VERSION 5.8 ;
BUSBITCHARS "[]" ;
DIVIDERCHAR "/" ;
UNITS
    DATABASE MICRONS 1000 ;
END UNITS

VIA stack_unit_16_8_via1_2_1000_440_1_2_410_410
  VIARULE via1Array ;
  CUTSIZE 0.19 0.19 ;
  LAYERS Metal1 Via1 Metal2 ;
  CUTSPACING 0.22 0.22 ;
  ENCLOSURE 0.05 0.125 0.005 0.05 ;
  ROWCOL 1 2 ;
END stack_unit_16_8_via1_2_1000_440_1_2_410_410

VIA stack_unit_16_8_via2_3_1000_440_1_2_410_410
  VIARULE via2Array ;
  CUTSIZE 0.19 0.19 ;
  LAYERS Metal2 Via2 Metal3 ;
  CUTSPACING 0.22 0.22 ;
  ENCLOSURE 0.005 0.05 0.05 0.005 ;
  ROWCOL 1 2 ;
END stack_unit_16_8_via2_3_1000_440_1_2_410_410

VIA stack_unit_16_8_via3_4_1000_440_1_2_410_410
  VIARULE via3Array ;
  CUTSIZE 0.19 0.19 ;
  LAYERS Metal3 Via3 Metal4 ;
  CUTSPACING 0.22 0.22 ;
  ENCLOSURE 0.05 0.005 0.2 0.05 ;
  ROWCOL 1 2 ;
END stack_unit_16_8_via3_4_1000_440_1_2_410_410

VIA stack_unit_16_8_via4_5_1000_2000_1_1_840_840
  VIARULE viaTop1Array ;
  CUTSIZE 0.42 0.42 ;
  LAYERS Metal4 TopVia1 TopMetal1 ;
  CUTSPACING 0.42 0.42 ;
  ENCLOSURE 0.29 0.1 0.42 0.79 ;
END stack_unit_16_8_via4_5_1000_2000_1_1_840_840

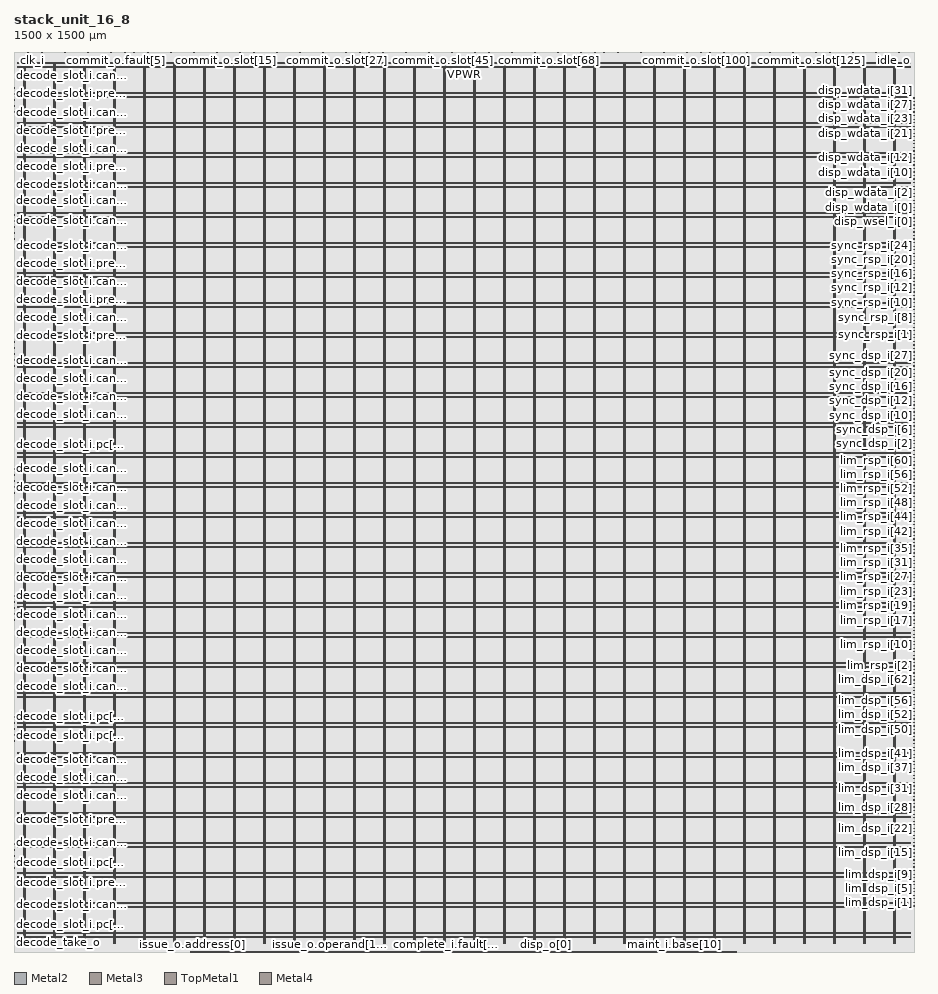
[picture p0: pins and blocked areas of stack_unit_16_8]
MACRO stack_unit_16_8
  FOREIGN stack_unit_16_8 0 0 ;
  CLASS BLOCK ;
  SIZE 1500 BY 1500 ;
  PIN clk_i
    DIRECTION INPUT ;
    USE SIGNAL ;
    PORT
      LAYER Metal2 ;
        RECT  31 1499.6 31.4 1500 ;
    END
  END clk_i
  PIN commit_o.fault[0]
    DIRECTION OUTPUT ;
    USE SIGNAL ;
    PORT
      LAYER Metal2 ;
        RECT  54.04 1499.6 54.44 1500 ;
    END
  END commit_o.fault[0]
  PIN commit_o.fault[1]
    DIRECTION OUTPUT ;
    USE SIGNAL ;
    PORT
      LAYER Metal2 ;
        RECT  77.08 1499.6 77.48 1500 ;
    END
  END commit_o.fault[1]
  PIN commit_o.fault[2]
    DIRECTION OUTPUT ;
    USE SIGNAL ;
    PORT
      LAYER Metal2 ;
        RECT  100.12 1499.6 100.52 1500 ;
    END
  END commit_o.fault[2]
  PIN commit_o.fault[3]
    DIRECTION OUTPUT ;
    USE SIGNAL ;
    PORT
      LAYER Metal2 ;
        RECT  123.16 1499.6 123.56 1500 ;
    END
  END commit_o.fault[3]
  PIN commit_o.fault[4]
    DIRECTION OUTPUT ;
    USE SIGNAL ;
    PORT
      LAYER Metal2 ;
        RECT  146.2 1499.6 146.6 1500 ;
    END
  END commit_o.fault[4]
  PIN commit_o.fault[5]
    DIRECTION OUTPUT ;
    USE SIGNAL ;
    PORT
      LAYER Metal2 ;
        RECT  169.24 1499.6 169.64 1500 ;
    END
  END commit_o.fault[5]
  PIN commit_o.fault[6]
    DIRECTION OUTPUT ;
    USE SIGNAL ;
    PORT
      LAYER Metal2 ;
        RECT  192.28 1499.6 192.68 1500 ;
    END
  END commit_o.fault[6]
  PIN commit_o.fault[7]
    DIRECTION OUTPUT ;
    USE SIGNAL ;
    PORT
      LAYER Metal2 ;
        RECT  215.32 1499.6 215.72 1500 ;
    END
  END commit_o.fault[7]
  PIN commit_o.fault[8]
    DIRECTION OUTPUT ;
    USE SIGNAL ;
    PORT
      LAYER Metal2 ;
        RECT  238.36 1499.6 238.76 1500 ;
    END
  END commit_o.fault[8]
  PIN commit_o.slot[0]
    DIRECTION OUTPUT ;
    USE SIGNAL ;
    PORT
      LAYER Metal2 ;
        RECT  61.72 1499.6 62.12 1500 ;
    END
  END commit_o.slot[0]
  PIN commit_o.slot[100]
    DIRECTION OUTPUT ;
    USE SIGNAL ;
    PORT
      LAYER Metal2 ;
        RECT  1136.92 1499.6 1137.32 1500 ;
    END
  END commit_o.slot[100]
  PIN commit_o.slot[101]
    DIRECTION OUTPUT ;
    USE SIGNAL ;
    PORT
      LAYER Metal2 ;
        RECT  1144.6 1499.6 1145 1500 ;
    END
  END commit_o.slot[101]
  PIN commit_o.slot[102]
    DIRECTION OUTPUT ;
    USE SIGNAL ;
    PORT
      LAYER Metal2 ;
        RECT  1152.28 1499.6 1152.68 1500 ;
    END
  END commit_o.slot[102]
  PIN commit_o.slot[103]
    DIRECTION OUTPUT ;
    USE SIGNAL ;
    PORT
      LAYER Metal2 ;
        RECT  1159.96 1499.6 1160.36 1500 ;
    END
  END commit_o.slot[103]
  PIN commit_o.slot[104]
    DIRECTION OUTPUT ;
    USE SIGNAL ;
    PORT
      LAYER Metal2 ;
        RECT  1167.64 1499.6 1168.04 1500 ;
    END
  END commit_o.slot[104]
  PIN commit_o.slot[105]
    DIRECTION OUTPUT ;
    USE SIGNAL ;
    PORT
      LAYER Metal2 ;
        RECT  1175.32 1499.6 1175.72 1500 ;
    END
  END commit_o.slot[105]
  PIN commit_o.slot[106]
    DIRECTION OUTPUT ;
    USE SIGNAL ;
    PORT
      LAYER Metal2 ;
        RECT  1183 1499.6 1183.4 1500 ;
    END
  END commit_o.slot[106]
  PIN commit_o.slot[107]
    DIRECTION OUTPUT ;
    USE SIGNAL ;
    PORT
      LAYER Metal2 ;
        RECT  1190.68 1499.6 1191.08 1500 ;
    END
  END commit_o.slot[107]
  PIN commit_o.slot[108]
    DIRECTION OUTPUT ;
    USE SIGNAL ;
    PORT
      LAYER Metal2 ;
        RECT  1198.36 1499.6 1198.76 1500 ;
    END
  END commit_o.slot[108]
  PIN commit_o.slot[109]
    DIRECTION OUTPUT ;
    USE SIGNAL ;
    PORT
      LAYER Metal2 ;
        RECT  1206.04 1499.6 1206.44 1500 ;
    END
  END commit_o.slot[109]
  PIN commit_o.slot[10]
    DIRECTION OUTPUT ;
    USE SIGNAL ;
    PORT
      LAYER Metal2 ;
        RECT  276.76 1499.6 277.16 1500 ;
    END
  END commit_o.slot[10]
  PIN commit_o.slot[110]
    DIRECTION OUTPUT ;
    USE SIGNAL ;
    PORT
      LAYER Metal2 ;
        RECT  1213.72 1499.6 1214.12 1500 ;
    END
  END commit_o.slot[110]
  PIN commit_o.slot[111]
    DIRECTION OUTPUT ;
    USE SIGNAL ;
    PORT
      LAYER Metal2 ;
        RECT  1221.4 1499.6 1221.8 1500 ;
    END
  END commit_o.slot[111]
  PIN commit_o.slot[112]
    DIRECTION OUTPUT ;
    USE SIGNAL ;
    PORT
      LAYER Metal2 ;
        RECT  1229.08 1499.6 1229.48 1500 ;
    END
  END commit_o.slot[112]
  PIN commit_o.slot[113]
    DIRECTION OUTPUT ;
    USE SIGNAL ;
    PORT
      LAYER Metal2 ;
        RECT  1236.76 1499.6 1237.16 1500 ;
    END
  END commit_o.slot[113]
  PIN commit_o.slot[114]
    DIRECTION OUTPUT ;
    USE SIGNAL ;
    PORT
      LAYER Metal2 ;
        RECT  1244.44 1499.6 1244.84 1500 ;
    END
  END commit_o.slot[114]
  PIN commit_o.slot[115]
    DIRECTION OUTPUT ;
    USE SIGNAL ;
    PORT
      LAYER Metal2 ;
        RECT  1252.12 1499.6 1252.52 1500 ;
    END
  END commit_o.slot[115]
  PIN commit_o.slot[116]
    DIRECTION OUTPUT ;
    USE SIGNAL ;
    PORT
      LAYER Metal2 ;
        RECT  1259.8 1499.6 1260.2 1500 ;
    END
  END commit_o.slot[116]
  PIN commit_o.slot[117]
    DIRECTION OUTPUT ;
    USE SIGNAL ;
    PORT
      LAYER Metal2 ;
        RECT  1267.48 1499.6 1267.88 1500 ;
    END
  END commit_o.slot[117]
  PIN commit_o.slot[118]
    DIRECTION OUTPUT ;
    USE SIGNAL ;
    PORT
      LAYER Metal2 ;
        RECT  1275.16 1499.6 1275.56 1500 ;
    END
  END commit_o.slot[118]
  PIN commit_o.slot[119]
    DIRECTION OUTPUT ;
    USE SIGNAL ;
    PORT
      LAYER Metal2 ;
        RECT  1282.84 1499.6 1283.24 1500 ;
    END
  END commit_o.slot[119]
  PIN commit_o.slot[11]
    DIRECTION OUTPUT ;
    USE SIGNAL ;
    PORT
      LAYER Metal2 ;
        RECT  292.12 1499.6 292.52 1500 ;
    END
  END commit_o.slot[11]
  PIN commit_o.slot[120]
    DIRECTION OUTPUT ;
    USE SIGNAL ;
    PORT
      LAYER Metal2 ;
        RECT  1290.52 1499.6 1290.92 1500 ;
    END
  END commit_o.slot[120]
  PIN commit_o.slot[121]
    DIRECTION OUTPUT ;
    USE SIGNAL ;
    PORT
      LAYER Metal2 ;
        RECT  1298.2 1499.6 1298.6 1500 ;
    END
  END commit_o.slot[121]
  PIN commit_o.slot[122]
    DIRECTION OUTPUT ;
    USE SIGNAL ;
    PORT
      LAYER Metal2 ;
        RECT  1305.88 1499.6 1306.28 1500 ;
    END
  END commit_o.slot[122]
  PIN commit_o.slot[123]
    DIRECTION OUTPUT ;
    USE SIGNAL ;
    PORT
      LAYER Metal2 ;
        RECT  1313.56 1499.6 1313.96 1500 ;
    END
  END commit_o.slot[123]
  PIN commit_o.slot[124]
    DIRECTION OUTPUT ;
    USE SIGNAL ;
    PORT
      LAYER Metal2 ;
        RECT  1321.24 1499.6 1321.64 1500 ;
    END
  END commit_o.slot[124]
  PIN commit_o.slot[125]
    DIRECTION OUTPUT ;
    USE SIGNAL ;
    PORT
      LAYER Metal2 ;
        RECT  1328.92 1499.6 1329.32 1500 ;
    END
  END commit_o.slot[125]
  PIN commit_o.slot[126]
    DIRECTION OUTPUT ;
    USE SIGNAL ;
    PORT
      LAYER Metal2 ;
        RECT  1336.6 1499.6 1337 1500 ;
    END
  END commit_o.slot[126]
  PIN commit_o.slot[127]
    DIRECTION OUTPUT ;
    USE SIGNAL ;
    PORT
      LAYER Metal2 ;
        RECT  1344.28 1499.6 1344.68 1500 ;
    END
  END commit_o.slot[127]
  PIN commit_o.slot[128]
    DIRECTION OUTPUT ;
    USE SIGNAL ;
    PORT
      LAYER Metal2 ;
        RECT  1351.96 1499.6 1352.36 1500 ;
    END
  END commit_o.slot[128]
  PIN commit_o.slot[129]
    DIRECTION OUTPUT ;
    USE SIGNAL ;
    PORT
      LAYER Metal2 ;
        RECT  1359.64 1499.6 1360.04 1500 ;
    END
  END commit_o.slot[129]
  PIN commit_o.slot[12]
    DIRECTION OUTPUT ;
    USE SIGNAL ;
    PORT
      LAYER Metal2 ;
        RECT  307.48 1499.6 307.88 1500 ;
    END
  END commit_o.slot[12]
  PIN commit_o.slot[130]
    DIRECTION OUTPUT ;
    USE SIGNAL ;
    PORT
      LAYER Metal2 ;
        RECT  1367.32 1499.6 1367.72 1500 ;
    END
  END commit_o.slot[130]
  PIN commit_o.slot[131]
    DIRECTION OUTPUT ;
    USE SIGNAL ;
    PORT
      LAYER Metal2 ;
        RECT  1375 1499.6 1375.4 1500 ;
    END
  END commit_o.slot[131]
  PIN commit_o.slot[132]
    DIRECTION OUTPUT ;
    USE SIGNAL ;
    PORT
      LAYER Metal2 ;
        RECT  1382.68 1499.6 1383.08 1500 ;
    END
  END commit_o.slot[132]
  PIN commit_o.slot[133]
    DIRECTION OUTPUT ;
    USE SIGNAL ;
    PORT
      LAYER Metal2 ;
        RECT  1390.36 1499.6 1390.76 1500 ;
    END
  END commit_o.slot[133]
  PIN commit_o.slot[134]
    DIRECTION OUTPUT ;
    USE SIGNAL ;
    PORT
      LAYER Metal2 ;
        RECT  1398.04 1499.6 1398.44 1500 ;
    END
  END commit_o.slot[134]
  PIN commit_o.slot[135]
    DIRECTION OUTPUT ;
    USE SIGNAL ;
    PORT
      LAYER Metal2 ;
        RECT  1405.72 1499.6 1406.12 1500 ;
    END
  END commit_o.slot[135]
  PIN commit_o.slot[136]
    DIRECTION OUTPUT ;
    USE SIGNAL ;
    PORT
      LAYER Metal2 ;
        RECT  1413.4 1499.6 1413.8 1500 ;
    END
  END commit_o.slot[136]
  PIN commit_o.slot[137]
    DIRECTION OUTPUT ;
    USE SIGNAL ;
    PORT
      LAYER Metal2 ;
        RECT  1421.08 1499.6 1421.48 1500 ;
    END
  END commit_o.slot[137]
  PIN commit_o.slot[138]
    DIRECTION OUTPUT ;
    USE SIGNAL ;
    PORT
      LAYER Metal2 ;
        RECT  1428.76 1499.6 1429.16 1500 ;
    END
  END commit_o.slot[138]
  PIN commit_o.slot[139]
    DIRECTION OUTPUT ;
    USE SIGNAL ;
    PORT
      LAYER Metal2 ;
        RECT  1436.44 1499.6 1436.84 1500 ;
    END
  END commit_o.slot[139]
  PIN commit_o.slot[13]
    DIRECTION OUTPUT ;
    USE SIGNAL ;
    PORT
      LAYER Metal2 ;
        RECT  322.84 1499.6 323.24 1500 ;
    END
  END commit_o.slot[13]
  PIN commit_o.slot[140]
    DIRECTION OUTPUT ;
    USE SIGNAL ;
    PORT
      LAYER Metal2 ;
        RECT  1444.12 1499.6 1444.52 1500 ;
    END
  END commit_o.slot[140]
  PIN commit_o.slot[141]
    DIRECTION OUTPUT ;
    USE SIGNAL ;
    PORT
      LAYER Metal2 ;
        RECT  1451.8 1499.6 1452.2 1500 ;
    END
  END commit_o.slot[141]
  PIN commit_o.slot[142]
    DIRECTION OUTPUT ;
    USE SIGNAL ;
    PORT
      LAYER Metal2 ;
        RECT  1459.48 1499.6 1459.88 1500 ;
    END
  END commit_o.slot[142]
  PIN commit_o.slot[14]
    DIRECTION OUTPUT ;
    USE SIGNAL ;
    PORT
      LAYER Metal2 ;
        RECT  338.2 1499.6 338.6 1500 ;
    END
  END commit_o.slot[14]
  PIN commit_o.slot[15]
    DIRECTION OUTPUT ;
    USE SIGNAL ;
    PORT
      LAYER Metal2 ;
        RECT  353.56 1499.6 353.96 1500 ;
    END
  END commit_o.slot[15]
  PIN commit_o.slot[16]
    DIRECTION OUTPUT ;
    USE SIGNAL ;
    PORT
      LAYER Metal2 ;
        RECT  368.92 1499.6 369.32 1500 ;
    END
  END commit_o.slot[16]
  PIN commit_o.slot[17]
    DIRECTION OUTPUT ;
    USE SIGNAL ;
    PORT
      LAYER Metal2 ;
        RECT  384.28 1499.6 384.68 1500 ;
    END
  END commit_o.slot[17]
  PIN commit_o.slot[18]
    DIRECTION OUTPUT ;
    USE SIGNAL ;
    PORT
      LAYER Metal2 ;
        RECT  399.64 1499.6 400.04 1500 ;
    END
  END commit_o.slot[18]
  PIN commit_o.slot[19]
    DIRECTION OUTPUT ;
    USE SIGNAL ;
    PORT
      LAYER Metal2 ;
        RECT  415 1499.6 415.4 1500 ;
    END
  END commit_o.slot[19]
  PIN commit_o.slot[1]
    DIRECTION OUTPUT ;
    USE SIGNAL ;
    PORT
      LAYER Metal2 ;
        RECT  84.76 1499.6 85.16 1500 ;
    END
  END commit_o.slot[1]
  PIN commit_o.slot[20]
    DIRECTION OUTPUT ;
    USE SIGNAL ;
    PORT
      LAYER Metal2 ;
        RECT  430.36 1499.6 430.76 1500 ;
    END
  END commit_o.slot[20]
  PIN commit_o.slot[21]
    DIRECTION OUTPUT ;
    USE SIGNAL ;
    PORT
      LAYER Metal2 ;
        RECT  445.72 1499.6 446.12 1500 ;
    END
  END commit_o.slot[21]
  PIN commit_o.slot[22]
    DIRECTION OUTPUT ;
    USE SIGNAL ;
    PORT
      LAYER Metal2 ;
        RECT  461.08 1499.6 461.48 1500 ;
    END
  END commit_o.slot[22]
  PIN commit_o.slot[23]
    DIRECTION OUTPUT ;
    USE SIGNAL ;
    PORT
      LAYER Metal2 ;
        RECT  476.44 1499.6 476.84 1500 ;
    END
  END commit_o.slot[23]
  PIN commit_o.slot[24]
    DIRECTION OUTPUT ;
    USE SIGNAL ;
    PORT
      LAYER Metal2 ;
        RECT  491.8 1499.6 492.2 1500 ;
    END
  END commit_o.slot[24]
  PIN commit_o.slot[25]
    DIRECTION OUTPUT ;
    USE SIGNAL ;
    PORT
      LAYER Metal2 ;
        RECT  507.16 1499.6 507.56 1500 ;
    END
  END commit_o.slot[25]
  PIN commit_o.slot[26]
    DIRECTION OUTPUT ;
    USE SIGNAL ;
    PORT
      LAYER Metal2 ;
        RECT  522.52 1499.6 522.92 1500 ;
    END
  END commit_o.slot[26]
  PIN commit_o.slot[27]
    DIRECTION OUTPUT ;
    USE SIGNAL ;
    PORT
      LAYER Metal2 ;
        RECT  537.88 1499.6 538.28 1500 ;
    END
  END commit_o.slot[27]
  PIN commit_o.slot[28]
    DIRECTION OUTPUT ;
    USE SIGNAL ;
    PORT
      LAYER Metal2 ;
        RECT  553.24 1499.6 553.64 1500 ;
    END
  END commit_o.slot[28]
  PIN commit_o.slot[29]
    DIRECTION OUTPUT ;
    USE SIGNAL ;
    PORT
      LAYER Metal2 ;
        RECT  568.6 1499.6 569 1500 ;
    END
  END commit_o.slot[29]
  PIN commit_o.slot[2]
    DIRECTION OUTPUT ;
    USE SIGNAL ;
    PORT
      LAYER Metal2 ;
        RECT  107.8 1499.6 108.2 1500 ;
    END
  END commit_o.slot[2]
  PIN commit_o.slot[30]
    DIRECTION OUTPUT ;
    USE SIGNAL ;
    PORT
      LAYER Metal2 ;
        RECT  583.96 1499.6 584.36 1500 ;
    END
  END commit_o.slot[30]
  PIN commit_o.slot[31]
    DIRECTION OUTPUT ;
    USE SIGNAL ;
    PORT
      LAYER Metal2 ;
        RECT  599.32 1499.6 599.72 1500 ;
    END
  END commit_o.slot[31]
  PIN commit_o.slot[32]
    DIRECTION OUTPUT ;
    USE SIGNAL ;
    PORT
      LAYER Metal2 ;
        RECT  614.68 1499.6 615.08 1500 ;
    END
  END commit_o.slot[32]
  PIN commit_o.slot[33]
    DIRECTION OUTPUT ;
    USE SIGNAL ;
    PORT
      LAYER Metal2 ;
        RECT  622.36 1499.6 622.76 1500 ;
    END
  END commit_o.slot[33]
  PIN commit_o.slot[34]
    DIRECTION OUTPUT ;
    USE SIGNAL ;
    PORT
      LAYER Metal2 ;
        RECT  630.04 1499.6 630.44 1500 ;
    END
  END commit_o.slot[34]
  PIN commit_o.slot[35]
    DIRECTION OUTPUT ;
    USE SIGNAL ;
    PORT
      LAYER Metal2 ;
        RECT  637.72 1499.6 638.12 1500 ;
    END
  END commit_o.slot[35]
  PIN commit_o.slot[36]
    DIRECTION OUTPUT ;
    USE SIGNAL ;
    PORT
      LAYER Metal2 ;
        RECT  645.4 1499.6 645.8 1500 ;
    END
  END commit_o.slot[36]
  PIN commit_o.slot[37]
    DIRECTION OUTPUT ;
    USE SIGNAL ;
    PORT
      LAYER Metal2 ;
        RECT  653.08 1499.6 653.48 1500 ;
    END
  END commit_o.slot[37]
  PIN commit_o.slot[38]
    DIRECTION OUTPUT ;
    USE SIGNAL ;
    PORT
      LAYER Metal2 ;
        RECT  660.76 1499.6 661.16 1500 ;
    END
  END commit_o.slot[38]
  PIN commit_o.slot[39]
    DIRECTION OUTPUT ;
    USE SIGNAL ;
    PORT
      LAYER Metal2 ;
        RECT  668.44 1499.6 668.84 1500 ;
    END
  END commit_o.slot[39]
  PIN commit_o.slot[3]
    DIRECTION OUTPUT ;
    USE SIGNAL ;
    PORT
      LAYER Metal2 ;
        RECT  130.84 1499.6 131.24 1500 ;
    END
  END commit_o.slot[3]
  PIN commit_o.slot[40]
    DIRECTION OUTPUT ;
    USE SIGNAL ;
    PORT
      LAYER Metal2 ;
        RECT  676.12 1499.6 676.52 1500 ;
    END
  END commit_o.slot[40]
  PIN commit_o.slot[41]
    DIRECTION OUTPUT ;
    USE SIGNAL ;
    PORT
      LAYER Metal2 ;
        RECT  683.8 1499.6 684.2 1500 ;
    END
  END commit_o.slot[41]
  PIN commit_o.slot[42]
    DIRECTION OUTPUT ;
    USE SIGNAL ;
    PORT
      LAYER Metal2 ;
        RECT  691.48 1499.6 691.88 1500 ;
    END
  END commit_o.slot[42]
  PIN commit_o.slot[43]
    DIRECTION OUTPUT ;
    USE SIGNAL ;
    PORT
      LAYER Metal2 ;
        RECT  699.16 1499.6 699.56 1500 ;
    END
  END commit_o.slot[43]
  PIN commit_o.slot[44]
    DIRECTION OUTPUT ;
    USE SIGNAL ;
    PORT
      LAYER Metal2 ;
        RECT  706.84 1499.6 707.24 1500 ;
    END
  END commit_o.slot[44]
  PIN commit_o.slot[45]
    DIRECTION OUTPUT ;
    USE SIGNAL ;
    PORT
      LAYER Metal2 ;
        RECT  714.52 1499.6 714.92 1500 ;
    END
  END commit_o.slot[45]
  PIN commit_o.slot[46]
    DIRECTION OUTPUT ;
    USE SIGNAL ;
    PORT
      LAYER Metal2 ;
        RECT  722.2 1499.6 722.6 1500 ;
    END
  END commit_o.slot[46]
  PIN commit_o.slot[47]
    DIRECTION OUTPUT ;
    USE SIGNAL ;
    PORT
      LAYER Metal2 ;
        RECT  729.88 1499.6 730.28 1500 ;
    END
  END commit_o.slot[47]
  PIN commit_o.slot[48]
    DIRECTION OUTPUT ;
    USE SIGNAL ;
    PORT
      LAYER Metal2 ;
        RECT  737.56 1499.6 737.96 1500 ;
    END
  END commit_o.slot[48]
  PIN commit_o.slot[49]
    DIRECTION OUTPUT ;
    USE SIGNAL ;
    PORT
      LAYER Metal2 ;
        RECT  745.24 1499.6 745.64 1500 ;
    END
  END commit_o.slot[49]
  PIN commit_o.slot[4]
    DIRECTION OUTPUT ;
    USE SIGNAL ;
    PORT
      LAYER Metal2 ;
        RECT  153.88 1499.6 154.28 1500 ;
    END
  END commit_o.slot[4]
  PIN commit_o.slot[50]
    DIRECTION OUTPUT ;
    USE SIGNAL ;
    PORT
      LAYER Metal2 ;
        RECT  752.92 1499.6 753.32 1500 ;
    END
  END commit_o.slot[50]
  PIN commit_o.slot[51]
    DIRECTION OUTPUT ;
    USE SIGNAL ;
    PORT
      LAYER Metal2 ;
        RECT  760.6 1499.6 761 1500 ;
    END
  END commit_o.slot[51]
  PIN commit_o.slot[52]
    DIRECTION OUTPUT ;
    USE SIGNAL ;
    PORT
      LAYER Metal2 ;
        RECT  768.28 1499.6 768.68 1500 ;
    END
  END commit_o.slot[52]
  PIN commit_o.slot[53]
    DIRECTION OUTPUT ;
    USE SIGNAL ;
    PORT
      LAYER Metal2 ;
        RECT  775.96 1499.6 776.36 1500 ;
    END
  END commit_o.slot[53]
  PIN commit_o.slot[54]
    DIRECTION OUTPUT ;
    USE SIGNAL ;
    PORT
      LAYER Metal2 ;
        RECT  783.64 1499.6 784.04 1500 ;
    END
  END commit_o.slot[54]
  PIN commit_o.slot[55]
    DIRECTION OUTPUT ;
    USE SIGNAL ;
    PORT
      LAYER Metal2 ;
        RECT  791.32 1499.6 791.72 1500 ;
    END
  END commit_o.slot[55]
  PIN commit_o.slot[56]
    DIRECTION OUTPUT ;
    USE SIGNAL ;
    PORT
      LAYER Metal2 ;
        RECT  799 1499.6 799.4 1500 ;
    END
  END commit_o.slot[56]
  PIN commit_o.slot[57]
    DIRECTION OUTPUT ;
    USE SIGNAL ;
    PORT
      LAYER Metal2 ;
        RECT  806.68 1499.6 807.08 1500 ;
    END
  END commit_o.slot[57]
  PIN commit_o.slot[58]
    DIRECTION OUTPUT ;
    USE SIGNAL ;
    PORT
      LAYER Metal2 ;
        RECT  814.36 1499.6 814.76 1500 ;
    END
  END commit_o.slot[58]
  PIN commit_o.slot[59]
    DIRECTION OUTPUT ;
    USE SIGNAL ;
    PORT
      LAYER Metal2 ;
        RECT  822.04 1499.6 822.44 1500 ;
    END
  END commit_o.slot[59]
  PIN commit_o.slot[5]
    DIRECTION OUTPUT ;
    USE SIGNAL ;
    PORT
      LAYER Metal2 ;
        RECT  176.92 1499.6 177.32 1500 ;
    END
  END commit_o.slot[5]
  PIN commit_o.slot[60]
    DIRECTION OUTPUT ;
    USE SIGNAL ;
    PORT
      LAYER Metal2 ;
        RECT  829.72 1499.6 830.12 1500 ;
    END
  END commit_o.slot[60]
  PIN commit_o.slot[61]
    DIRECTION OUTPUT ;
    USE SIGNAL ;
    PORT
      LAYER Metal2 ;
        RECT  837.4 1499.6 837.8 1500 ;
    END
  END commit_o.slot[61]
  PIN commit_o.slot[62]
    DIRECTION OUTPUT ;
    USE SIGNAL ;
    PORT
      LAYER Metal2 ;
        RECT  845.08 1499.6 845.48 1500 ;
    END
  END commit_o.slot[62]
  PIN commit_o.slot[63]
    DIRECTION OUTPUT ;
    USE SIGNAL ;
    PORT
      LAYER Metal2 ;
        RECT  852.76 1499.6 853.16 1500 ;
    END
  END commit_o.slot[63]
  PIN commit_o.slot[64]
    DIRECTION OUTPUT ;
    USE SIGNAL ;
    PORT
      LAYER Metal2 ;
        RECT  860.44 1499.6 860.84 1500 ;
    END
  END commit_o.slot[64]
  PIN commit_o.slot[65]
    DIRECTION OUTPUT ;
    USE SIGNAL ;
    PORT
      LAYER Metal2 ;
        RECT  868.12 1499.6 868.52 1500 ;
    END
  END commit_o.slot[65]
  PIN commit_o.slot[66]
    DIRECTION OUTPUT ;
    USE SIGNAL ;
    PORT
      LAYER Metal2 ;
        RECT  875.8 1499.6 876.2 1500 ;
    END
  END commit_o.slot[66]
  PIN commit_o.slot[67]
    DIRECTION OUTPUT ;
    USE SIGNAL ;
    PORT
      LAYER Metal2 ;
        RECT  883.48 1499.6 883.88 1500 ;
    END
  END commit_o.slot[67]
  PIN commit_o.slot[68]
    DIRECTION OUTPUT ;
    USE SIGNAL ;
    PORT
      LAYER Metal2 ;
        RECT  891.16 1499.6 891.56 1500 ;
    END
  END commit_o.slot[68]
  PIN commit_o.slot[69]
    DIRECTION OUTPUT ;
    USE SIGNAL ;
    PORT
      LAYER Metal2 ;
        RECT  898.84 1499.6 899.24 1500 ;
    END
  END commit_o.slot[69]
  PIN commit_o.slot[6]
    DIRECTION OUTPUT ;
    USE SIGNAL ;
    PORT
      LAYER Metal2 ;
        RECT  199.96 1499.6 200.36 1500 ;
    END
  END commit_o.slot[6]
  PIN commit_o.slot[70]
    DIRECTION OUTPUT ;
    USE SIGNAL ;
    PORT
      LAYER Metal2 ;
        RECT  906.52 1499.6 906.92 1500 ;
    END
  END commit_o.slot[70]
  PIN commit_o.slot[71]
    DIRECTION OUTPUT ;
    USE SIGNAL ;
    PORT
      LAYER Metal2 ;
        RECT  914.2 1499.6 914.6 1500 ;
    END
  END commit_o.slot[71]
  PIN commit_o.slot[72]
    DIRECTION OUTPUT ;
    USE SIGNAL ;
    PORT
      LAYER Metal2 ;
        RECT  921.88 1499.6 922.28 1500 ;
    END
  END commit_o.slot[72]
  PIN commit_o.slot[73]
    DIRECTION OUTPUT ;
    USE SIGNAL ;
    PORT
      LAYER Metal2 ;
        RECT  929.56 1499.6 929.96 1500 ;
    END
  END commit_o.slot[73]
  PIN commit_o.slot[74]
    DIRECTION OUTPUT ;
    USE SIGNAL ;
    PORT
      LAYER Metal2 ;
        RECT  937.24 1499.6 937.64 1500 ;
    END
  END commit_o.slot[74]
  PIN commit_o.slot[75]
    DIRECTION OUTPUT ;
    USE SIGNAL ;
    PORT
      LAYER Metal2 ;
        RECT  944.92 1499.6 945.32 1500 ;
    END
  END commit_o.slot[75]
  PIN commit_o.slot[76]
    DIRECTION OUTPUT ;
    USE SIGNAL ;
    PORT
      LAYER Metal2 ;
        RECT  952.6 1499.6 953 1500 ;
    END
  END commit_o.slot[76]
  PIN commit_o.slot[77]
    DIRECTION OUTPUT ;
    USE SIGNAL ;
    PORT
      LAYER Metal2 ;
        RECT  960.28 1499.6 960.68 1500 ;
    END
  END commit_o.slot[77]
  PIN commit_o.slot[78]
    DIRECTION OUTPUT ;
    USE SIGNAL ;
    PORT
      LAYER Metal2 ;
        RECT  967.96 1499.6 968.36 1500 ;
    END
  END commit_o.slot[78]
  PIN commit_o.slot[79]
    DIRECTION OUTPUT ;
    USE SIGNAL ;
    PORT
      LAYER Metal2 ;
        RECT  975.64 1499.6 976.04 1500 ;
    END
  END commit_o.slot[79]
  PIN commit_o.slot[7]
    DIRECTION OUTPUT ;
    USE SIGNAL ;
    PORT
      LAYER Metal2 ;
        RECT  223 1499.6 223.4 1500 ;
    END
  END commit_o.slot[7]
  PIN commit_o.slot[80]
    DIRECTION OUTPUT ;
    USE SIGNAL ;
    PORT
      LAYER Metal2 ;
        RECT  983.32 1499.6 983.72 1500 ;
    END
  END commit_o.slot[80]
  PIN commit_o.slot[81]
    DIRECTION OUTPUT ;
    USE SIGNAL ;
    PORT
      LAYER Metal2 ;
        RECT  991 1499.6 991.4 1500 ;
    END
  END commit_o.slot[81]
  PIN commit_o.slot[82]
    DIRECTION OUTPUT ;
    USE SIGNAL ;
    PORT
      LAYER Metal2 ;
        RECT  998.68 1499.6 999.08 1500 ;
    END
  END commit_o.slot[82]
  PIN commit_o.slot[83]
    DIRECTION OUTPUT ;
    USE SIGNAL ;
    PORT
      LAYER Metal2 ;
        RECT  1006.36 1499.6 1006.76 1500 ;
    END
  END commit_o.slot[83]
  PIN commit_o.slot[84]
    DIRECTION OUTPUT ;
    USE SIGNAL ;
    PORT
      LAYER Metal2 ;
        RECT  1014.04 1499.6 1014.44 1500 ;
    END
  END commit_o.slot[84]
  PIN commit_o.slot[85]
    DIRECTION OUTPUT ;
    USE SIGNAL ;
    PORT
      LAYER Metal2 ;
        RECT  1021.72 1499.6 1022.12 1500 ;
    END
  END commit_o.slot[85]
  PIN commit_o.slot[86]
    DIRECTION OUTPUT ;
    USE SIGNAL ;
    PORT
      LAYER Metal2 ;
        RECT  1029.4 1499.6 1029.8 1500 ;
    END
  END commit_o.slot[86]
  PIN commit_o.slot[87]
    DIRECTION OUTPUT ;
    USE SIGNAL ;
    PORT
      LAYER Metal2 ;
        RECT  1037.08 1499.6 1037.48 1500 ;
    END
  END commit_o.slot[87]
  PIN commit_o.slot[88]
    DIRECTION OUTPUT ;
    USE SIGNAL ;
    PORT
      LAYER Metal2 ;
        RECT  1044.76 1499.6 1045.16 1500 ;
    END
  END commit_o.slot[88]
  PIN commit_o.slot[89]
    DIRECTION OUTPUT ;
    USE SIGNAL ;
    PORT
      LAYER Metal2 ;
        RECT  1052.44 1499.6 1052.84 1500 ;
    END
  END commit_o.slot[89]
  PIN commit_o.slot[8]
    DIRECTION OUTPUT ;
    USE SIGNAL ;
    PORT
      LAYER Metal2 ;
        RECT  246.04 1499.6 246.44 1500 ;
    END
  END commit_o.slot[8]
  PIN commit_o.slot[90]
    DIRECTION OUTPUT ;
    USE SIGNAL ;
    PORT
      LAYER Metal2 ;
        RECT  1060.12 1499.6 1060.52 1500 ;
    END
  END commit_o.slot[90]
  PIN commit_o.slot[91]
    DIRECTION OUTPUT ;
    USE SIGNAL ;
    PORT
      LAYER Metal2 ;
        RECT  1067.8 1499.6 1068.2 1500 ;
    END
  END commit_o.slot[91]
  PIN commit_o.slot[92]
    DIRECTION OUTPUT ;
    USE SIGNAL ;
    PORT
      LAYER Metal2 ;
        RECT  1075.48 1499.6 1075.88 1500 ;
    END
  END commit_o.slot[92]
  PIN commit_o.slot[93]
    DIRECTION OUTPUT ;
    USE SIGNAL ;
    PORT
      LAYER Metal2 ;
        RECT  1083.16 1499.6 1083.56 1500 ;
    END
  END commit_o.slot[93]
  PIN commit_o.slot[94]
    DIRECTION OUTPUT ;
    USE SIGNAL ;
    PORT
      LAYER Metal2 ;
        RECT  1090.84 1499.6 1091.24 1500 ;
    END
  END commit_o.slot[94]
  PIN commit_o.slot[95]
    DIRECTION OUTPUT ;
    USE SIGNAL ;
    PORT
      LAYER Metal2 ;
        RECT  1098.52 1499.6 1098.92 1500 ;
    END
  END commit_o.slot[95]
  PIN commit_o.slot[96]
    DIRECTION OUTPUT ;
    USE SIGNAL ;
    PORT
      LAYER Metal2 ;
        RECT  1106.2 1499.6 1106.6 1500 ;
    END
  END commit_o.slot[96]
  PIN commit_o.slot[97]
    DIRECTION OUTPUT ;
    USE SIGNAL ;
    PORT
      LAYER Metal2 ;
        RECT  1113.88 1499.6 1114.28 1500 ;
    END
  END commit_o.slot[97]
  PIN commit_o.slot[98]
    DIRECTION OUTPUT ;
    USE SIGNAL ;
    PORT
      LAYER Metal2 ;
        RECT  1121.56 1499.6 1121.96 1500 ;
    END
  END commit_o.slot[98]
  PIN commit_o.slot[99]
    DIRECTION OUTPUT ;
    USE SIGNAL ;
    PORT
      LAYER Metal2 ;
        RECT  1129.24 1499.6 1129.64 1500 ;
    END
  END commit_o.slot[99]
  PIN commit_o.slot[9]
    DIRECTION OUTPUT ;
    USE SIGNAL ;
    PORT
      LAYER Metal2 ;
        RECT  261.4 1499.6 261.8 1500 ;
    END
  END commit_o.slot[9]
  PIN commit_o.taken
    DIRECTION OUTPUT ;
    USE SIGNAL ;
    PORT
      LAYER Metal2 ;
        RECT  38.68 1499.6 39.08 1500 ;
    END
  END commit_o.taken
  PIN commit_o.target[0]
    DIRECTION OUTPUT ;
    USE SIGNAL ;
    PORT
      LAYER Metal2 ;
        RECT  69.4 1499.6 69.8 1500 ;
    END
  END commit_o.target[0]
  PIN commit_o.target[10]
    DIRECTION OUTPUT ;
    USE SIGNAL ;
    PORT
      LAYER Metal2 ;
        RECT  284.44 1499.6 284.84 1500 ;
    END
  END commit_o.target[10]
  PIN commit_o.target[11]
    DIRECTION OUTPUT ;
    USE SIGNAL ;
    PORT
      LAYER Metal2 ;
        RECT  299.8 1499.6 300.2 1500 ;
    END
  END commit_o.target[11]
  PIN commit_o.target[12]
    DIRECTION OUTPUT ;
    USE SIGNAL ;
    PORT
      LAYER Metal2 ;
        RECT  315.16 1499.6 315.56 1500 ;
    END
  END commit_o.target[12]
  PIN commit_o.target[13]
    DIRECTION OUTPUT ;
    USE SIGNAL ;
    PORT
      LAYER Metal2 ;
        RECT  330.52 1499.6 330.92 1500 ;
    END
  END commit_o.target[13]
  PIN commit_o.target[14]
    DIRECTION OUTPUT ;
    USE SIGNAL ;
    PORT
      LAYER Metal2 ;
        RECT  345.88 1499.6 346.28 1500 ;
    END
  END commit_o.target[14]
  PIN commit_o.target[15]
    DIRECTION OUTPUT ;
    USE SIGNAL ;
    PORT
      LAYER Metal2 ;
        RECT  361.24 1499.6 361.64 1500 ;
    END
  END commit_o.target[15]
  PIN commit_o.target[16]
    DIRECTION OUTPUT ;
    USE SIGNAL ;
    PORT
      LAYER Metal2 ;
        RECT  376.6 1499.6 377 1500 ;
    END
  END commit_o.target[16]
  PIN commit_o.target[17]
    DIRECTION OUTPUT ;
    USE SIGNAL ;
    PORT
      LAYER Metal2 ;
        RECT  391.96 1499.6 392.36 1500 ;
    END
  END commit_o.target[17]
  PIN commit_o.target[18]
    DIRECTION OUTPUT ;
    USE SIGNAL ;
    PORT
      LAYER Metal2 ;
        RECT  407.32 1499.6 407.72 1500 ;
    END
  END commit_o.target[18]
  PIN commit_o.target[19]
    DIRECTION OUTPUT ;
    USE SIGNAL ;
    PORT
      LAYER Metal2 ;
        RECT  422.68 1499.6 423.08 1500 ;
    END
  END commit_o.target[19]
  PIN commit_o.target[1]
    DIRECTION OUTPUT ;
    USE SIGNAL ;
    PORT
      LAYER Metal2 ;
        RECT  92.44 1499.6 92.84 1500 ;
    END
  END commit_o.target[1]
  PIN commit_o.target[20]
    DIRECTION OUTPUT ;
    USE SIGNAL ;
    PORT
      LAYER Metal2 ;
        RECT  438.04 1499.6 438.44 1500 ;
    END
  END commit_o.target[20]
  PIN commit_o.target[21]
    DIRECTION OUTPUT ;
    USE SIGNAL ;
    PORT
      LAYER Metal2 ;
        RECT  453.4 1499.6 453.8 1500 ;
    END
  END commit_o.target[21]
  PIN commit_o.target[22]
    DIRECTION OUTPUT ;
    USE SIGNAL ;
    PORT
      LAYER Metal2 ;
        RECT  468.76 1499.6 469.16 1500 ;
    END
  END commit_o.target[22]
  PIN commit_o.target[23]
    DIRECTION OUTPUT ;
    USE SIGNAL ;
    PORT
      LAYER Metal2 ;
        RECT  484.12 1499.6 484.52 1500 ;
    END
  END commit_o.target[23]
  PIN commit_o.target[24]
    DIRECTION OUTPUT ;
    USE SIGNAL ;
    PORT
      LAYER Metal2 ;
        RECT  499.48 1499.6 499.88 1500 ;
    END
  END commit_o.target[24]
  PIN commit_o.target[25]
    DIRECTION OUTPUT ;
    USE SIGNAL ;
    PORT
      LAYER Metal2 ;
        RECT  514.84 1499.6 515.24 1500 ;
    END
  END commit_o.target[25]
  PIN commit_o.target[26]
    DIRECTION OUTPUT ;
    USE SIGNAL ;
    PORT
      LAYER Metal2 ;
        RECT  530.2 1499.6 530.6 1500 ;
    END
  END commit_o.target[26]
  PIN commit_o.target[27]
    DIRECTION OUTPUT ;
    USE SIGNAL ;
    PORT
      LAYER Metal2 ;
        RECT  545.56 1499.6 545.96 1500 ;
    END
  END commit_o.target[27]
  PIN commit_o.target[28]
    DIRECTION OUTPUT ;
    USE SIGNAL ;
    PORT
      LAYER Metal2 ;
        RECT  560.92 1499.6 561.32 1500 ;
    END
  END commit_o.target[28]
  PIN commit_o.target[29]
    DIRECTION OUTPUT ;
    USE SIGNAL ;
    PORT
      LAYER Metal2 ;
        RECT  576.28 1499.6 576.68 1500 ;
    END
  END commit_o.target[29]
  PIN commit_o.target[2]
    DIRECTION OUTPUT ;
    USE SIGNAL ;
    PORT
      LAYER Metal2 ;
        RECT  115.48 1499.6 115.88 1500 ;
    END
  END commit_o.target[2]
  PIN commit_o.target[30]
    DIRECTION OUTPUT ;
    USE SIGNAL ;
    PORT
      LAYER Metal2 ;
        RECT  591.64 1499.6 592.04 1500 ;
    END
  END commit_o.target[30]
  PIN commit_o.target[31]
    DIRECTION OUTPUT ;
    USE SIGNAL ;
    PORT
      LAYER Metal2 ;
        RECT  607 1499.6 607.4 1500 ;
    END
  END commit_o.target[31]
  PIN commit_o.target[3]
    DIRECTION OUTPUT ;
    USE SIGNAL ;
    PORT
      LAYER Metal2 ;
        RECT  138.52 1499.6 138.92 1500 ;
    END
  END commit_o.target[3]
  PIN commit_o.target[4]
    DIRECTION OUTPUT ;
    USE SIGNAL ;
    PORT
      LAYER Metal2 ;
        RECT  161.56 1499.6 161.96 1500 ;
    END
  END commit_o.target[4]
  PIN commit_o.target[5]
    DIRECTION OUTPUT ;
    USE SIGNAL ;
    PORT
      LAYER Metal2 ;
        RECT  184.6 1499.6 185 1500 ;
    END
  END commit_o.target[5]
  PIN commit_o.target[6]
    DIRECTION OUTPUT ;
    USE SIGNAL ;
    PORT
      LAYER Metal2 ;
        RECT  207.64 1499.6 208.04 1500 ;
    END
  END commit_o.target[6]
  PIN commit_o.target[7]
    DIRECTION OUTPUT ;
    USE SIGNAL ;
    PORT
      LAYER Metal2 ;
        RECT  230.68 1499.6 231.08 1500 ;
    END
  END commit_o.target[7]
  PIN commit_o.target[8]
    DIRECTION OUTPUT ;
    USE SIGNAL ;
    PORT
      LAYER Metal2 ;
        RECT  253.72 1499.6 254.12 1500 ;
    END
  END commit_o.target[8]
  PIN commit_o.target[9]
    DIRECTION OUTPUT ;
    USE SIGNAL ;
    PORT
      LAYER Metal2 ;
        RECT  269.08 1499.6 269.48 1500 ;
    END
  END commit_o.target[9]
  PIN commit_o.valid
    DIRECTION OUTPUT ;
    USE SIGNAL ;
    PORT
      LAYER Metal2 ;
        RECT  46.36 1499.6 46.76 1500 ;
    END
  END commit_o.valid
  PIN complete_i.fault[0]
    DIRECTION INPUT ;
    USE SIGNAL ;
    PORT
      LAYER Metal2 ;
        RECT  720.28 0 720.68 0.4 ;
    END
  END complete_i.fault[0]
  PIN complete_i.fault[1]
    DIRECTION INPUT ;
    USE SIGNAL ;
    PORT
      LAYER Metal2 ;
        RECT  723.16 0 723.56 0.4 ;
    END
  END complete_i.fault[1]
  PIN complete_i.fault[2]
    DIRECTION INPUT ;
    USE SIGNAL ;
    PORT
      LAYER Metal2 ;
        RECT  726.04 0 726.44 0.4 ;
    END
  END complete_i.fault[2]
  PIN complete_i.fault[3]
    DIRECTION INPUT ;
    USE SIGNAL ;
    PORT
      LAYER Metal2 ;
        RECT  728.92 0 729.32 0.4 ;
    END
  END complete_i.fault[3]
  PIN complete_i.fault[4]
    DIRECTION INPUT ;
    USE SIGNAL ;
    PORT
      LAYER Metal2 ;
        RECT  731.8 0 732.2 0.4 ;
    END
  END complete_i.fault[4]
  PIN complete_i.fault[5]
    DIRECTION INPUT ;
    USE SIGNAL ;
    PORT
      LAYER Metal2 ;
        RECT  734.68 0 735.08 0.4 ;
    END
  END complete_i.fault[5]
  PIN complete_i.fault[6]
    DIRECTION INPUT ;
    USE SIGNAL ;
    PORT
      LAYER Metal2 ;
        RECT  737.56 0 737.96 0.4 ;
    END
  END complete_i.fault[6]
  PIN complete_i.fault[7]
    DIRECTION INPUT ;
    USE SIGNAL ;
    PORT
      LAYER Metal2 ;
        RECT  740.44 0 740.84 0.4 ;
    END
  END complete_i.fault[7]
  PIN complete_i.fault[8]
    DIRECTION INPUT ;
    USE SIGNAL ;
    PORT
      LAYER Metal2 ;
        RECT  743.32 0 743.72 0.4 ;
    END
  END complete_i.fault[8]
  PIN complete_i.result[0]
    DIRECTION INPUT ;
    USE SIGNAL ;
    PORT
      LAYER Metal2 ;
        RECT  721.24 0 721.64 0.4 ;
    END
  END complete_i.result[0]
  PIN complete_i.result[10]
    DIRECTION INPUT ;
    USE SIGNAL ;
    PORT
      LAYER Metal2 ;
        RECT  748.12 0 748.52 0.4 ;
    END
  END complete_i.result[10]
  PIN complete_i.result[11]
    DIRECTION INPUT ;
    USE SIGNAL ;
    PORT
      LAYER Metal2 ;
        RECT  750.04 0 750.44 0.4 ;
    END
  END complete_i.result[11]
  PIN complete_i.result[12]
    DIRECTION INPUT ;
    USE SIGNAL ;
    PORT
      LAYER Metal2 ;
        RECT  751.96 0 752.36 0.4 ;
    END
  END complete_i.result[12]
  PIN complete_i.result[13]
    DIRECTION INPUT ;
    USE SIGNAL ;
    PORT
      LAYER Metal2 ;
        RECT  753.88 0 754.28 0.4 ;
    END
  END complete_i.result[13]
  PIN complete_i.result[14]
    DIRECTION INPUT ;
    USE SIGNAL ;
    PORT
      LAYER Metal2 ;
        RECT  755.8 0 756.2 0.4 ;
    END
  END complete_i.result[14]
  PIN complete_i.result[15]
    DIRECTION INPUT ;
    USE SIGNAL ;
    PORT
      LAYER Metal2 ;
        RECT  757.72 0 758.12 0.4 ;
    END
  END complete_i.result[15]
  PIN complete_i.result[16]
    DIRECTION INPUT ;
    USE SIGNAL ;
    PORT
      LAYER Metal2 ;
        RECT  759.64 0 760.04 0.4 ;
    END
  END complete_i.result[16]
  PIN complete_i.result[17]
    DIRECTION INPUT ;
    USE SIGNAL ;
    PORT
      LAYER Metal2 ;
        RECT  761.56 0 761.96 0.4 ;
    END
  END complete_i.result[17]
  PIN complete_i.result[18]
    DIRECTION INPUT ;
    USE SIGNAL ;
    PORT
      LAYER Metal2 ;
        RECT  763.48 0 763.88 0.4 ;
    END
  END complete_i.result[18]
  PIN complete_i.result[19]
    DIRECTION INPUT ;
    USE SIGNAL ;
    PORT
      LAYER Metal2 ;
        RECT  765.4 0 765.8 0.4 ;
    END
  END complete_i.result[19]
  PIN complete_i.result[1]
    DIRECTION INPUT ;
    USE SIGNAL ;
    PORT
      LAYER Metal2 ;
        RECT  724.12 0 724.52 0.4 ;
    END
  END complete_i.result[1]
  PIN complete_i.result[20]
    DIRECTION INPUT ;
    USE SIGNAL ;
    PORT
      LAYER Metal2 ;
        RECT  767.32 0 767.72 0.4 ;
    END
  END complete_i.result[20]
  PIN complete_i.result[21]
    DIRECTION INPUT ;
    USE SIGNAL ;
    PORT
      LAYER Metal2 ;
        RECT  769.24 0 769.64 0.4 ;
    END
  END complete_i.result[21]
  PIN complete_i.result[22]
    DIRECTION INPUT ;
    USE SIGNAL ;
    PORT
      LAYER Metal2 ;
        RECT  771.16 0 771.56 0.4 ;
    END
  END complete_i.result[22]
  PIN complete_i.result[23]
    DIRECTION INPUT ;
    USE SIGNAL ;
    PORT
      LAYER Metal2 ;
        RECT  773.08 0 773.48 0.4 ;
    END
  END complete_i.result[23]
  PIN complete_i.result[24]
    DIRECTION INPUT ;
    USE SIGNAL ;
    PORT
      LAYER Metal2 ;
        RECT  775 0 775.4 0.4 ;
    END
  END complete_i.result[24]
  PIN complete_i.result[25]
    DIRECTION INPUT ;
    USE SIGNAL ;
    PORT
      LAYER Metal2 ;
        RECT  776.92 0 777.32 0.4 ;
    END
  END complete_i.result[25]
  PIN complete_i.result[26]
    DIRECTION INPUT ;
    USE SIGNAL ;
    PORT
      LAYER Metal2 ;
        RECT  778.84 0 779.24 0.4 ;
    END
  END complete_i.result[26]
  PIN complete_i.result[27]
    DIRECTION INPUT ;
    USE SIGNAL ;
    PORT
      LAYER Metal2 ;
        RECT  780.76 0 781.16 0.4 ;
    END
  END complete_i.result[27]
  PIN complete_i.result[28]
    DIRECTION INPUT ;
    USE SIGNAL ;
    PORT
      LAYER Metal2 ;
        RECT  782.68 0 783.08 0.4 ;
    END
  END complete_i.result[28]
  PIN complete_i.result[29]
    DIRECTION INPUT ;
    USE SIGNAL ;
    PORT
      LAYER Metal2 ;
        RECT  784.6 0 785 0.4 ;
    END
  END complete_i.result[29]
  PIN complete_i.result[2]
    DIRECTION INPUT ;
    USE SIGNAL ;
    PORT
      LAYER Metal2 ;
        RECT  727 0 727.4 0.4 ;
    END
  END complete_i.result[2]
  PIN complete_i.result[30]
    DIRECTION INPUT ;
    USE SIGNAL ;
    PORT
      LAYER Metal2 ;
        RECT  786.52 0 786.92 0.4 ;
    END
  END complete_i.result[30]
  PIN complete_i.result[31]
    DIRECTION INPUT ;
    USE SIGNAL ;
    PORT
      LAYER Metal2 ;
        RECT  788.44 0 788.84 0.4 ;
    END
  END complete_i.result[31]
  PIN complete_i.result[32]
    DIRECTION INPUT ;
    USE SIGNAL ;
    PORT
      LAYER Metal2 ;
        RECT  790.36 0 790.76 0.4 ;
    END
  END complete_i.result[32]
  PIN complete_i.result[33]
    DIRECTION INPUT ;
    USE SIGNAL ;
    PORT
      LAYER Metal2 ;
        RECT  791.32 0 791.72 0.4 ;
    END
  END complete_i.result[33]
  PIN complete_i.result[34]
    DIRECTION INPUT ;
    USE SIGNAL ;
    PORT
      LAYER Metal2 ;
        RECT  792.28 0 792.68 0.4 ;
    END
  END complete_i.result[34]
  PIN complete_i.result[35]
    DIRECTION INPUT ;
    USE SIGNAL ;
    PORT
      LAYER Metal2 ;
        RECT  793.24 0 793.64 0.4 ;
    END
  END complete_i.result[35]
  PIN complete_i.result[36]
    DIRECTION INPUT ;
    USE SIGNAL ;
    PORT
      LAYER Metal2 ;
        RECT  794.2 0 794.6 0.4 ;
    END
  END complete_i.result[36]
  PIN complete_i.result[37]
    DIRECTION INPUT ;
    USE SIGNAL ;
    PORT
      LAYER Metal2 ;
        RECT  795.16 0 795.56 0.4 ;
    END
  END complete_i.result[37]
  PIN complete_i.result[38]
    DIRECTION INPUT ;
    USE SIGNAL ;
    PORT
      LAYER Metal2 ;
        RECT  796.12 0 796.52 0.4 ;
    END
  END complete_i.result[38]
  PIN complete_i.result[39]
    DIRECTION INPUT ;
    USE SIGNAL ;
    PORT
      LAYER Metal2 ;
        RECT  797.08 0 797.48 0.4 ;
    END
  END complete_i.result[39]
  PIN complete_i.result[3]
    DIRECTION INPUT ;
    USE SIGNAL ;
    PORT
      LAYER Metal2 ;
        RECT  729.88 0 730.28 0.4 ;
    END
  END complete_i.result[3]
  PIN complete_i.result[40]
    DIRECTION INPUT ;
    USE SIGNAL ;
    PORT
      LAYER Metal2 ;
        RECT  798.04 0 798.44 0.4 ;
    END
  END complete_i.result[40]
  PIN complete_i.result[41]
    DIRECTION INPUT ;
    USE SIGNAL ;
    PORT
      LAYER Metal2 ;
        RECT  799 0 799.4 0.4 ;
    END
  END complete_i.result[41]
  PIN complete_i.result[42]
    DIRECTION INPUT ;
    USE SIGNAL ;
    PORT
      LAYER Metal2 ;
        RECT  799.96 0 800.36 0.4 ;
    END
  END complete_i.result[42]
  PIN complete_i.result[43]
    DIRECTION INPUT ;
    USE SIGNAL ;
    PORT
      LAYER Metal2 ;
        RECT  800.92 0 801.32 0.4 ;
    END
  END complete_i.result[43]
  PIN complete_i.result[44]
    DIRECTION INPUT ;
    USE SIGNAL ;
    PORT
      LAYER Metal2 ;
        RECT  801.88 0 802.28 0.4 ;
    END
  END complete_i.result[44]
  PIN complete_i.result[45]
    DIRECTION INPUT ;
    USE SIGNAL ;
    PORT
      LAYER Metal2 ;
        RECT  802.84 0 803.24 0.4 ;
    END
  END complete_i.result[45]
  PIN complete_i.result[46]
    DIRECTION INPUT ;
    USE SIGNAL ;
    PORT
      LAYER Metal2 ;
        RECT  803.8 0 804.2 0.4 ;
    END
  END complete_i.result[46]
  PIN complete_i.result[47]
    DIRECTION INPUT ;
    USE SIGNAL ;
    PORT
      LAYER Metal2 ;
        RECT  804.76 0 805.16 0.4 ;
    END
  END complete_i.result[47]
  PIN complete_i.result[48]
    DIRECTION INPUT ;
    USE SIGNAL ;
    PORT
      LAYER Metal2 ;
        RECT  805.72 0 806.12 0.4 ;
    END
  END complete_i.result[48]
  PIN complete_i.result[49]
    DIRECTION INPUT ;
    USE SIGNAL ;
    PORT
      LAYER Metal2 ;
        RECT  806.68 0 807.08 0.4 ;
    END
  END complete_i.result[49]
  PIN complete_i.result[4]
    DIRECTION INPUT ;
    USE SIGNAL ;
    PORT
      LAYER Metal2 ;
        RECT  732.76 0 733.16 0.4 ;
    END
  END complete_i.result[4]
  PIN complete_i.result[50]
    DIRECTION INPUT ;
    USE SIGNAL ;
    PORT
      LAYER Metal2 ;
        RECT  807.64 0 808.04 0.4 ;
    END
  END complete_i.result[50]
  PIN complete_i.result[51]
    DIRECTION INPUT ;
    USE SIGNAL ;
    PORT
      LAYER Metal2 ;
        RECT  808.6 0 809 0.4 ;
    END
  END complete_i.result[51]
  PIN complete_i.result[52]
    DIRECTION INPUT ;
    USE SIGNAL ;
    PORT
      LAYER Metal2 ;
        RECT  809.56 0 809.96 0.4 ;
    END
  END complete_i.result[52]
  PIN complete_i.result[53]
    DIRECTION INPUT ;
    USE SIGNAL ;
    PORT
      LAYER Metal2 ;
        RECT  810.52 0 810.92 0.4 ;
    END
  END complete_i.result[53]
  PIN complete_i.result[54]
    DIRECTION INPUT ;
    USE SIGNAL ;
    PORT
      LAYER Metal2 ;
        RECT  811.48 0 811.88 0.4 ;
    END
  END complete_i.result[54]
  PIN complete_i.result[55]
    DIRECTION INPUT ;
    USE SIGNAL ;
    PORT
      LAYER Metal2 ;
        RECT  812.44 0 812.84 0.4 ;
    END
  END complete_i.result[55]
  PIN complete_i.result[56]
    DIRECTION INPUT ;
    USE SIGNAL ;
    PORT
      LAYER Metal2 ;
        RECT  813.4 0 813.8 0.4 ;
    END
  END complete_i.result[56]
  PIN complete_i.result[57]
    DIRECTION INPUT ;
    USE SIGNAL ;
    PORT
      LAYER Metal2 ;
        RECT  814.36 0 814.76 0.4 ;
    END
  END complete_i.result[57]
  PIN complete_i.result[58]
    DIRECTION INPUT ;
    USE SIGNAL ;
    PORT
      LAYER Metal2 ;
        RECT  815.32 0 815.72 0.4 ;
    END
  END complete_i.result[58]
  PIN complete_i.result[59]
    DIRECTION INPUT ;
    USE SIGNAL ;
    PORT
      LAYER Metal2 ;
        RECT  816.28 0 816.68 0.4 ;
    END
  END complete_i.result[59]
  PIN complete_i.result[5]
    DIRECTION INPUT ;
    USE SIGNAL ;
    PORT
      LAYER Metal2 ;
        RECT  735.64 0 736.04 0.4 ;
    END
  END complete_i.result[5]
  PIN complete_i.result[60]
    DIRECTION INPUT ;
    USE SIGNAL ;
    PORT
      LAYER Metal2 ;
        RECT  817.24 0 817.64 0.4 ;
    END
  END complete_i.result[60]
  PIN complete_i.result[61]
    DIRECTION INPUT ;
    USE SIGNAL ;
    PORT
      LAYER Metal2 ;
        RECT  818.2 0 818.6 0.4 ;
    END
  END complete_i.result[61]
  PIN complete_i.result[62]
    DIRECTION INPUT ;
    USE SIGNAL ;
    PORT
      LAYER Metal2 ;
        RECT  819.16 0 819.56 0.4 ;
    END
  END complete_i.result[62]
  PIN complete_i.result[63]
    DIRECTION INPUT ;
    USE SIGNAL ;
    PORT
      LAYER Metal2 ;
        RECT  820.12 0 820.52 0.4 ;
    END
  END complete_i.result[63]
  PIN complete_i.result[6]
    DIRECTION INPUT ;
    USE SIGNAL ;
    PORT
      LAYER Metal2 ;
        RECT  738.52 0 738.92 0.4 ;
    END
  END complete_i.result[6]
  PIN complete_i.result[7]
    DIRECTION INPUT ;
    USE SIGNAL ;
    PORT
      LAYER Metal2 ;
        RECT  741.4 0 741.8 0.4 ;
    END
  END complete_i.result[7]
  PIN complete_i.result[8]
    DIRECTION INPUT ;
    USE SIGNAL ;
    PORT
      LAYER Metal2 ;
        RECT  744.28 0 744.68 0.4 ;
    END
  END complete_i.result[8]
  PIN complete_i.result[9]
    DIRECTION INPUT ;
    USE SIGNAL ;
    PORT
      LAYER Metal2 ;
        RECT  746.2 0 746.6 0.4 ;
    END
  END complete_i.result[9]
  PIN complete_i.result_valid
    DIRECTION INPUT ;
    USE SIGNAL ;
    PORT
      LAYER Metal2 ;
        RECT  717.4 0 717.8 0.4 ;
    END
  END complete_i.result_valid
  PIN complete_i.taken
    DIRECTION INPUT ;
    USE SIGNAL ;
    PORT
      LAYER Metal2 ;
        RECT  718.36 0 718.76 0.4 ;
    END
  END complete_i.taken
  PIN complete_i.target[0]
    DIRECTION INPUT ;
    USE SIGNAL ;
    PORT
      LAYER Metal2 ;
        RECT  722.2 0 722.6 0.4 ;
    END
  END complete_i.target[0]
  PIN complete_i.target[10]
    DIRECTION INPUT ;
    USE SIGNAL ;
    PORT
      LAYER Metal2 ;
        RECT  749.08 0 749.48 0.4 ;
    END
  END complete_i.target[10]
  PIN complete_i.target[11]
    DIRECTION INPUT ;
    USE SIGNAL ;
    PORT
      LAYER Metal2 ;
        RECT  751 0 751.4 0.4 ;
    END
  END complete_i.target[11]
  PIN complete_i.target[12]
    DIRECTION INPUT ;
    USE SIGNAL ;
    PORT
      LAYER Metal2 ;
        RECT  752.92 0 753.32 0.4 ;
    END
  END complete_i.target[12]
  PIN complete_i.target[13]
    DIRECTION INPUT ;
    USE SIGNAL ;
    PORT
      LAYER Metal2 ;
        RECT  754.84 0 755.24 0.4 ;
    END
  END complete_i.target[13]
  PIN complete_i.target[14]
    DIRECTION INPUT ;
    USE SIGNAL ;
    PORT
      LAYER Metal2 ;
        RECT  756.76 0 757.16 0.4 ;
    END
  END complete_i.target[14]
  PIN complete_i.target[15]
    DIRECTION INPUT ;
    USE SIGNAL ;
    PORT
      LAYER Metal2 ;
        RECT  758.68 0 759.08 0.4 ;
    END
  END complete_i.target[15]
  PIN complete_i.target[16]
    DIRECTION INPUT ;
    USE SIGNAL ;
    PORT
      LAYER Metal2 ;
        RECT  760.6 0 761 0.4 ;
    END
  END complete_i.target[16]
  PIN complete_i.target[17]
    DIRECTION INPUT ;
    USE SIGNAL ;
    PORT
      LAYER Metal2 ;
        RECT  762.52 0 762.92 0.4 ;
    END
  END complete_i.target[17]
  PIN complete_i.target[18]
    DIRECTION INPUT ;
    USE SIGNAL ;
    PORT
      LAYER Metal2 ;
        RECT  764.44 0 764.84 0.4 ;
    END
  END complete_i.target[18]
  PIN complete_i.target[19]
    DIRECTION INPUT ;
    USE SIGNAL ;
    PORT
      LAYER Metal2 ;
        RECT  766.36 0 766.76 0.4 ;
    END
  END complete_i.target[19]
  PIN complete_i.target[1]
    DIRECTION INPUT ;
    USE SIGNAL ;
    PORT
      LAYER Metal2 ;
        RECT  725.08 0 725.48 0.4 ;
    END
  END complete_i.target[1]
  PIN complete_i.target[20]
    DIRECTION INPUT ;
    USE SIGNAL ;
    PORT
      LAYER Metal2 ;
        RECT  768.28 0 768.68 0.4 ;
    END
  END complete_i.target[20]
  PIN complete_i.target[21]
    DIRECTION INPUT ;
    USE SIGNAL ;
    PORT
      LAYER Metal2 ;
        RECT  770.2 0 770.6 0.4 ;
    END
  END complete_i.target[21]
  PIN complete_i.target[22]
    DIRECTION INPUT ;
    USE SIGNAL ;
    PORT
      LAYER Metal2 ;
        RECT  772.12 0 772.52 0.4 ;
    END
  END complete_i.target[22]
  PIN complete_i.target[23]
    DIRECTION INPUT ;
    USE SIGNAL ;
    PORT
      LAYER Metal2 ;
        RECT  774.04 0 774.44 0.4 ;
    END
  END complete_i.target[23]
  PIN complete_i.target[24]
    DIRECTION INPUT ;
    USE SIGNAL ;
    PORT
      LAYER Metal2 ;
        RECT  775.96 0 776.36 0.4 ;
    END
  END complete_i.target[24]
  PIN complete_i.target[25]
    DIRECTION INPUT ;
    USE SIGNAL ;
    PORT
      LAYER Metal2 ;
        RECT  777.88 0 778.28 0.4 ;
    END
  END complete_i.target[25]
  PIN complete_i.target[26]
    DIRECTION INPUT ;
    USE SIGNAL ;
    PORT
      LAYER Metal2 ;
        RECT  779.8 0 780.2 0.4 ;
    END
  END complete_i.target[26]
  PIN complete_i.target[27]
    DIRECTION INPUT ;
    USE SIGNAL ;
    PORT
      LAYER Metal2 ;
        RECT  781.72 0 782.12 0.4 ;
    END
  END complete_i.target[27]
  PIN complete_i.target[28]
    DIRECTION INPUT ;
    USE SIGNAL ;
    PORT
      LAYER Metal2 ;
        RECT  783.64 0 784.04 0.4 ;
    END
  END complete_i.target[28]
  PIN complete_i.target[29]
    DIRECTION INPUT ;
    USE SIGNAL ;
    PORT
      LAYER Metal2 ;
        RECT  785.56 0 785.96 0.4 ;
    END
  END complete_i.target[29]
  PIN complete_i.target[2]
    DIRECTION INPUT ;
    USE SIGNAL ;
    PORT
      LAYER Metal2 ;
        RECT  727.96 0 728.36 0.4 ;
    END
  END complete_i.target[2]
  PIN complete_i.target[30]
    DIRECTION INPUT ;
    USE SIGNAL ;
    PORT
      LAYER Metal2 ;
        RECT  787.48 0 787.88 0.4 ;
    END
  END complete_i.target[30]
  PIN complete_i.target[31]
    DIRECTION INPUT ;
    USE SIGNAL ;
    PORT
      LAYER Metal2 ;
        RECT  789.4 0 789.8 0.4 ;
    END
  END complete_i.target[31]
  PIN complete_i.target[3]
    DIRECTION INPUT ;
    USE SIGNAL ;
    PORT
      LAYER Metal2 ;
        RECT  730.84 0 731.24 0.4 ;
    END
  END complete_i.target[3]
  PIN complete_i.target[4]
    DIRECTION INPUT ;
    USE SIGNAL ;
    PORT
      LAYER Metal2 ;
        RECT  733.72 0 734.12 0.4 ;
    END
  END complete_i.target[4]
  PIN complete_i.target[5]
    DIRECTION INPUT ;
    USE SIGNAL ;
    PORT
      LAYER Metal2 ;
        RECT  736.6 0 737 0.4 ;
    END
  END complete_i.target[5]
  PIN complete_i.target[6]
    DIRECTION INPUT ;
    USE SIGNAL ;
    PORT
      LAYER Metal2 ;
        RECT  739.48 0 739.88 0.4 ;
    END
  END complete_i.target[6]
  PIN complete_i.target[7]
    DIRECTION INPUT ;
    USE SIGNAL ;
    PORT
      LAYER Metal2 ;
        RECT  742.36 0 742.76 0.4 ;
    END
  END complete_i.target[7]
  PIN complete_i.target[8]
    DIRECTION INPUT ;
    USE SIGNAL ;
    PORT
      LAYER Metal2 ;
        RECT  745.24 0 745.64 0.4 ;
    END
  END complete_i.target[8]
  PIN complete_i.target[9]
    DIRECTION INPUT ;
    USE SIGNAL ;
    PORT
      LAYER Metal2 ;
        RECT  747.16 0 747.56 0.4 ;
    END
  END complete_i.target[9]
  PIN complete_i.valid
    DIRECTION INPUT ;
    USE SIGNAL ;
    PORT
      LAYER Metal2 ;
        RECT  719.32 0 719.72 0.4 ;
    END
  END complete_i.valid
  PIN decode_slot_i.canon[0]
    DIRECTION INPUT ;
    USE SIGNAL ;
    PORT
      LAYER Metal3 ;
        RECT  0 48.94 0.4 49.34 ;
    END
  END decode_slot_i.canon[0]
  PIN decode_slot_i.canon[10]
    DIRECTION INPUT ;
    USE SIGNAL ;
    PORT
      LAYER Metal3 ;
        RECT  0 351.34 0.4 351.74 ;
    END
  END decode_slot_i.canon[10]
  PIN decode_slot_i.canon[11]
    DIRECTION INPUT ;
    USE SIGNAL ;
    PORT
      LAYER Metal3 ;
        RECT  0 381.58 0.4 381.98 ;
    END
  END decode_slot_i.canon[11]
  PIN decode_slot_i.canon[12]
    DIRECTION INPUT ;
    USE SIGNAL ;
    PORT
      LAYER Metal3 ;
        RECT  0 411.82 0.4 412.22 ;
    END
  END decode_slot_i.canon[12]
  PIN decode_slot_i.canon[13]
    DIRECTION INPUT ;
    USE SIGNAL ;
    PORT
      LAYER Metal3 ;
        RECT  0 442.06 0.4 442.46 ;
    END
  END decode_slot_i.canon[13]
  PIN decode_slot_i.canon[14]
    DIRECTION INPUT ;
    USE SIGNAL ;
    PORT
      LAYER Metal3 ;
        RECT  0 472.3 0.4 472.7 ;
    END
  END decode_slot_i.canon[14]
  PIN decode_slot_i.canon[15]
    DIRECTION INPUT ;
    USE SIGNAL ;
    PORT
      LAYER Metal3 ;
        RECT  0 502.54 0.4 502.94 ;
    END
  END decode_slot_i.canon[15]
  PIN decode_slot_i.canon[16]
    DIRECTION INPUT ;
    USE SIGNAL ;
    PORT
      LAYER Metal3 ;
        RECT  0 532.78 0.4 533.18 ;
    END
  END decode_slot_i.canon[16]
  PIN decode_slot_i.canon[17]
    DIRECTION INPUT ;
    USE SIGNAL ;
    PORT
      LAYER Metal3 ;
        RECT  0 563.02 0.4 563.42 ;
    END
  END decode_slot_i.canon[17]
  PIN decode_slot_i.canon[18]
    DIRECTION INPUT ;
    USE SIGNAL ;
    PORT
      LAYER Metal3 ;
        RECT  0 593.26 0.4 593.66 ;
    END
  END decode_slot_i.canon[18]
  PIN decode_slot_i.canon[19]
    DIRECTION INPUT ;
    USE SIGNAL ;
    PORT
      LAYER Metal3 ;
        RECT  0 623.5 0.4 623.9 ;
    END
  END decode_slot_i.canon[19]
  PIN decode_slot_i.canon[1]
    DIRECTION INPUT ;
    USE SIGNAL ;
    PORT
      LAYER Metal3 ;
        RECT  0 79.18 0.4 79.58 ;
    END
  END decode_slot_i.canon[1]
  PIN decode_slot_i.canon[20]
    DIRECTION INPUT ;
    USE SIGNAL ;
    PORT
      LAYER Metal3 ;
        RECT  0 653.74 0.4 654.14 ;
    END
  END decode_slot_i.canon[20]
  PIN decode_slot_i.canon[21]
    DIRECTION INPUT ;
    USE SIGNAL ;
    PORT
      LAYER Metal3 ;
        RECT  0 683.98 0.4 684.38 ;
    END
  END decode_slot_i.canon[21]
  PIN decode_slot_i.canon[22]
    DIRECTION INPUT ;
    USE SIGNAL ;
    PORT
      LAYER Metal3 ;
        RECT  0 714.22 0.4 714.62 ;
    END
  END decode_slot_i.canon[22]
  PIN decode_slot_i.canon[23]
    DIRECTION INPUT ;
    USE SIGNAL ;
    PORT
      LAYER Metal3 ;
        RECT  0 744.46 0.4 744.86 ;
    END
  END decode_slot_i.canon[23]
  PIN decode_slot_i.canon[24]
    DIRECTION INPUT ;
    USE SIGNAL ;
    PORT
      LAYER Metal3 ;
        RECT  0 774.7 0.4 775.1 ;
    END
  END decode_slot_i.canon[24]
  PIN decode_slot_i.canon[25]
    DIRECTION INPUT ;
    USE SIGNAL ;
    PORT
      LAYER Metal3 ;
        RECT  0 804.94 0.4 805.34 ;
    END
  END decode_slot_i.canon[25]
  PIN decode_slot_i.canon[26]
    DIRECTION INPUT ;
    USE SIGNAL ;
    PORT
      LAYER Metal3 ;
        RECT  0 835.18 0.4 835.58 ;
    END
  END decode_slot_i.canon[26]
  PIN decode_slot_i.canon[27]
    DIRECTION INPUT ;
    USE SIGNAL ;
    PORT
      LAYER Metal3 ;
        RECT  0 865.42 0.4 865.82 ;
    END
  END decode_slot_i.canon[27]
  PIN decode_slot_i.canon[28]
    DIRECTION INPUT ;
    USE SIGNAL ;
    PORT
      LAYER Metal3 ;
        RECT  0 895.66 0.4 896.06 ;
    END
  END decode_slot_i.canon[28]
  PIN decode_slot_i.canon[29]
    DIRECTION INPUT ;
    USE SIGNAL ;
    PORT
      LAYER Metal3 ;
        RECT  0 925.9 0.4 926.3 ;
    END
  END decode_slot_i.canon[29]
  PIN decode_slot_i.canon[2]
    DIRECTION INPUT ;
    USE SIGNAL ;
    PORT
      LAYER Metal3 ;
        RECT  0 109.42 0.4 109.82 ;
    END
  END decode_slot_i.canon[2]
  PIN decode_slot_i.canon[30]
    DIRECTION INPUT ;
    USE SIGNAL ;
    PORT
      LAYER Metal3 ;
        RECT  0 956.14 0.4 956.54 ;
    END
  END decode_slot_i.canon[30]
  PIN decode_slot_i.canon[31]
    DIRECTION INPUT ;
    USE SIGNAL ;
    PORT
      LAYER Metal3 ;
        RECT  0 986.38 0.4 986.78 ;
    END
  END decode_slot_i.canon[31]
  PIN decode_slot_i.canon[32]
    DIRECTION INPUT ;
    USE SIGNAL ;
    PORT
      LAYER Metal3 ;
        RECT  0 1016.62 0.4 1017.02 ;
    END
  END decode_slot_i.canon[32]
  PIN decode_slot_i.canon[33]
    DIRECTION INPUT ;
    USE SIGNAL ;
    PORT
      LAYER Metal3 ;
        RECT  0 1036.78 0.4 1037.18 ;
    END
  END decode_slot_i.canon[33]
  PIN decode_slot_i.canon[34]
    DIRECTION INPUT ;
    USE SIGNAL ;
    PORT
      LAYER Metal3 ;
        RECT  0 1056.94 0.4 1057.34 ;
    END
  END decode_slot_i.canon[34]
  PIN decode_slot_i.canon[35]
    DIRECTION INPUT ;
    USE SIGNAL ;
    PORT
      LAYER Metal3 ;
        RECT  0 1077.1 0.4 1077.5 ;
    END
  END decode_slot_i.canon[35]
  PIN decode_slot_i.canon[36]
    DIRECTION INPUT ;
    USE SIGNAL ;
    PORT
      LAYER Metal3 ;
        RECT  0 1097.26 0.4 1097.66 ;
    END
  END decode_slot_i.canon[36]
  PIN decode_slot_i.canon[37]
    DIRECTION INPUT ;
    USE SIGNAL ;
    PORT
      LAYER Metal3 ;
        RECT  0 1117.42 0.4 1117.82 ;
    END
  END decode_slot_i.canon[37]
  PIN decode_slot_i.canon[38]
    DIRECTION INPUT ;
    USE SIGNAL ;
    PORT
      LAYER Metal3 ;
        RECT  0 1137.58 0.4 1137.98 ;
    END
  END decode_slot_i.canon[38]
  PIN decode_slot_i.canon[39]
    DIRECTION INPUT ;
    USE SIGNAL ;
    PORT
      LAYER Metal3 ;
        RECT  0 1157.74 0.4 1158.14 ;
    END
  END decode_slot_i.canon[39]
  PIN decode_slot_i.canon[3]
    DIRECTION INPUT ;
    USE SIGNAL ;
    PORT
      LAYER Metal3 ;
        RECT  0 139.66 0.4 140.06 ;
    END
  END decode_slot_i.canon[3]
  PIN decode_slot_i.canon[40]
    DIRECTION INPUT ;
    USE SIGNAL ;
    PORT
      LAYER Metal3 ;
        RECT  0 1177.9 0.4 1178.3 ;
    END
  END decode_slot_i.canon[40]
  PIN decode_slot_i.canon[41]
    DIRECTION INPUT ;
    USE SIGNAL ;
    PORT
      LAYER Metal3 ;
        RECT  0 1198.06 0.4 1198.46 ;
    END
  END decode_slot_i.canon[41]
  PIN decode_slot_i.canon[42]
    DIRECTION INPUT ;
    USE SIGNAL ;
    PORT
      LAYER Metal3 ;
        RECT  0 1218.22 0.4 1218.62 ;
    END
  END decode_slot_i.canon[42]
  PIN decode_slot_i.canon[43]
    DIRECTION INPUT ;
    USE SIGNAL ;
    PORT
      LAYER Metal3 ;
        RECT  0 1238.38 0.4 1238.78 ;
    END
  END decode_slot_i.canon[43]
  PIN decode_slot_i.canon[44]
    DIRECTION INPUT ;
    USE SIGNAL ;
    PORT
      LAYER Metal3 ;
        RECT  0 1258.54 0.4 1258.94 ;
    END
  END decode_slot_i.canon[44]
  PIN decode_slot_i.canon[45]
    DIRECTION INPUT ;
    USE SIGNAL ;
    PORT
      LAYER Metal3 ;
        RECT  0 1278.7 0.4 1279.1 ;
    END
  END decode_slot_i.canon[45]
  PIN decode_slot_i.canon[46]
    DIRECTION INPUT ;
    USE SIGNAL ;
    PORT
      LAYER Metal3 ;
        RECT  0 1298.86 0.4 1299.26 ;
    END
  END decode_slot_i.canon[46]
  PIN decode_slot_i.canon[47]
    DIRECTION INPUT ;
    USE SIGNAL ;
    PORT
      LAYER Metal3 ;
        RECT  0 1319.02 0.4 1319.42 ;
    END
  END decode_slot_i.canon[47]
  PIN decode_slot_i.canon[48]
    DIRECTION INPUT ;
    USE SIGNAL ;
    PORT
      LAYER Metal3 ;
        RECT  0 1339.18 0.4 1339.58 ;
    END
  END decode_slot_i.canon[48]
  PIN decode_slot_i.canon[49]
    DIRECTION INPUT ;
    USE SIGNAL ;
    PORT
      LAYER Metal3 ;
        RECT  0 1359.34 0.4 1359.74 ;
    END
  END decode_slot_i.canon[49]
  PIN decode_slot_i.canon[4]
    DIRECTION INPUT ;
    USE SIGNAL ;
    PORT
      LAYER Metal3 ;
        RECT  0 169.9 0.4 170.3 ;
    END
  END decode_slot_i.canon[4]
  PIN decode_slot_i.canon[50]
    DIRECTION INPUT ;
    USE SIGNAL ;
    PORT
      LAYER Metal3 ;
        RECT  0 1379.5 0.4 1379.9 ;
    END
  END decode_slot_i.canon[50]
  PIN decode_slot_i.canon[51]
    DIRECTION INPUT ;
    USE SIGNAL ;
    PORT
      LAYER Metal3 ;
        RECT  0 1399.66 0.4 1400.06 ;
    END
  END decode_slot_i.canon[51]
  PIN decode_slot_i.canon[52]
    DIRECTION INPUT ;
    USE SIGNAL ;
    PORT
      LAYER Metal3 ;
        RECT  0 1419.82 0.4 1420.22 ;
    END
  END decode_slot_i.canon[52]
  PIN decode_slot_i.canon[53]
    DIRECTION INPUT ;
    USE SIGNAL ;
    PORT
      LAYER Metal3 ;
        RECT  0 1439.98 0.4 1440.38 ;
    END
  END decode_slot_i.canon[53]
  PIN decode_slot_i.canon[54]
    DIRECTION INPUT ;
    USE SIGNAL ;
    PORT
      LAYER Metal3 ;
        RECT  0 1460.14 0.4 1460.54 ;
    END
  END decode_slot_i.canon[54]
  PIN decode_slot_i.canon[55]
    DIRECTION INPUT ;
    USE SIGNAL ;
    PORT
      LAYER Metal3 ;
        RECT  0 1470.22 0.4 1470.62 ;
    END
  END decode_slot_i.canon[55]
  PIN decode_slot_i.canon[5]
    DIRECTION INPUT ;
    USE SIGNAL ;
    PORT
      LAYER Metal3 ;
        RECT  0 200.14 0.4 200.54 ;
    END
  END decode_slot_i.canon[5]
  PIN decode_slot_i.canon[6]
    DIRECTION INPUT ;
    USE SIGNAL ;
    PORT
      LAYER Metal3 ;
        RECT  0 230.38 0.4 230.78 ;
    END
  END decode_slot_i.canon[6]
  PIN decode_slot_i.canon[7]
    DIRECTION INPUT ;
    USE SIGNAL ;
    PORT
      LAYER Metal3 ;
        RECT  0 260.62 0.4 261.02 ;
    END
  END decode_slot_i.canon[7]
  PIN decode_slot_i.canon[8]
    DIRECTION INPUT ;
    USE SIGNAL ;
    PORT
      LAYER Metal3 ;
        RECT  0 290.86 0.4 291.26 ;
    END
  END decode_slot_i.canon[8]
  PIN decode_slot_i.canon[9]
    DIRECTION INPUT ;
    USE SIGNAL ;
    PORT
      LAYER Metal3 ;
        RECT  0 321.1 0.4 321.5 ;
    END
  END decode_slot_i.canon[9]
  PIN decode_slot_i.pc[0]
    DIRECTION INPUT ;
    USE SIGNAL ;
    PORT
      LAYER Metal3 ;
        RECT  0 59.02 0.4 59.42 ;
    END
  END decode_slot_i.pc[0]
  PIN decode_slot_i.pc[10]
    DIRECTION INPUT ;
    USE SIGNAL ;
    PORT
      LAYER Metal3 ;
        RECT  0 361.42 0.4 361.82 ;
    END
  END decode_slot_i.pc[10]
  PIN decode_slot_i.pc[11]
    DIRECTION INPUT ;
    USE SIGNAL ;
    PORT
      LAYER Metal3 ;
        RECT  0 391.66 0.4 392.06 ;
    END
  END decode_slot_i.pc[11]
  PIN decode_slot_i.pc[12]
    DIRECTION INPUT ;
    USE SIGNAL ;
    PORT
      LAYER Metal3 ;
        RECT  0 421.9 0.4 422.3 ;
    END
  END decode_slot_i.pc[12]
  PIN decode_slot_i.pc[13]
    DIRECTION INPUT ;
    USE SIGNAL ;
    PORT
      LAYER Metal3 ;
        RECT  0 452.14 0.4 452.54 ;
    END
  END decode_slot_i.pc[13]
  PIN decode_slot_i.pc[14]
    DIRECTION INPUT ;
    USE SIGNAL ;
    PORT
      LAYER Metal3 ;
        RECT  0 482.38 0.4 482.78 ;
    END
  END decode_slot_i.pc[14]
  PIN decode_slot_i.pc[15]
    DIRECTION INPUT ;
    USE SIGNAL ;
    PORT
      LAYER Metal3 ;
        RECT  0 512.62 0.4 513.02 ;
    END
  END decode_slot_i.pc[15]
  PIN decode_slot_i.pc[16]
    DIRECTION INPUT ;
    USE SIGNAL ;
    PORT
      LAYER Metal3 ;
        RECT  0 542.86 0.4 543.26 ;
    END
  END decode_slot_i.pc[16]
  PIN decode_slot_i.pc[17]
    DIRECTION INPUT ;
    USE SIGNAL ;
    PORT
      LAYER Metal3 ;
        RECT  0 573.1 0.4 573.5 ;
    END
  END decode_slot_i.pc[17]
  PIN decode_slot_i.pc[18]
    DIRECTION INPUT ;
    USE SIGNAL ;
    PORT
      LAYER Metal3 ;
        RECT  0 603.34 0.4 603.74 ;
    END
  END decode_slot_i.pc[18]
  PIN decode_slot_i.pc[19]
    DIRECTION INPUT ;
    USE SIGNAL ;
    PORT
      LAYER Metal3 ;
        RECT  0 633.58 0.4 633.98 ;
    END
  END decode_slot_i.pc[19]
  PIN decode_slot_i.pc[1]
    DIRECTION INPUT ;
    USE SIGNAL ;
    PORT
      LAYER Metal3 ;
        RECT  0 89.26 0.4 89.66 ;
    END
  END decode_slot_i.pc[1]
  PIN decode_slot_i.pc[20]
    DIRECTION INPUT ;
    USE SIGNAL ;
    PORT
      LAYER Metal3 ;
        RECT  0 663.82 0.4 664.22 ;
    END
  END decode_slot_i.pc[20]
  PIN decode_slot_i.pc[21]
    DIRECTION INPUT ;
    USE SIGNAL ;
    PORT
      LAYER Metal3 ;
        RECT  0 694.06 0.4 694.46 ;
    END
  END decode_slot_i.pc[21]
  PIN decode_slot_i.pc[22]
    DIRECTION INPUT ;
    USE SIGNAL ;
    PORT
      LAYER Metal3 ;
        RECT  0 724.3 0.4 724.7 ;
    END
  END decode_slot_i.pc[22]
  PIN decode_slot_i.pc[23]
    DIRECTION INPUT ;
    USE SIGNAL ;
    PORT
      LAYER Metal3 ;
        RECT  0 754.54 0.4 754.94 ;
    END
  END decode_slot_i.pc[23]
  PIN decode_slot_i.pc[24]
    DIRECTION INPUT ;
    USE SIGNAL ;
    PORT
      LAYER Metal3 ;
        RECT  0 784.78 0.4 785.18 ;
    END
  END decode_slot_i.pc[24]
  PIN decode_slot_i.pc[25]
    DIRECTION INPUT ;
    USE SIGNAL ;
    PORT
      LAYER Metal3 ;
        RECT  0 815.02 0.4 815.42 ;
    END
  END decode_slot_i.pc[25]
  PIN decode_slot_i.pc[26]
    DIRECTION INPUT ;
    USE SIGNAL ;
    PORT
      LAYER Metal3 ;
        RECT  0 845.26 0.4 845.66 ;
    END
  END decode_slot_i.pc[26]
  PIN decode_slot_i.pc[27]
    DIRECTION INPUT ;
    USE SIGNAL ;
    PORT
      LAYER Metal3 ;
        RECT  0 875.5 0.4 875.9 ;
    END
  END decode_slot_i.pc[27]
  PIN decode_slot_i.pc[28]
    DIRECTION INPUT ;
    USE SIGNAL ;
    PORT
      LAYER Metal3 ;
        RECT  0 905.74 0.4 906.14 ;
    END
  END decode_slot_i.pc[28]
  PIN decode_slot_i.pc[29]
    DIRECTION INPUT ;
    USE SIGNAL ;
    PORT
      LAYER Metal3 ;
        RECT  0 935.98 0.4 936.38 ;
    END
  END decode_slot_i.pc[29]
  PIN decode_slot_i.pc[2]
    DIRECTION INPUT ;
    USE SIGNAL ;
    PORT
      LAYER Metal3 ;
        RECT  0 119.5 0.4 119.9 ;
    END
  END decode_slot_i.pc[2]
  PIN decode_slot_i.pc[30]
    DIRECTION INPUT ;
    USE SIGNAL ;
    PORT
      LAYER Metal3 ;
        RECT  0 966.22 0.4 966.62 ;
    END
  END decode_slot_i.pc[30]
  PIN decode_slot_i.pc[31]
    DIRECTION INPUT ;
    USE SIGNAL ;
    PORT
      LAYER Metal3 ;
        RECT  0 996.46 0.4 996.86 ;
    END
  END decode_slot_i.pc[31]
  PIN decode_slot_i.pc[3]
    DIRECTION INPUT ;
    USE SIGNAL ;
    PORT
      LAYER Metal3 ;
        RECT  0 149.74 0.4 150.14 ;
    END
  END decode_slot_i.pc[3]
  PIN decode_slot_i.pc[4]
    DIRECTION INPUT ;
    USE SIGNAL ;
    PORT
      LAYER Metal3 ;
        RECT  0 179.98 0.4 180.38 ;
    END
  END decode_slot_i.pc[4]
  PIN decode_slot_i.pc[5]
    DIRECTION INPUT ;
    USE SIGNAL ;
    PORT
      LAYER Metal3 ;
        RECT  0 210.22 0.4 210.62 ;
    END
  END decode_slot_i.pc[5]
  PIN decode_slot_i.pc[6]
    DIRECTION INPUT ;
    USE SIGNAL ;
    PORT
      LAYER Metal3 ;
        RECT  0 240.46 0.4 240.86 ;
    END
  END decode_slot_i.pc[6]
  PIN decode_slot_i.pc[7]
    DIRECTION INPUT ;
    USE SIGNAL ;
    PORT
      LAYER Metal3 ;
        RECT  0 270.7 0.4 271.1 ;
    END
  END decode_slot_i.pc[7]
  PIN decode_slot_i.pc[8]
    DIRECTION INPUT ;
    USE SIGNAL ;
    PORT
      LAYER Metal3 ;
        RECT  0 300.94 0.4 301.34 ;
    END
  END decode_slot_i.pc[8]
  PIN decode_slot_i.pc[9]
    DIRECTION INPUT ;
    USE SIGNAL ;
    PORT
      LAYER Metal3 ;
        RECT  0 331.18 0.4 331.58 ;
    END
  END decode_slot_i.pc[9]
  PIN decode_slot_i.pred[0]
    DIRECTION INPUT ;
    USE SIGNAL ;
    PORT
      LAYER Metal3 ;
        RECT  0 69.1 0.4 69.5 ;
    END
  END decode_slot_i.pred[0]
  PIN decode_slot_i.pred[10]
    DIRECTION INPUT ;
    USE SIGNAL ;
    PORT
      LAYER Metal3 ;
        RECT  0 371.5 0.4 371.9 ;
    END
  END decode_slot_i.pred[10]
  PIN decode_slot_i.pred[11]
    DIRECTION INPUT ;
    USE SIGNAL ;
    PORT
      LAYER Metal3 ;
        RECT  0 401.74 0.4 402.14 ;
    END
  END decode_slot_i.pred[11]
  PIN decode_slot_i.pred[12]
    DIRECTION INPUT ;
    USE SIGNAL ;
    PORT
      LAYER Metal3 ;
        RECT  0 431.98 0.4 432.38 ;
    END
  END decode_slot_i.pred[12]
  PIN decode_slot_i.pred[13]
    DIRECTION INPUT ;
    USE SIGNAL ;
    PORT
      LAYER Metal3 ;
        RECT  0 462.22 0.4 462.62 ;
    END
  END decode_slot_i.pred[13]
  PIN decode_slot_i.pred[14]
    DIRECTION INPUT ;
    USE SIGNAL ;
    PORT
      LAYER Metal3 ;
        RECT  0 492.46 0.4 492.86 ;
    END
  END decode_slot_i.pred[14]
  PIN decode_slot_i.pred[15]
    DIRECTION INPUT ;
    USE SIGNAL ;
    PORT
      LAYER Metal3 ;
        RECT  0 522.7 0.4 523.1 ;
    END
  END decode_slot_i.pred[15]
  PIN decode_slot_i.pred[16]
    DIRECTION INPUT ;
    USE SIGNAL ;
    PORT
      LAYER Metal3 ;
        RECT  0 552.94 0.4 553.34 ;
    END
  END decode_slot_i.pred[16]
  PIN decode_slot_i.pred[17]
    DIRECTION INPUT ;
    USE SIGNAL ;
    PORT
      LAYER Metal3 ;
        RECT  0 583.18 0.4 583.58 ;
    END
  END decode_slot_i.pred[17]
  PIN decode_slot_i.pred[18]
    DIRECTION INPUT ;
    USE SIGNAL ;
    PORT
      LAYER Metal3 ;
        RECT  0 613.42 0.4 613.82 ;
    END
  END decode_slot_i.pred[18]
  PIN decode_slot_i.pred[19]
    DIRECTION INPUT ;
    USE SIGNAL ;
    PORT
      LAYER Metal3 ;
        RECT  0 643.66 0.4 644.06 ;
    END
  END decode_slot_i.pred[19]
  PIN decode_slot_i.pred[1]
    DIRECTION INPUT ;
    USE SIGNAL ;
    PORT
      LAYER Metal3 ;
        RECT  0 99.34 0.4 99.74 ;
    END
  END decode_slot_i.pred[1]
  PIN decode_slot_i.pred[20]
    DIRECTION INPUT ;
    USE SIGNAL ;
    PORT
      LAYER Metal3 ;
        RECT  0 673.9 0.4 674.3 ;
    END
  END decode_slot_i.pred[20]
  PIN decode_slot_i.pred[21]
    DIRECTION INPUT ;
    USE SIGNAL ;
    PORT
      LAYER Metal3 ;
        RECT  0 704.14 0.4 704.54 ;
    END
  END decode_slot_i.pred[21]
  PIN decode_slot_i.pred[22]
    DIRECTION INPUT ;
    USE SIGNAL ;
    PORT
      LAYER Metal3 ;
        RECT  0 734.38 0.4 734.78 ;
    END
  END decode_slot_i.pred[22]
  PIN decode_slot_i.pred[23]
    DIRECTION INPUT ;
    USE SIGNAL ;
    PORT
      LAYER Metal3 ;
        RECT  0 764.62 0.4 765.02 ;
    END
  END decode_slot_i.pred[23]
  PIN decode_slot_i.pred[24]
    DIRECTION INPUT ;
    USE SIGNAL ;
    PORT
      LAYER Metal3 ;
        RECT  0 794.86 0.4 795.26 ;
    END
  END decode_slot_i.pred[24]
  PIN decode_slot_i.pred[25]
    DIRECTION INPUT ;
    USE SIGNAL ;
    PORT
      LAYER Metal3 ;
        RECT  0 825.1 0.4 825.5 ;
    END
  END decode_slot_i.pred[25]
  PIN decode_slot_i.pred[26]
    DIRECTION INPUT ;
    USE SIGNAL ;
    PORT
      LAYER Metal3 ;
        RECT  0 855.34 0.4 855.74 ;
    END
  END decode_slot_i.pred[26]
  PIN decode_slot_i.pred[27]
    DIRECTION INPUT ;
    USE SIGNAL ;
    PORT
      LAYER Metal3 ;
        RECT  0 885.58 0.4 885.98 ;
    END
  END decode_slot_i.pred[27]
  PIN decode_slot_i.pred[28]
    DIRECTION INPUT ;
    USE SIGNAL ;
    PORT
      LAYER Metal3 ;
        RECT  0 915.82 0.4 916.22 ;
    END
  END decode_slot_i.pred[28]
  PIN decode_slot_i.pred[29]
    DIRECTION INPUT ;
    USE SIGNAL ;
    PORT
      LAYER Metal3 ;
        RECT  0 946.06 0.4 946.46 ;
    END
  END decode_slot_i.pred[29]
  PIN decode_slot_i.pred[2]
    DIRECTION INPUT ;
    USE SIGNAL ;
    PORT
      LAYER Metal3 ;
        RECT  0 129.58 0.4 129.98 ;
    END
  END decode_slot_i.pred[2]
  PIN decode_slot_i.pred[30]
    DIRECTION INPUT ;
    USE SIGNAL ;
    PORT
      LAYER Metal3 ;
        RECT  0 976.3 0.4 976.7 ;
    END
  END decode_slot_i.pred[30]
  PIN decode_slot_i.pred[31]
    DIRECTION INPUT ;
    USE SIGNAL ;
    PORT
      LAYER Metal3 ;
        RECT  0 1006.54 0.4 1006.94 ;
    END
  END decode_slot_i.pred[31]
  PIN decode_slot_i.pred[32]
    DIRECTION INPUT ;
    USE SIGNAL ;
    PORT
      LAYER Metal3 ;
        RECT  0 1026.7 0.4 1027.1 ;
    END
  END decode_slot_i.pred[32]
  PIN decode_slot_i.pred[33]
    DIRECTION INPUT ;
    USE SIGNAL ;
    PORT
      LAYER Metal3 ;
        RECT  0 1046.86 0.4 1047.26 ;
    END
  END decode_slot_i.pred[33]
  PIN decode_slot_i.pred[34]
    DIRECTION INPUT ;
    USE SIGNAL ;
    PORT
      LAYER Metal3 ;
        RECT  0 1067.02 0.4 1067.42 ;
    END
  END decode_slot_i.pred[34]
  PIN decode_slot_i.pred[35]
    DIRECTION INPUT ;
    USE SIGNAL ;
    PORT
      LAYER Metal3 ;
        RECT  0 1087.18 0.4 1087.58 ;
    END
  END decode_slot_i.pred[35]
  PIN decode_slot_i.pred[36]
    DIRECTION INPUT ;
    USE SIGNAL ;
    PORT
      LAYER Metal3 ;
        RECT  0 1107.34 0.4 1107.74 ;
    END
  END decode_slot_i.pred[36]
  PIN decode_slot_i.pred[37]
    DIRECTION INPUT ;
    USE SIGNAL ;
    PORT
      LAYER Metal3 ;
        RECT  0 1127.5 0.4 1127.9 ;
    END
  END decode_slot_i.pred[37]
  PIN decode_slot_i.pred[38]
    DIRECTION INPUT ;
    USE SIGNAL ;
    PORT
      LAYER Metal3 ;
        RECT  0 1147.66 0.4 1148.06 ;
    END
  END decode_slot_i.pred[38]
  PIN decode_slot_i.pred[39]
    DIRECTION INPUT ;
    USE SIGNAL ;
    PORT
      LAYER Metal3 ;
        RECT  0 1167.82 0.4 1168.22 ;
    END
  END decode_slot_i.pred[39]
  PIN decode_slot_i.pred[3]
    DIRECTION INPUT ;
    USE SIGNAL ;
    PORT
      LAYER Metal3 ;
        RECT  0 159.82 0.4 160.22 ;
    END
  END decode_slot_i.pred[3]
  PIN decode_slot_i.pred[40]
    DIRECTION INPUT ;
    USE SIGNAL ;
    PORT
      LAYER Metal3 ;
        RECT  0 1187.98 0.4 1188.38 ;
    END
  END decode_slot_i.pred[40]
  PIN decode_slot_i.pred[41]
    DIRECTION INPUT ;
    USE SIGNAL ;
    PORT
      LAYER Metal3 ;
        RECT  0 1208.14 0.4 1208.54 ;
    END
  END decode_slot_i.pred[41]
  PIN decode_slot_i.pred[42]
    DIRECTION INPUT ;
    USE SIGNAL ;
    PORT
      LAYER Metal3 ;
        RECT  0 1228.3 0.4 1228.7 ;
    END
  END decode_slot_i.pred[42]
  PIN decode_slot_i.pred[43]
    DIRECTION INPUT ;
    USE SIGNAL ;
    PORT
      LAYER Metal3 ;
        RECT  0 1248.46 0.4 1248.86 ;
    END
  END decode_slot_i.pred[43]
  PIN decode_slot_i.pred[44]
    DIRECTION INPUT ;
    USE SIGNAL ;
    PORT
      LAYER Metal3 ;
        RECT  0 1268.62 0.4 1269.02 ;
    END
  END decode_slot_i.pred[44]
  PIN decode_slot_i.pred[45]
    DIRECTION INPUT ;
    USE SIGNAL ;
    PORT
      LAYER Metal3 ;
        RECT  0 1288.78 0.4 1289.18 ;
    END
  END decode_slot_i.pred[45]
  PIN decode_slot_i.pred[46]
    DIRECTION INPUT ;
    USE SIGNAL ;
    PORT
      LAYER Metal3 ;
        RECT  0 1308.94 0.4 1309.34 ;
    END
  END decode_slot_i.pred[46]
  PIN decode_slot_i.pred[47]
    DIRECTION INPUT ;
    USE SIGNAL ;
    PORT
      LAYER Metal3 ;
        RECT  0 1329.1 0.4 1329.5 ;
    END
  END decode_slot_i.pred[47]
  PIN decode_slot_i.pred[48]
    DIRECTION INPUT ;
    USE SIGNAL ;
    PORT
      LAYER Metal3 ;
        RECT  0 1349.26 0.4 1349.66 ;
    END
  END decode_slot_i.pred[48]
  PIN decode_slot_i.pred[49]
    DIRECTION INPUT ;
    USE SIGNAL ;
    PORT
      LAYER Metal3 ;
        RECT  0 1369.42 0.4 1369.82 ;
    END
  END decode_slot_i.pred[49]
  PIN decode_slot_i.pred[4]
    DIRECTION INPUT ;
    USE SIGNAL ;
    PORT
      LAYER Metal3 ;
        RECT  0 190.06 0.4 190.46 ;
    END
  END decode_slot_i.pred[4]
  PIN decode_slot_i.pred[50]
    DIRECTION INPUT ;
    USE SIGNAL ;
    PORT
      LAYER Metal3 ;
        RECT  0 1389.58 0.4 1389.98 ;
    END
  END decode_slot_i.pred[50]
  PIN decode_slot_i.pred[51]
    DIRECTION INPUT ;
    USE SIGNAL ;
    PORT
      LAYER Metal3 ;
        RECT  0 1409.74 0.4 1410.14 ;
    END
  END decode_slot_i.pred[51]
  PIN decode_slot_i.pred[52]
    DIRECTION INPUT ;
    USE SIGNAL ;
    PORT
      LAYER Metal3 ;
        RECT  0 1429.9 0.4 1430.3 ;
    END
  END decode_slot_i.pred[52]
  PIN decode_slot_i.pred[53]
    DIRECTION INPUT ;
    USE SIGNAL ;
    PORT
      LAYER Metal3 ;
        RECT  0 1450.06 0.4 1450.46 ;
    END
  END decode_slot_i.pred[53]
  PIN decode_slot_i.pred[5]
    DIRECTION INPUT ;
    USE SIGNAL ;
    PORT
      LAYER Metal3 ;
        RECT  0 220.3 0.4 220.7 ;
    END
  END decode_slot_i.pred[5]
  PIN decode_slot_i.pred[6]
    DIRECTION INPUT ;
    USE SIGNAL ;
    PORT
      LAYER Metal3 ;
        RECT  0 250.54 0.4 250.94 ;
    END
  END decode_slot_i.pred[6]
  PIN decode_slot_i.pred[7]
    DIRECTION INPUT ;
    USE SIGNAL ;
    PORT
      LAYER Metal3 ;
        RECT  0 280.78 0.4 281.18 ;
    END
  END decode_slot_i.pred[7]
  PIN decode_slot_i.pred[8]
    DIRECTION INPUT ;
    USE SIGNAL ;
    PORT
      LAYER Metal3 ;
        RECT  0 311.02 0.4 311.42 ;
    END
  END decode_slot_i.pred[8]
  PIN decode_slot_i.pred[9]
    DIRECTION INPUT ;
    USE SIGNAL ;
    PORT
      LAYER Metal3 ;
        RECT  0 341.26 0.4 341.66 ;
    END
  END decode_slot_i.pred[9]
  PIN decode_slot_i.valid
    DIRECTION INPUT ;
    USE SIGNAL ;
    PORT
      LAYER Metal3 ;
        RECT  0 38.86 0.4 39.26 ;
    END
  END decode_slot_i.valid
  PIN decode_take_o
    DIRECTION OUTPUT ;
    USE SIGNAL ;
    PORT
      LAYER Metal3 ;
        RECT  0 28.78 0.4 29.18 ;
    END
  END decode_take_o
  PIN decode_valid_i
    DIRECTION INPUT ;
    USE SIGNAL ;
    PORT
      LAYER Metal2 ;
        RECT  1474.84 1499.6 1475.24 1500 ;
    END
  END decode_valid_i
  PIN disp_o[0]
    DIRECTION OUTPUT ;
    USE SIGNAL ;
    PORT
      LAYER Metal2 ;
        RECT  886.36 0 886.76 0.4 ;
    END
  END disp_o[0]
  PIN disp_o[10]
    DIRECTION OUTPUT ;
    USE SIGNAL ;
    PORT
      LAYER Metal2 ;
        RECT  895.96 0 896.36 0.4 ;
    END
  END disp_o[10]
  PIN disp_o[11]
    DIRECTION OUTPUT ;
    USE SIGNAL ;
    PORT
      LAYER Metal2 ;
        RECT  896.92 0 897.32 0.4 ;
    END
  END disp_o[11]
  PIN disp_o[12]
    DIRECTION OUTPUT ;
    USE SIGNAL ;
    PORT
      LAYER Metal2 ;
        RECT  897.88 0 898.28 0.4 ;
    END
  END disp_o[12]
  PIN disp_o[13]
    DIRECTION OUTPUT ;
    USE SIGNAL ;
    PORT
      LAYER Metal2 ;
        RECT  898.84 0 899.24 0.4 ;
    END
  END disp_o[13]
  PIN disp_o[14]
    DIRECTION OUTPUT ;
    USE SIGNAL ;
    PORT
      LAYER Metal2 ;
        RECT  899.8 0 900.2 0.4 ;
    END
  END disp_o[14]
  PIN disp_o[15]
    DIRECTION OUTPUT ;
    USE SIGNAL ;
    PORT
      LAYER Metal2 ;
        RECT  900.76 0 901.16 0.4 ;
    END
  END disp_o[15]
  PIN disp_o[16]
    DIRECTION OUTPUT ;
    USE SIGNAL ;
    PORT
      LAYER Metal2 ;
        RECT  901.72 0 902.12 0.4 ;
    END
  END disp_o[16]
  PIN disp_o[17]
    DIRECTION OUTPUT ;
    USE SIGNAL ;
    PORT
      LAYER Metal2 ;
        RECT  902.68 0 903.08 0.4 ;
    END
  END disp_o[17]
  PIN disp_o[18]
    DIRECTION OUTPUT ;
    USE SIGNAL ;
    PORT
      LAYER Metal2 ;
        RECT  903.64 0 904.04 0.4 ;
    END
  END disp_o[18]
  PIN disp_o[19]
    DIRECTION OUTPUT ;
    USE SIGNAL ;
    PORT
      LAYER Metal2 ;
        RECT  904.6 0 905 0.4 ;
    END
  END disp_o[19]
  PIN disp_o[1]
    DIRECTION OUTPUT ;
    USE SIGNAL ;
    PORT
      LAYER Metal2 ;
        RECT  887.32 0 887.72 0.4 ;
    END
  END disp_o[1]
  PIN disp_o[20]
    DIRECTION OUTPUT ;
    USE SIGNAL ;
    PORT
      LAYER Metal2 ;
        RECT  905.56 0 905.96 0.4 ;
    END
  END disp_o[20]
  PIN disp_o[21]
    DIRECTION OUTPUT ;
    USE SIGNAL ;
    PORT
      LAYER Metal2 ;
        RECT  906.52 0 906.92 0.4 ;
    END
  END disp_o[21]
  PIN disp_o[22]
    DIRECTION OUTPUT ;
    USE SIGNAL ;
    PORT
      LAYER Metal2 ;
        RECT  907.48 0 907.88 0.4 ;
    END
  END disp_o[22]
  PIN disp_o[23]
    DIRECTION OUTPUT ;
    USE SIGNAL ;
    PORT
      LAYER Metal2 ;
        RECT  908.44 0 908.84 0.4 ;
    END
  END disp_o[23]
  PIN disp_o[24]
    DIRECTION OUTPUT ;
    USE SIGNAL ;
    PORT
      LAYER Metal2 ;
        RECT  909.4 0 909.8 0.4 ;
    END
  END disp_o[24]
  PIN disp_o[25]
    DIRECTION OUTPUT ;
    USE SIGNAL ;
    PORT
      LAYER Metal2 ;
        RECT  910.36 0 910.76 0.4 ;
    END
  END disp_o[25]
  PIN disp_o[26]
    DIRECTION OUTPUT ;
    USE SIGNAL ;
    PORT
      LAYER Metal2 ;
        RECT  911.32 0 911.72 0.4 ;
    END
  END disp_o[26]
  PIN disp_o[27]
    DIRECTION OUTPUT ;
    USE SIGNAL ;
    PORT
      LAYER Metal2 ;
        RECT  912.28 0 912.68 0.4 ;
    END
  END disp_o[27]
  PIN disp_o[28]
    DIRECTION OUTPUT ;
    USE SIGNAL ;
    PORT
      LAYER Metal2 ;
        RECT  913.24 0 913.64 0.4 ;
    END
  END disp_o[28]
  PIN disp_o[29]
    DIRECTION OUTPUT ;
    USE SIGNAL ;
    PORT
      LAYER Metal2 ;
        RECT  914.2 0 914.6 0.4 ;
    END
  END disp_o[29]
  PIN disp_o[2]
    DIRECTION OUTPUT ;
    USE SIGNAL ;
    PORT
      LAYER Metal2 ;
        RECT  888.28 0 888.68 0.4 ;
    END
  END disp_o[2]
  PIN disp_o[30]
    DIRECTION OUTPUT ;
    USE SIGNAL ;
    PORT
      LAYER Metal2 ;
        RECT  915.16 0 915.56 0.4 ;
    END
  END disp_o[30]
  PIN disp_o[31]
    DIRECTION OUTPUT ;
    USE SIGNAL ;
    PORT
      LAYER Metal2 ;
        RECT  916.12 0 916.52 0.4 ;
    END
  END disp_o[31]
  PIN disp_o[3]
    DIRECTION OUTPUT ;
    USE SIGNAL ;
    PORT
      LAYER Metal2 ;
        RECT  889.24 0 889.64 0.4 ;
    END
  END disp_o[3]
  PIN disp_o[4]
    DIRECTION OUTPUT ;
    USE SIGNAL ;
    PORT
      LAYER Metal2 ;
        RECT  890.2 0 890.6 0.4 ;
    END
  END disp_o[4]
  PIN disp_o[5]
    DIRECTION OUTPUT ;
    USE SIGNAL ;
    PORT
      LAYER Metal2 ;
        RECT  891.16 0 891.56 0.4 ;
    END
  END disp_o[5]
  PIN disp_o[6]
    DIRECTION OUTPUT ;
    USE SIGNAL ;
    PORT
      LAYER Metal2 ;
        RECT  892.12 0 892.52 0.4 ;
    END
  END disp_o[6]
  PIN disp_o[7]
    DIRECTION OUTPUT ;
    USE SIGNAL ;
    PORT
      LAYER Metal2 ;
        RECT  893.08 0 893.48 0.4 ;
    END
  END disp_o[7]
  PIN disp_o[8]
    DIRECTION OUTPUT ;
    USE SIGNAL ;
    PORT
      LAYER Metal2 ;
        RECT  894.04 0 894.44 0.4 ;
    END
  END disp_o[8]
  PIN disp_o[9]
    DIRECTION OUTPUT ;
    USE SIGNAL ;
    PORT
      LAYER Metal2 ;
        RECT  895 0 895.4 0.4 ;
    END
  END disp_o[9]
  PIN disp_sel_i[0]
    DIRECTION INPUT ;
    USE SIGNAL ;
    PORT
      LAYER Metal2 ;
        RECT  882.52 0 882.92 0.4 ;
    END
  END disp_sel_i[0]
  PIN disp_sel_i[1]
    DIRECTION INPUT ;
    USE SIGNAL ;
    PORT
      LAYER Metal2 ;
        RECT  883.48 0 883.88 0.4 ;
    END
  END disp_sel_i[1]
  PIN disp_sel_i[2]
    DIRECTION INPUT ;
    USE SIGNAL ;
    PORT
      LAYER Metal2 ;
        RECT  884.44 0 884.84 0.4 ;
    END
  END disp_sel_i[2]
  PIN disp_sel_i[3]
    DIRECTION INPUT ;
    USE SIGNAL ;
    PORT
      LAYER Metal2 ;
        RECT  885.4 0 885.8 0.4 ;
    END
  END disp_sel_i[3]
  PIN disp_wdata_i[0]
    DIRECTION INPUT ;
    USE SIGNAL ;
    PORT
      LAYER Metal3 ;
        RECT  1499.6 1240.9 1500 1241.3 ;
    END
  END disp_wdata_i[0]
  PIN disp_wdata_i[10]
    DIRECTION INPUT ;
    USE SIGNAL ;
    PORT
      LAYER Metal3 ;
        RECT  1499.6 1299.7 1500 1300.1 ;
    END
  END disp_wdata_i[10]
  PIN disp_wdata_i[11]
    DIRECTION INPUT ;
    USE SIGNAL ;
    PORT
      LAYER Metal3 ;
        RECT  1499.6 1305.58 1500 1305.98 ;
    END
  END disp_wdata_i[11]
  PIN disp_wdata_i[12]
    DIRECTION INPUT ;
    USE SIGNAL ;
    PORT
      LAYER Metal3 ;
        RECT  1499.6 1311.46 1500 1311.86 ;
    END
  END disp_wdata_i[12]
  PIN disp_wdata_i[13]
    DIRECTION INPUT ;
    USE SIGNAL ;
    PORT
      LAYER Metal3 ;
        RECT  1499.6 1317.34 1500 1317.74 ;
    END
  END disp_wdata_i[13]
  PIN disp_wdata_i[14]
    DIRECTION INPUT ;
    USE SIGNAL ;
    PORT
      LAYER Metal3 ;
        RECT  1499.6 1323.22 1500 1323.62 ;
    END
  END disp_wdata_i[14]
  PIN disp_wdata_i[15]
    DIRECTION INPUT ;
    USE SIGNAL ;
    PORT
      LAYER Metal3 ;
        RECT  1499.6 1329.1 1500 1329.5 ;
    END
  END disp_wdata_i[15]
  PIN disp_wdata_i[16]
    DIRECTION INPUT ;
    USE SIGNAL ;
    PORT
      LAYER Metal3 ;
        RECT  1499.6 1334.98 1500 1335.38 ;
    END
  END disp_wdata_i[16]
  PIN disp_wdata_i[17]
    DIRECTION INPUT ;
    USE SIGNAL ;
    PORT
      LAYER Metal3 ;
        RECT  1499.6 1340.86 1500 1341.26 ;
    END
  END disp_wdata_i[17]
  PIN disp_wdata_i[18]
    DIRECTION INPUT ;
    USE SIGNAL ;
    PORT
      LAYER Metal3 ;
        RECT  1499.6 1346.74 1500 1347.14 ;
    END
  END disp_wdata_i[18]
  PIN disp_wdata_i[19]
    DIRECTION INPUT ;
    USE SIGNAL ;
    PORT
      LAYER Metal3 ;
        RECT  1499.6 1352.62 1500 1353.02 ;
    END
  END disp_wdata_i[19]
  PIN disp_wdata_i[1]
    DIRECTION INPUT ;
    USE SIGNAL ;
    PORT
      LAYER Metal3 ;
        RECT  1499.6 1246.78 1500 1247.18 ;
    END
  END disp_wdata_i[1]
  PIN disp_wdata_i[20]
    DIRECTION INPUT ;
    USE SIGNAL ;
    PORT
      LAYER Metal3 ;
        RECT  1499.6 1358.5 1500 1358.9 ;
    END
  END disp_wdata_i[20]
  PIN disp_wdata_i[21]
    DIRECTION INPUT ;
    USE SIGNAL ;
    PORT
      LAYER Metal3 ;
        RECT  1499.6 1364.38 1500 1364.78 ;
    END
  END disp_wdata_i[21]
  PIN disp_wdata_i[22]
    DIRECTION INPUT ;
    USE SIGNAL ;
    PORT
      LAYER Metal3 ;
        RECT  1499.6 1370.26 1500 1370.66 ;
    END
  END disp_wdata_i[22]
  PIN disp_wdata_i[23]
    DIRECTION INPUT ;
    USE SIGNAL ;
    PORT
      LAYER Metal3 ;
        RECT  1499.6 1376.14 1500 1376.54 ;
    END
  END disp_wdata_i[23]
  PIN disp_wdata_i[24]
    DIRECTION INPUT ;
    USE SIGNAL ;
    PORT
      LAYER Metal3 ;
        RECT  1499.6 1382.02 1500 1382.42 ;
    END
  END disp_wdata_i[24]
  PIN disp_wdata_i[25]
    DIRECTION INPUT ;
    USE SIGNAL ;
    PORT
      LAYER Metal3 ;
        RECT  1499.6 1387.9 1500 1388.3 ;
    END
  END disp_wdata_i[25]
  PIN disp_wdata_i[26]
    DIRECTION INPUT ;
    USE SIGNAL ;
    PORT
      LAYER Metal3 ;
        RECT  1499.6 1393.78 1500 1394.18 ;
    END
  END disp_wdata_i[26]
  PIN disp_wdata_i[27]
    DIRECTION INPUT ;
    USE SIGNAL ;
    PORT
      LAYER Metal3 ;
        RECT  1499.6 1399.66 1500 1400.06 ;
    END
  END disp_wdata_i[27]
  PIN disp_wdata_i[28]
    DIRECTION INPUT ;
    USE SIGNAL ;
    PORT
      LAYER Metal3 ;
        RECT  1499.6 1405.54 1500 1405.94 ;
    END
  END disp_wdata_i[28]
  PIN disp_wdata_i[29]
    DIRECTION INPUT ;
    USE SIGNAL ;
    PORT
      LAYER Metal3 ;
        RECT  1499.6 1411.42 1500 1411.82 ;
    END
  END disp_wdata_i[29]
  PIN disp_wdata_i[2]
    DIRECTION INPUT ;
    USE SIGNAL ;
    PORT
      LAYER Metal3 ;
        RECT  1499.6 1252.66 1500 1253.06 ;
    END
  END disp_wdata_i[2]
  PIN disp_wdata_i[30]
    DIRECTION INPUT ;
    USE SIGNAL ;
    PORT
      LAYER Metal3 ;
        RECT  1499.6 1417.3 1500 1417.7 ;
    END
  END disp_wdata_i[30]
  PIN disp_wdata_i[31]
    DIRECTION INPUT ;
    USE SIGNAL ;
    PORT
      LAYER Metal3 ;
        RECT  1499.6 1423.18 1500 1423.58 ;
    END
  END disp_wdata_i[31]
  PIN disp_wdata_i[3]
    DIRECTION INPUT ;
    USE SIGNAL ;
    PORT
      LAYER Metal3 ;
        RECT  1499.6 1258.54 1500 1258.94 ;
    END
  END disp_wdata_i[3]
  PIN disp_wdata_i[4]
    DIRECTION INPUT ;
    USE SIGNAL ;
    PORT
      LAYER Metal3 ;
        RECT  1499.6 1264.42 1500 1264.82 ;
    END
  END disp_wdata_i[4]
  PIN disp_wdata_i[5]
    DIRECTION INPUT ;
    USE SIGNAL ;
    PORT
      LAYER Metal3 ;
        RECT  1499.6 1270.3 1500 1270.7 ;
    END
  END disp_wdata_i[5]
  PIN disp_wdata_i[6]
    DIRECTION INPUT ;
    USE SIGNAL ;
    PORT
      LAYER Metal3 ;
        RECT  1499.6 1276.18 1500 1276.58 ;
    END
  END disp_wdata_i[6]
  PIN disp_wdata_i[7]
    DIRECTION INPUT ;
    USE SIGNAL ;
    PORT
      LAYER Metal3 ;
        RECT  1499.6 1282.06 1500 1282.46 ;
    END
  END disp_wdata_i[7]
  PIN disp_wdata_i[8]
    DIRECTION INPUT ;
    USE SIGNAL ;
    PORT
      LAYER Metal3 ;
        RECT  1499.6 1287.94 1500 1288.34 ;
    END
  END disp_wdata_i[8]
  PIN disp_wdata_i[9]
    DIRECTION INPUT ;
    USE SIGNAL ;
    PORT
      LAYER Metal3 ;
        RECT  1499.6 1293.82 1500 1294.22 ;
    END
  END disp_wdata_i[9]
  PIN disp_we_i
    DIRECTION INPUT ;
    USE SIGNAL ;
    PORT
      LAYER Metal3 ;
        RECT  1499.6 1211.5 1500 1211.9 ;
    END
  END disp_we_i
  PIN disp_wsel_i[0]
    DIRECTION INPUT ;
    USE SIGNAL ;
    PORT
      LAYER Metal3 ;
        RECT  1499.6 1217.38 1500 1217.78 ;
    END
  END disp_wsel_i[0]
  PIN disp_wsel_i[1]
    DIRECTION INPUT ;
    USE SIGNAL ;
    PORT
      LAYER Metal3 ;
        RECT  1499.6 1223.26 1500 1223.66 ;
    END
  END disp_wsel_i[1]
  PIN disp_wsel_i[2]
    DIRECTION INPUT ;
    USE SIGNAL ;
    PORT
      LAYER Metal3 ;
        RECT  1499.6 1229.14 1500 1229.54 ;
    END
  END disp_wsel_i[2]
  PIN disp_wsel_i[3]
    DIRECTION INPUT ;
    USE SIGNAL ;
    PORT
      LAYER Metal3 ;
        RECT  1499.6 1235.02 1500 1235.42 ;
    END
  END disp_wsel_i[3]
  PIN frame_dsp_o[0]
    DIRECTION OUTPUT ;
    USE SIGNAL ;
    PORT
      LAYER Metal2 ;
        RECT  821.08 0 821.48 0.4 ;
    END
  END frame_dsp_o[0]
  PIN frame_dsp_o[10]
    DIRECTION OUTPUT ;
    USE SIGNAL ;
    PORT
      LAYER Metal2 ;
        RECT  830.68 0 831.08 0.4 ;
    END
  END frame_dsp_o[10]
  PIN frame_dsp_o[11]
    DIRECTION OUTPUT ;
    USE SIGNAL ;
    PORT
      LAYER Metal2 ;
        RECT  831.64 0 832.04 0.4 ;
    END
  END frame_dsp_o[11]
  PIN frame_dsp_o[12]
    DIRECTION OUTPUT ;
    USE SIGNAL ;
    PORT
      LAYER Metal2 ;
        RECT  832.6 0 833 0.4 ;
    END
  END frame_dsp_o[12]
  PIN frame_dsp_o[13]
    DIRECTION OUTPUT ;
    USE SIGNAL ;
    PORT
      LAYER Metal2 ;
        RECT  833.56 0 833.96 0.4 ;
    END
  END frame_dsp_o[13]
  PIN frame_dsp_o[14]
    DIRECTION OUTPUT ;
    USE SIGNAL ;
    PORT
      LAYER Metal2 ;
        RECT  834.52 0 834.92 0.4 ;
    END
  END frame_dsp_o[14]
  PIN frame_dsp_o[15]
    DIRECTION OUTPUT ;
    USE SIGNAL ;
    PORT
      LAYER Metal2 ;
        RECT  835.48 0 835.88 0.4 ;
    END
  END frame_dsp_o[15]
  PIN frame_dsp_o[16]
    DIRECTION OUTPUT ;
    USE SIGNAL ;
    PORT
      LAYER Metal2 ;
        RECT  836.44 0 836.84 0.4 ;
    END
  END frame_dsp_o[16]
  PIN frame_dsp_o[17]
    DIRECTION OUTPUT ;
    USE SIGNAL ;
    PORT
      LAYER Metal2 ;
        RECT  837.4 0 837.8 0.4 ;
    END
  END frame_dsp_o[17]
  PIN frame_dsp_o[18]
    DIRECTION OUTPUT ;
    USE SIGNAL ;
    PORT
      LAYER Metal2 ;
        RECT  838.36 0 838.76 0.4 ;
    END
  END frame_dsp_o[18]
  PIN frame_dsp_o[19]
    DIRECTION OUTPUT ;
    USE SIGNAL ;
    PORT
      LAYER Metal2 ;
        RECT  839.32 0 839.72 0.4 ;
    END
  END frame_dsp_o[19]
  PIN frame_dsp_o[1]
    DIRECTION OUTPUT ;
    USE SIGNAL ;
    PORT
      LAYER Metal2 ;
        RECT  822.04 0 822.44 0.4 ;
    END
  END frame_dsp_o[1]
  PIN frame_dsp_o[20]
    DIRECTION OUTPUT ;
    USE SIGNAL ;
    PORT
      LAYER Metal2 ;
        RECT  840.28 0 840.68 0.4 ;
    END
  END frame_dsp_o[20]
  PIN frame_dsp_o[21]
    DIRECTION OUTPUT ;
    USE SIGNAL ;
    PORT
      LAYER Metal2 ;
        RECT  841.24 0 841.64 0.4 ;
    END
  END frame_dsp_o[21]
  PIN frame_dsp_o[22]
    DIRECTION OUTPUT ;
    USE SIGNAL ;
    PORT
      LAYER Metal2 ;
        RECT  842.2 0 842.6 0.4 ;
    END
  END frame_dsp_o[22]
  PIN frame_dsp_o[23]
    DIRECTION OUTPUT ;
    USE SIGNAL ;
    PORT
      LAYER Metal2 ;
        RECT  843.16 0 843.56 0.4 ;
    END
  END frame_dsp_o[23]
  PIN frame_dsp_o[24]
    DIRECTION OUTPUT ;
    USE SIGNAL ;
    PORT
      LAYER Metal2 ;
        RECT  844.12 0 844.52 0.4 ;
    END
  END frame_dsp_o[24]
  PIN frame_dsp_o[25]
    DIRECTION OUTPUT ;
    USE SIGNAL ;
    PORT
      LAYER Metal2 ;
        RECT  845.08 0 845.48 0.4 ;
    END
  END frame_dsp_o[25]
  PIN frame_dsp_o[26]
    DIRECTION OUTPUT ;
    USE SIGNAL ;
    PORT
      LAYER Metal2 ;
        RECT  846.04 0 846.44 0.4 ;
    END
  END frame_dsp_o[26]
  PIN frame_dsp_o[27]
    DIRECTION OUTPUT ;
    USE SIGNAL ;
    PORT
      LAYER Metal2 ;
        RECT  847 0 847.4 0.4 ;
    END
  END frame_dsp_o[27]
  PIN frame_dsp_o[28]
    DIRECTION OUTPUT ;
    USE SIGNAL ;
    PORT
      LAYER Metal2 ;
        RECT  847.96 0 848.36 0.4 ;
    END
  END frame_dsp_o[28]
  PIN frame_dsp_o[29]
    DIRECTION OUTPUT ;
    USE SIGNAL ;
    PORT
      LAYER Metal2 ;
        RECT  848.92 0 849.32 0.4 ;
    END
  END frame_dsp_o[29]
  PIN frame_dsp_o[2]
    DIRECTION OUTPUT ;
    USE SIGNAL ;
    PORT
      LAYER Metal2 ;
        RECT  823 0 823.4 0.4 ;
    END
  END frame_dsp_o[2]
  PIN frame_dsp_o[30]
    DIRECTION OUTPUT ;
    USE SIGNAL ;
    PORT
      LAYER Metal2 ;
        RECT  849.88 0 850.28 0.4 ;
    END
  END frame_dsp_o[30]
  PIN frame_dsp_o[31]
    DIRECTION OUTPUT ;
    USE SIGNAL ;
    PORT
      LAYER Metal2 ;
        RECT  850.84 0 851.24 0.4 ;
    END
  END frame_dsp_o[31]
  PIN frame_dsp_o[3]
    DIRECTION OUTPUT ;
    USE SIGNAL ;
    PORT
      LAYER Metal2 ;
        RECT  823.96 0 824.36 0.4 ;
    END
  END frame_dsp_o[3]
  PIN frame_dsp_o[4]
    DIRECTION OUTPUT ;
    USE SIGNAL ;
    PORT
      LAYER Metal2 ;
        RECT  824.92 0 825.32 0.4 ;
    END
  END frame_dsp_o[4]
  PIN frame_dsp_o[5]
    DIRECTION OUTPUT ;
    USE SIGNAL ;
    PORT
      LAYER Metal2 ;
        RECT  825.88 0 826.28 0.4 ;
    END
  END frame_dsp_o[5]
  PIN frame_dsp_o[6]
    DIRECTION OUTPUT ;
    USE SIGNAL ;
    PORT
      LAYER Metal2 ;
        RECT  826.84 0 827.24 0.4 ;
    END
  END frame_dsp_o[6]
  PIN frame_dsp_o[7]
    DIRECTION OUTPUT ;
    USE SIGNAL ;
    PORT
      LAYER Metal2 ;
        RECT  827.8 0 828.2 0.4 ;
    END
  END frame_dsp_o[7]
  PIN frame_dsp_o[8]
    DIRECTION OUTPUT ;
    USE SIGNAL ;
    PORT
      LAYER Metal2 ;
        RECT  828.76 0 829.16 0.4 ;
    END
  END frame_dsp_o[8]
  PIN frame_dsp_o[9]
    DIRECTION OUTPUT ;
    USE SIGNAL ;
    PORT
      LAYER Metal2 ;
        RECT  829.72 0 830.12 0.4 ;
    END
  END frame_dsp_o[9]
  PIN frame_rsp_o[0]
    DIRECTION OUTPUT ;
    USE SIGNAL ;
    PORT
      LAYER Metal2 ;
        RECT  851.8 0 852.2 0.4 ;
    END
  END frame_rsp_o[0]
  PIN frame_rsp_o[10]
    DIRECTION OUTPUT ;
    USE SIGNAL ;
    PORT
      LAYER Metal2 ;
        RECT  861.4 0 861.8 0.4 ;
    END
  END frame_rsp_o[10]
  PIN frame_rsp_o[11]
    DIRECTION OUTPUT ;
    USE SIGNAL ;
    PORT
      LAYER Metal2 ;
        RECT  862.36 0 862.76 0.4 ;
    END
  END frame_rsp_o[11]
  PIN frame_rsp_o[12]
    DIRECTION OUTPUT ;
    USE SIGNAL ;
    PORT
      LAYER Metal2 ;
        RECT  863.32 0 863.72 0.4 ;
    END
  END frame_rsp_o[12]
  PIN frame_rsp_o[13]
    DIRECTION OUTPUT ;
    USE SIGNAL ;
    PORT
      LAYER Metal2 ;
        RECT  864.28 0 864.68 0.4 ;
    END
  END frame_rsp_o[13]
  PIN frame_rsp_o[14]
    DIRECTION OUTPUT ;
    USE SIGNAL ;
    PORT
      LAYER Metal2 ;
        RECT  865.24 0 865.64 0.4 ;
    END
  END frame_rsp_o[14]
  PIN frame_rsp_o[15]
    DIRECTION OUTPUT ;
    USE SIGNAL ;
    PORT
      LAYER Metal2 ;
        RECT  866.2 0 866.6 0.4 ;
    END
  END frame_rsp_o[15]
  PIN frame_rsp_o[16]
    DIRECTION OUTPUT ;
    USE SIGNAL ;
    PORT
      LAYER Metal2 ;
        RECT  867.16 0 867.56 0.4 ;
    END
  END frame_rsp_o[16]
  PIN frame_rsp_o[17]
    DIRECTION OUTPUT ;
    USE SIGNAL ;
    PORT
      LAYER Metal2 ;
        RECT  868.12 0 868.52 0.4 ;
    END
  END frame_rsp_o[17]
  PIN frame_rsp_o[18]
    DIRECTION OUTPUT ;
    USE SIGNAL ;
    PORT
      LAYER Metal2 ;
        RECT  869.08 0 869.48 0.4 ;
    END
  END frame_rsp_o[18]
  PIN frame_rsp_o[19]
    DIRECTION OUTPUT ;
    USE SIGNAL ;
    PORT
      LAYER Metal2 ;
        RECT  870.04 0 870.44 0.4 ;
    END
  END frame_rsp_o[19]
  PIN frame_rsp_o[1]
    DIRECTION OUTPUT ;
    USE SIGNAL ;
    PORT
      LAYER Metal2 ;
        RECT  852.76 0 853.16 0.4 ;
    END
  END frame_rsp_o[1]
  PIN frame_rsp_o[20]
    DIRECTION OUTPUT ;
    USE SIGNAL ;
    PORT
      LAYER Metal2 ;
        RECT  871 0 871.4 0.4 ;
    END
  END frame_rsp_o[20]
  PIN frame_rsp_o[21]
    DIRECTION OUTPUT ;
    USE SIGNAL ;
    PORT
      LAYER Metal2 ;
        RECT  871.96 0 872.36 0.4 ;
    END
  END frame_rsp_o[21]
  PIN frame_rsp_o[22]
    DIRECTION OUTPUT ;
    USE SIGNAL ;
    PORT
      LAYER Metal2 ;
        RECT  872.92 0 873.32 0.4 ;
    END
  END frame_rsp_o[22]
  PIN frame_rsp_o[23]
    DIRECTION OUTPUT ;
    USE SIGNAL ;
    PORT
      LAYER Metal2 ;
        RECT  873.88 0 874.28 0.4 ;
    END
  END frame_rsp_o[23]
  PIN frame_rsp_o[24]
    DIRECTION OUTPUT ;
    USE SIGNAL ;
    PORT
      LAYER Metal2 ;
        RECT  874.84 0 875.24 0.4 ;
    END
  END frame_rsp_o[24]
  PIN frame_rsp_o[25]
    DIRECTION OUTPUT ;
    USE SIGNAL ;
    PORT
      LAYER Metal2 ;
        RECT  875.8 0 876.2 0.4 ;
    END
  END frame_rsp_o[25]
  PIN frame_rsp_o[26]
    DIRECTION OUTPUT ;
    USE SIGNAL ;
    PORT
      LAYER Metal2 ;
        RECT  876.76 0 877.16 0.4 ;
    END
  END frame_rsp_o[26]
  PIN frame_rsp_o[27]
    DIRECTION OUTPUT ;
    USE SIGNAL ;
    PORT
      LAYER Metal2 ;
        RECT  877.72 0 878.12 0.4 ;
    END
  END frame_rsp_o[27]
  PIN frame_rsp_o[28]
    DIRECTION OUTPUT ;
    USE SIGNAL ;
    PORT
      LAYER Metal2 ;
        RECT  878.68 0 879.08 0.4 ;
    END
  END frame_rsp_o[28]
  PIN frame_rsp_o[29]
    DIRECTION OUTPUT ;
    USE SIGNAL ;
    PORT
      LAYER Metal2 ;
        RECT  879.64 0 880.04 0.4 ;
    END
  END frame_rsp_o[29]
  PIN frame_rsp_o[2]
    DIRECTION OUTPUT ;
    USE SIGNAL ;
    PORT
      LAYER Metal2 ;
        RECT  853.72 0 854.12 0.4 ;
    END
  END frame_rsp_o[2]
  PIN frame_rsp_o[30]
    DIRECTION OUTPUT ;
    USE SIGNAL ;
    PORT
      LAYER Metal2 ;
        RECT  880.6 0 881 0.4 ;
    END
  END frame_rsp_o[30]
  PIN frame_rsp_o[31]
    DIRECTION OUTPUT ;
    USE SIGNAL ;
    PORT
      LAYER Metal2 ;
        RECT  881.56 0 881.96 0.4 ;
    END
  END frame_rsp_o[31]
  PIN frame_rsp_o[3]
    DIRECTION OUTPUT ;
    USE SIGNAL ;
    PORT
      LAYER Metal2 ;
        RECT  854.68 0 855.08 0.4 ;
    END
  END frame_rsp_o[3]
  PIN frame_rsp_o[4]
    DIRECTION OUTPUT ;
    USE SIGNAL ;
    PORT
      LAYER Metal2 ;
        RECT  855.64 0 856.04 0.4 ;
    END
  END frame_rsp_o[4]
  PIN frame_rsp_o[5]
    DIRECTION OUTPUT ;
    USE SIGNAL ;
    PORT
      LAYER Metal2 ;
        RECT  856.6 0 857 0.4 ;
    END
  END frame_rsp_o[5]
  PIN frame_rsp_o[6]
    DIRECTION OUTPUT ;
    USE SIGNAL ;
    PORT
      LAYER Metal2 ;
        RECT  857.56 0 857.96 0.4 ;
    END
  END frame_rsp_o[6]
  PIN frame_rsp_o[7]
    DIRECTION OUTPUT ;
    USE SIGNAL ;
    PORT
      LAYER Metal2 ;
        RECT  858.52 0 858.92 0.4 ;
    END
  END frame_rsp_o[7]
  PIN frame_rsp_o[8]
    DIRECTION OUTPUT ;
    USE SIGNAL ;
    PORT
      LAYER Metal2 ;
        RECT  859.48 0 859.88 0.4 ;
    END
  END frame_rsp_o[8]
  PIN frame_rsp_o[9]
    DIRECTION OUTPUT ;
    USE SIGNAL ;
    PORT
      LAYER Metal2 ;
        RECT  860.44 0 860.84 0.4 ;
    END
  END frame_rsp_o[9]
  PIN idle_o
    DIRECTION OUTPUT ;
    USE SIGNAL ;
    PORT
      LAYER Metal2 ;
        RECT  1467.16 1499.6 1467.56 1500 ;
    END
  END idle_o
  PIN issue_o.address[0]
    DIRECTION OUTPUT ;
    USE SIGNAL ;
    PORT
      LAYER Metal2 ;
        RECT  297.88 0 298.28 0.4 ;
    END
  END issue_o.address[0]
  PIN issue_o.address[10]
    DIRECTION OUTPUT ;
    USE SIGNAL ;
    PORT
      LAYER Metal2 ;
        RECT  332.44 0 332.84 0.4 ;
    END
  END issue_o.address[10]
  PIN issue_o.address[11]
    DIRECTION OUTPUT ;
    USE SIGNAL ;
    PORT
      LAYER Metal2 ;
        RECT  335.32 0 335.72 0.4 ;
    END
  END issue_o.address[11]
  PIN issue_o.address[12]
    DIRECTION OUTPUT ;
    USE SIGNAL ;
    PORT
      LAYER Metal2 ;
        RECT  338.2 0 338.6 0.4 ;
    END
  END issue_o.address[12]
  PIN issue_o.address[13]
    DIRECTION OUTPUT ;
    USE SIGNAL ;
    PORT
      LAYER Metal2 ;
        RECT  341.08 0 341.48 0.4 ;
    END
  END issue_o.address[13]
  PIN issue_o.address[14]
    DIRECTION OUTPUT ;
    USE SIGNAL ;
    PORT
      LAYER Metal2 ;
        RECT  343.96 0 344.36 0.4 ;
    END
  END issue_o.address[14]
  PIN issue_o.address[15]
    DIRECTION OUTPUT ;
    USE SIGNAL ;
    PORT
      LAYER Metal2 ;
        RECT  346.84 0 347.24 0.4 ;
    END
  END issue_o.address[15]
  PIN issue_o.address[16]
    DIRECTION OUTPUT ;
    USE SIGNAL ;
    PORT
      LAYER Metal2 ;
        RECT  349.72 0 350.12 0.4 ;
    END
  END issue_o.address[16]
  PIN issue_o.address[17]
    DIRECTION OUTPUT ;
    USE SIGNAL ;
    PORT
      LAYER Metal2 ;
        RECT  352.6 0 353 0.4 ;
    END
  END issue_o.address[17]
  PIN issue_o.address[18]
    DIRECTION OUTPUT ;
    USE SIGNAL ;
    PORT
      LAYER Metal2 ;
        RECT  355.48 0 355.88 0.4 ;
    END
  END issue_o.address[18]
  PIN issue_o.address[19]
    DIRECTION OUTPUT ;
    USE SIGNAL ;
    PORT
      LAYER Metal2 ;
        RECT  358.36 0 358.76 0.4 ;
    END
  END issue_o.address[19]
  PIN issue_o.address[1]
    DIRECTION OUTPUT ;
    USE SIGNAL ;
    PORT
      LAYER Metal2 ;
        RECT  302.68 0 303.08 0.4 ;
    END
  END issue_o.address[1]
  PIN issue_o.address[20]
    DIRECTION OUTPUT ;
    USE SIGNAL ;
    PORT
      LAYER Metal2 ;
        RECT  361.24 0 361.64 0.4 ;
    END
  END issue_o.address[20]
  PIN issue_o.address[21]
    DIRECTION OUTPUT ;
    USE SIGNAL ;
    PORT
      LAYER Metal2 ;
        RECT  364.12 0 364.52 0.4 ;
    END
  END issue_o.address[21]
  PIN issue_o.address[22]
    DIRECTION OUTPUT ;
    USE SIGNAL ;
    PORT
      LAYER Metal2 ;
        RECT  367 0 367.4 0.4 ;
    END
  END issue_o.address[22]
  PIN issue_o.address[23]
    DIRECTION OUTPUT ;
    USE SIGNAL ;
    PORT
      LAYER Metal2 ;
        RECT  369.88 0 370.28 0.4 ;
    END
  END issue_o.address[23]
  PIN issue_o.address[24]
    DIRECTION OUTPUT ;
    USE SIGNAL ;
    PORT
      LAYER Metal2 ;
        RECT  372.76 0 373.16 0.4 ;
    END
  END issue_o.address[24]
  PIN issue_o.address[25]
    DIRECTION OUTPUT ;
    USE SIGNAL ;
    PORT
      LAYER Metal2 ;
        RECT  375.64 0 376.04 0.4 ;
    END
  END issue_o.address[25]
  PIN issue_o.address[26]
    DIRECTION OUTPUT ;
    USE SIGNAL ;
    PORT
      LAYER Metal2 ;
        RECT  378.52 0 378.92 0.4 ;
    END
  END issue_o.address[26]
  PIN issue_o.address[27]
    DIRECTION OUTPUT ;
    USE SIGNAL ;
    PORT
      LAYER Metal2 ;
        RECT  381.4 0 381.8 0.4 ;
    END
  END issue_o.address[27]
  PIN issue_o.address[28]
    DIRECTION OUTPUT ;
    USE SIGNAL ;
    PORT
      LAYER Metal2 ;
        RECT  384.28 0 384.68 0.4 ;
    END
  END issue_o.address[28]
  PIN issue_o.address[29]
    DIRECTION OUTPUT ;
    USE SIGNAL ;
    PORT
      LAYER Metal2 ;
        RECT  387.16 0 387.56 0.4 ;
    END
  END issue_o.address[29]
  PIN issue_o.address[2]
    DIRECTION OUTPUT ;
    USE SIGNAL ;
    PORT
      LAYER Metal2 ;
        RECT  307.48 0 307.88 0.4 ;
    END
  END issue_o.address[2]
  PIN issue_o.address[30]
    DIRECTION OUTPUT ;
    USE SIGNAL ;
    PORT
      LAYER Metal2 ;
        RECT  390.04 0 390.44 0.4 ;
    END
  END issue_o.address[30]
  PIN issue_o.address[31]
    DIRECTION OUTPUT ;
    USE SIGNAL ;
    PORT
      LAYER Metal2 ;
        RECT  392.92 0 393.32 0.4 ;
    END
  END issue_o.address[31]
  PIN issue_o.address[3]
    DIRECTION OUTPUT ;
    USE SIGNAL ;
    PORT
      LAYER Metal2 ;
        RECT  312.28 0 312.68 0.4 ;
    END
  END issue_o.address[3]
  PIN issue_o.address[4]
    DIRECTION OUTPUT ;
    USE SIGNAL ;
    PORT
      LAYER Metal2 ;
        RECT  315.16 0 315.56 0.4 ;
    END
  END issue_o.address[4]
  PIN issue_o.address[5]
    DIRECTION OUTPUT ;
    USE SIGNAL ;
    PORT
      LAYER Metal2 ;
        RECT  318.04 0 318.44 0.4 ;
    END
  END issue_o.address[5]
  PIN issue_o.address[6]
    DIRECTION OUTPUT ;
    USE SIGNAL ;
    PORT
      LAYER Metal2 ;
        RECT  320.92 0 321.32 0.4 ;
    END
  END issue_o.address[6]
  PIN issue_o.address[7]
    DIRECTION OUTPUT ;
    USE SIGNAL ;
    PORT
      LAYER Metal2 ;
        RECT  323.8 0 324.2 0.4 ;
    END
  END issue_o.address[7]
  PIN issue_o.address[8]
    DIRECTION OUTPUT ;
    USE SIGNAL ;
    PORT
      LAYER Metal2 ;
        RECT  326.68 0 327.08 0.4 ;
    END
  END issue_o.address[8]
  PIN issue_o.address[9]
    DIRECTION OUTPUT ;
    USE SIGNAL ;
    PORT
      LAYER Metal2 ;
        RECT  329.56 0 329.96 0.4 ;
    END
  END issue_o.address[9]
  PIN issue_o.address_known
    DIRECTION OUTPUT ;
    USE SIGNAL ;
    PORT
      LAYER Metal2 ;
        RECT  295.96 0 296.36 0.4 ;
    END
  END issue_o.address_known
  PIN issue_o.address_ofs
    DIRECTION OUTPUT ;
    USE SIGNAL ;
    PORT
      LAYER Metal2 ;
        RECT  296.92 0 297.32 0.4 ;
    END
  END issue_o.address_ofs
  PIN issue_o.issue_class[0]
    DIRECTION OUTPUT ;
    USE SIGNAL ;
    PORT
      LAYER Metal2 ;
        RECT  298.84 0 299.24 0.4 ;
    END
  END issue_o.issue_class[0]
  PIN issue_o.issue_class[1]
    DIRECTION OUTPUT ;
    USE SIGNAL ;
    PORT
      LAYER Metal2 ;
        RECT  303.64 0 304.04 0.4 ;
    END
  END issue_o.issue_class[1]
  PIN issue_o.issue_class[2]
    DIRECTION OUTPUT ;
    USE SIGNAL ;
    PORT
      LAYER Metal2 ;
        RECT  308.44 0 308.84 0.4 ;
    END
  END issue_o.issue_class[2]
  PIN issue_o.operand[0]
    DIRECTION OUTPUT ;
    USE SIGNAL ;
    PORT
      LAYER Metal2 ;
        RECT  299.8 0 300.2 0.4 ;
    END
  END issue_o.operand[0]
  PIN issue_o.operand[100]
    DIRECTION OUTPUT ;
    USE SIGNAL ;
    PORT
      LAYER Metal2 ;
        RECT  526.36 0 526.76 0.4 ;
    END
  END issue_o.operand[100]
  PIN issue_o.operand[101]
    DIRECTION OUTPUT ;
    USE SIGNAL ;
    PORT
      LAYER Metal2 ;
        RECT  528.28 0 528.68 0.4 ;
    END
  END issue_o.operand[101]
  PIN issue_o.operand[102]
    DIRECTION OUTPUT ;
    USE SIGNAL ;
    PORT
      LAYER Metal2 ;
        RECT  530.2 0 530.6 0.4 ;
    END
  END issue_o.operand[102]
  PIN issue_o.operand[103]
    DIRECTION OUTPUT ;
    USE SIGNAL ;
    PORT
      LAYER Metal2 ;
        RECT  532.12 0 532.52 0.4 ;
    END
  END issue_o.operand[103]
  PIN issue_o.operand[104]
    DIRECTION OUTPUT ;
    USE SIGNAL ;
    PORT
      LAYER Metal2 ;
        RECT  534.04 0 534.44 0.4 ;
    END
  END issue_o.operand[104]
  PIN issue_o.operand[105]
    DIRECTION OUTPUT ;
    USE SIGNAL ;
    PORT
      LAYER Metal2 ;
        RECT  535.96 0 536.36 0.4 ;
    END
  END issue_o.operand[105]
  PIN issue_o.operand[106]
    DIRECTION OUTPUT ;
    USE SIGNAL ;
    PORT
      LAYER Metal2 ;
        RECT  537.88 0 538.28 0.4 ;
    END
  END issue_o.operand[106]
  PIN issue_o.operand[107]
    DIRECTION OUTPUT ;
    USE SIGNAL ;
    PORT
      LAYER Metal2 ;
        RECT  539.8 0 540.2 0.4 ;
    END
  END issue_o.operand[107]
  PIN issue_o.operand[108]
    DIRECTION OUTPUT ;
    USE SIGNAL ;
    PORT
      LAYER Metal2 ;
        RECT  541.72 0 542.12 0.4 ;
    END
  END issue_o.operand[108]
  PIN issue_o.operand[109]
    DIRECTION OUTPUT ;
    USE SIGNAL ;
    PORT
      LAYER Metal2 ;
        RECT  543.64 0 544.04 0.4 ;
    END
  END issue_o.operand[109]
  PIN issue_o.operand[10]
    DIRECTION OUTPUT ;
    USE SIGNAL ;
    PORT
      LAYER Metal2 ;
        RECT  333.4 0 333.8 0.4 ;
    END
  END issue_o.operand[10]
  PIN issue_o.operand[110]
    DIRECTION OUTPUT ;
    USE SIGNAL ;
    PORT
      LAYER Metal2 ;
        RECT  545.56 0 545.96 0.4 ;
    END
  END issue_o.operand[110]
  PIN issue_o.operand[111]
    DIRECTION OUTPUT ;
    USE SIGNAL ;
    PORT
      LAYER Metal2 ;
        RECT  547.48 0 547.88 0.4 ;
    END
  END issue_o.operand[111]
  PIN issue_o.operand[112]
    DIRECTION OUTPUT ;
    USE SIGNAL ;
    PORT
      LAYER Metal2 ;
        RECT  549.4 0 549.8 0.4 ;
    END
  END issue_o.operand[112]
  PIN issue_o.operand[113]
    DIRECTION OUTPUT ;
    USE SIGNAL ;
    PORT
      LAYER Metal2 ;
        RECT  551.32 0 551.72 0.4 ;
    END
  END issue_o.operand[113]
  PIN issue_o.operand[114]
    DIRECTION OUTPUT ;
    USE SIGNAL ;
    PORT
      LAYER Metal2 ;
        RECT  553.24 0 553.64 0.4 ;
    END
  END issue_o.operand[114]
  PIN issue_o.operand[115]
    DIRECTION OUTPUT ;
    USE SIGNAL ;
    PORT
      LAYER Metal2 ;
        RECT  555.16 0 555.56 0.4 ;
    END
  END issue_o.operand[115]
  PIN issue_o.operand[116]
    DIRECTION OUTPUT ;
    USE SIGNAL ;
    PORT
      LAYER Metal2 ;
        RECT  557.08 0 557.48 0.4 ;
    END
  END issue_o.operand[116]
  PIN issue_o.operand[117]
    DIRECTION OUTPUT ;
    USE SIGNAL ;
    PORT
      LAYER Metal2 ;
        RECT  559 0 559.4 0.4 ;
    END
  END issue_o.operand[117]
  PIN issue_o.operand[118]
    DIRECTION OUTPUT ;
    USE SIGNAL ;
    PORT
      LAYER Metal2 ;
        RECT  560.92 0 561.32 0.4 ;
    END
  END issue_o.operand[118]
  PIN issue_o.operand[119]
    DIRECTION OUTPUT ;
    USE SIGNAL ;
    PORT
      LAYER Metal2 ;
        RECT  562.84 0 563.24 0.4 ;
    END
  END issue_o.operand[119]
  PIN issue_o.operand[11]
    DIRECTION OUTPUT ;
    USE SIGNAL ;
    PORT
      LAYER Metal2 ;
        RECT  336.28 0 336.68 0.4 ;
    END
  END issue_o.operand[11]
  PIN issue_o.operand[120]
    DIRECTION OUTPUT ;
    USE SIGNAL ;
    PORT
      LAYER Metal2 ;
        RECT  564.76 0 565.16 0.4 ;
    END
  END issue_o.operand[120]
  PIN issue_o.operand[121]
    DIRECTION OUTPUT ;
    USE SIGNAL ;
    PORT
      LAYER Metal2 ;
        RECT  566.68 0 567.08 0.4 ;
    END
  END issue_o.operand[121]
  PIN issue_o.operand[122]
    DIRECTION OUTPUT ;
    USE SIGNAL ;
    PORT
      LAYER Metal2 ;
        RECT  568.6 0 569 0.4 ;
    END
  END issue_o.operand[122]
  PIN issue_o.operand[123]
    DIRECTION OUTPUT ;
    USE SIGNAL ;
    PORT
      LAYER Metal2 ;
        RECT  570.52 0 570.92 0.4 ;
    END
  END issue_o.operand[123]
  PIN issue_o.operand[124]
    DIRECTION OUTPUT ;
    USE SIGNAL ;
    PORT
      LAYER Metal2 ;
        RECT  572.44 0 572.84 0.4 ;
    END
  END issue_o.operand[124]
  PIN issue_o.operand[125]
    DIRECTION OUTPUT ;
    USE SIGNAL ;
    PORT
      LAYER Metal2 ;
        RECT  574.36 0 574.76 0.4 ;
    END
  END issue_o.operand[125]
  PIN issue_o.operand[126]
    DIRECTION OUTPUT ;
    USE SIGNAL ;
    PORT
      LAYER Metal2 ;
        RECT  576.28 0 576.68 0.4 ;
    END
  END issue_o.operand[126]
  PIN issue_o.operand[127]
    DIRECTION OUTPUT ;
    USE SIGNAL ;
    PORT
      LAYER Metal2 ;
        RECT  578.2 0 578.6 0.4 ;
    END
  END issue_o.operand[127]
  PIN issue_o.operand[128]
    DIRECTION OUTPUT ;
    USE SIGNAL ;
    PORT
      LAYER Metal2 ;
        RECT  580.12 0 580.52 0.4 ;
    END
  END issue_o.operand[128]
  PIN issue_o.operand[129]
    DIRECTION OUTPUT ;
    USE SIGNAL ;
    PORT
      LAYER Metal2 ;
        RECT  582.04 0 582.44 0.4 ;
    END
  END issue_o.operand[129]
  PIN issue_o.operand[12]
    DIRECTION OUTPUT ;
    USE SIGNAL ;
    PORT
      LAYER Metal2 ;
        RECT  339.16 0 339.56 0.4 ;
    END
  END issue_o.operand[12]
  PIN issue_o.operand[130]
    DIRECTION OUTPUT ;
    USE SIGNAL ;
    PORT
      LAYER Metal2 ;
        RECT  583.96 0 584.36 0.4 ;
    END
  END issue_o.operand[130]
  PIN issue_o.operand[131]
    DIRECTION OUTPUT ;
    USE SIGNAL ;
    PORT
      LAYER Metal2 ;
        RECT  585.88 0 586.28 0.4 ;
    END
  END issue_o.operand[131]
  PIN issue_o.operand[132]
    DIRECTION OUTPUT ;
    USE SIGNAL ;
    PORT
      LAYER Metal2 ;
        RECT  587.8 0 588.2 0.4 ;
    END
  END issue_o.operand[132]
  PIN issue_o.operand[133]
    DIRECTION OUTPUT ;
    USE SIGNAL ;
    PORT
      LAYER Metal2 ;
        RECT  589.72 0 590.12 0.4 ;
    END
  END issue_o.operand[133]
  PIN issue_o.operand[134]
    DIRECTION OUTPUT ;
    USE SIGNAL ;
    PORT
      LAYER Metal2 ;
        RECT  591.64 0 592.04 0.4 ;
    END
  END issue_o.operand[134]
  PIN issue_o.operand[135]
    DIRECTION OUTPUT ;
    USE SIGNAL ;
    PORT
      LAYER Metal2 ;
        RECT  593.56 0 593.96 0.4 ;
    END
  END issue_o.operand[135]
  PIN issue_o.operand[136]
    DIRECTION OUTPUT ;
    USE SIGNAL ;
    PORT
      LAYER Metal2 ;
        RECT  595.48 0 595.88 0.4 ;
    END
  END issue_o.operand[136]
  PIN issue_o.operand[137]
    DIRECTION OUTPUT ;
    USE SIGNAL ;
    PORT
      LAYER Metal2 ;
        RECT  597.4 0 597.8 0.4 ;
    END
  END issue_o.operand[137]
  PIN issue_o.operand[138]
    DIRECTION OUTPUT ;
    USE SIGNAL ;
    PORT
      LAYER Metal2 ;
        RECT  599.32 0 599.72 0.4 ;
    END
  END issue_o.operand[138]
  PIN issue_o.operand[139]
    DIRECTION OUTPUT ;
    USE SIGNAL ;
    PORT
      LAYER Metal2 ;
        RECT  601.24 0 601.64 0.4 ;
    END
  END issue_o.operand[139]
  PIN issue_o.operand[13]
    DIRECTION OUTPUT ;
    USE SIGNAL ;
    PORT
      LAYER Metal2 ;
        RECT  342.04 0 342.44 0.4 ;
    END
  END issue_o.operand[13]
  PIN issue_o.operand[140]
    DIRECTION OUTPUT ;
    USE SIGNAL ;
    PORT
      LAYER Metal2 ;
        RECT  603.16 0 603.56 0.4 ;
    END
  END issue_o.operand[140]
  PIN issue_o.operand[141]
    DIRECTION OUTPUT ;
    USE SIGNAL ;
    PORT
      LAYER Metal2 ;
        RECT  605.08 0 605.48 0.4 ;
    END
  END issue_o.operand[141]
  PIN issue_o.operand[142]
    DIRECTION OUTPUT ;
    USE SIGNAL ;
    PORT
      LAYER Metal2 ;
        RECT  607 0 607.4 0.4 ;
    END
  END issue_o.operand[142]
  PIN issue_o.operand[143]
    DIRECTION OUTPUT ;
    USE SIGNAL ;
    PORT
      LAYER Metal2 ;
        RECT  608.92 0 609.32 0.4 ;
    END
  END issue_o.operand[143]
  PIN issue_o.operand[144]
    DIRECTION OUTPUT ;
    USE SIGNAL ;
    PORT
      LAYER Metal2 ;
        RECT  609.88 0 610.28 0.4 ;
    END
  END issue_o.operand[144]
  PIN issue_o.operand[145]
    DIRECTION OUTPUT ;
    USE SIGNAL ;
    PORT
      LAYER Metal2 ;
        RECT  610.84 0 611.24 0.4 ;
    END
  END issue_o.operand[145]
  PIN issue_o.operand[146]
    DIRECTION OUTPUT ;
    USE SIGNAL ;
    PORT
      LAYER Metal2 ;
        RECT  611.8 0 612.2 0.4 ;
    END
  END issue_o.operand[146]
  PIN issue_o.operand[147]
    DIRECTION OUTPUT ;
    USE SIGNAL ;
    PORT
      LAYER Metal2 ;
        RECT  612.76 0 613.16 0.4 ;
    END
  END issue_o.operand[147]
  PIN issue_o.operand[148]
    DIRECTION OUTPUT ;
    USE SIGNAL ;
    PORT
      LAYER Metal2 ;
        RECT  613.72 0 614.12 0.4 ;
    END
  END issue_o.operand[148]
  PIN issue_o.operand[149]
    DIRECTION OUTPUT ;
    USE SIGNAL ;
    PORT
      LAYER Metal2 ;
        RECT  614.68 0 615.08 0.4 ;
    END
  END issue_o.operand[149]
  PIN issue_o.operand[14]
    DIRECTION OUTPUT ;
    USE SIGNAL ;
    PORT
      LAYER Metal2 ;
        RECT  344.92 0 345.32 0.4 ;
    END
  END issue_o.operand[14]
  PIN issue_o.operand[150]
    DIRECTION OUTPUT ;
    USE SIGNAL ;
    PORT
      LAYER Metal2 ;
        RECT  615.64 0 616.04 0.4 ;
    END
  END issue_o.operand[150]
  PIN issue_o.operand[151]
    DIRECTION OUTPUT ;
    USE SIGNAL ;
    PORT
      LAYER Metal2 ;
        RECT  616.6 0 617 0.4 ;
    END
  END issue_o.operand[151]
  PIN issue_o.operand[152]
    DIRECTION OUTPUT ;
    USE SIGNAL ;
    PORT
      LAYER Metal2 ;
        RECT  617.56 0 617.96 0.4 ;
    END
  END issue_o.operand[152]
  PIN issue_o.operand[153]
    DIRECTION OUTPUT ;
    USE SIGNAL ;
    PORT
      LAYER Metal2 ;
        RECT  618.52 0 618.92 0.4 ;
    END
  END issue_o.operand[153]
  PIN issue_o.operand[154]
    DIRECTION OUTPUT ;
    USE SIGNAL ;
    PORT
      LAYER Metal2 ;
        RECT  619.48 0 619.88 0.4 ;
    END
  END issue_o.operand[154]
  PIN issue_o.operand[155]
    DIRECTION OUTPUT ;
    USE SIGNAL ;
    PORT
      LAYER Metal2 ;
        RECT  620.44 0 620.84 0.4 ;
    END
  END issue_o.operand[155]
  PIN issue_o.operand[156]
    DIRECTION OUTPUT ;
    USE SIGNAL ;
    PORT
      LAYER Metal2 ;
        RECT  621.4 0 621.8 0.4 ;
    END
  END issue_o.operand[156]
  PIN issue_o.operand[157]
    DIRECTION OUTPUT ;
    USE SIGNAL ;
    PORT
      LAYER Metal2 ;
        RECT  622.36 0 622.76 0.4 ;
    END
  END issue_o.operand[157]
  PIN issue_o.operand[158]
    DIRECTION OUTPUT ;
    USE SIGNAL ;
    PORT
      LAYER Metal2 ;
        RECT  623.32 0 623.72 0.4 ;
    END
  END issue_o.operand[158]
  PIN issue_o.operand[159]
    DIRECTION OUTPUT ;
    USE SIGNAL ;
    PORT
      LAYER Metal2 ;
        RECT  624.28 0 624.68 0.4 ;
    END
  END issue_o.operand[159]
  PIN issue_o.operand[15]
    DIRECTION OUTPUT ;
    USE SIGNAL ;
    PORT
      LAYER Metal2 ;
        RECT  347.8 0 348.2 0.4 ;
    END
  END issue_o.operand[15]
  PIN issue_o.operand[160]
    DIRECTION OUTPUT ;
    USE SIGNAL ;
    PORT
      LAYER Metal2 ;
        RECT  625.24 0 625.64 0.4 ;
    END
  END issue_o.operand[160]
  PIN issue_o.operand[161]
    DIRECTION OUTPUT ;
    USE SIGNAL ;
    PORT
      LAYER Metal2 ;
        RECT  626.2 0 626.6 0.4 ;
    END
  END issue_o.operand[161]
  PIN issue_o.operand[162]
    DIRECTION OUTPUT ;
    USE SIGNAL ;
    PORT
      LAYER Metal2 ;
        RECT  627.16 0 627.56 0.4 ;
    END
  END issue_o.operand[162]
  PIN issue_o.operand[163]
    DIRECTION OUTPUT ;
    USE SIGNAL ;
    PORT
      LAYER Metal2 ;
        RECT  628.12 0 628.52 0.4 ;
    END
  END issue_o.operand[163]
  PIN issue_o.operand[164]
    DIRECTION OUTPUT ;
    USE SIGNAL ;
    PORT
      LAYER Metal2 ;
        RECT  629.08 0 629.48 0.4 ;
    END
  END issue_o.operand[164]
  PIN issue_o.operand[165]
    DIRECTION OUTPUT ;
    USE SIGNAL ;
    PORT
      LAYER Metal2 ;
        RECT  630.04 0 630.44 0.4 ;
    END
  END issue_o.operand[165]
  PIN issue_o.operand[166]
    DIRECTION OUTPUT ;
    USE SIGNAL ;
    PORT
      LAYER Metal2 ;
        RECT  631 0 631.4 0.4 ;
    END
  END issue_o.operand[166]
  PIN issue_o.operand[167]
    DIRECTION OUTPUT ;
    USE SIGNAL ;
    PORT
      LAYER Metal2 ;
        RECT  631.96 0 632.36 0.4 ;
    END
  END issue_o.operand[167]
  PIN issue_o.operand[168]
    DIRECTION OUTPUT ;
    USE SIGNAL ;
    PORT
      LAYER Metal2 ;
        RECT  632.92 0 633.32 0.4 ;
    END
  END issue_o.operand[168]
  PIN issue_o.operand[169]
    DIRECTION OUTPUT ;
    USE SIGNAL ;
    PORT
      LAYER Metal2 ;
        RECT  633.88 0 634.28 0.4 ;
    END
  END issue_o.operand[169]
  PIN issue_o.operand[16]
    DIRECTION OUTPUT ;
    USE SIGNAL ;
    PORT
      LAYER Metal2 ;
        RECT  350.68 0 351.08 0.4 ;
    END
  END issue_o.operand[16]
  PIN issue_o.operand[170]
    DIRECTION OUTPUT ;
    USE SIGNAL ;
    PORT
      LAYER Metal2 ;
        RECT  634.84 0 635.24 0.4 ;
    END
  END issue_o.operand[170]
  PIN issue_o.operand[171]
    DIRECTION OUTPUT ;
    USE SIGNAL ;
    PORT
      LAYER Metal2 ;
        RECT  635.8 0 636.2 0.4 ;
    END
  END issue_o.operand[171]
  PIN issue_o.operand[172]
    DIRECTION OUTPUT ;
    USE SIGNAL ;
    PORT
      LAYER Metal2 ;
        RECT  636.76 0 637.16 0.4 ;
    END
  END issue_o.operand[172]
  PIN issue_o.operand[173]
    DIRECTION OUTPUT ;
    USE SIGNAL ;
    PORT
      LAYER Metal2 ;
        RECT  637.72 0 638.12 0.4 ;
    END
  END issue_o.operand[173]
  PIN issue_o.operand[174]
    DIRECTION OUTPUT ;
    USE SIGNAL ;
    PORT
      LAYER Metal2 ;
        RECT  638.68 0 639.08 0.4 ;
    END
  END issue_o.operand[174]
  PIN issue_o.operand[175]
    DIRECTION OUTPUT ;
    USE SIGNAL ;
    PORT
      LAYER Metal2 ;
        RECT  639.64 0 640.04 0.4 ;
    END
  END issue_o.operand[175]
  PIN issue_o.operand[176]
    DIRECTION OUTPUT ;
    USE SIGNAL ;
    PORT
      LAYER Metal2 ;
        RECT  640.6 0 641 0.4 ;
    END
  END issue_o.operand[176]
  PIN issue_o.operand[177]
    DIRECTION OUTPUT ;
    USE SIGNAL ;
    PORT
      LAYER Metal2 ;
        RECT  641.56 0 641.96 0.4 ;
    END
  END issue_o.operand[177]
  PIN issue_o.operand[178]
    DIRECTION OUTPUT ;
    USE SIGNAL ;
    PORT
      LAYER Metal2 ;
        RECT  642.52 0 642.92 0.4 ;
    END
  END issue_o.operand[178]
  PIN issue_o.operand[179]
    DIRECTION OUTPUT ;
    USE SIGNAL ;
    PORT
      LAYER Metal2 ;
        RECT  643.48 0 643.88 0.4 ;
    END
  END issue_o.operand[179]
  PIN issue_o.operand[17]
    DIRECTION OUTPUT ;
    USE SIGNAL ;
    PORT
      LAYER Metal2 ;
        RECT  353.56 0 353.96 0.4 ;
    END
  END issue_o.operand[17]
  PIN issue_o.operand[180]
    DIRECTION OUTPUT ;
    USE SIGNAL ;
    PORT
      LAYER Metal2 ;
        RECT  644.44 0 644.84 0.4 ;
    END
  END issue_o.operand[180]
  PIN issue_o.operand[181]
    DIRECTION OUTPUT ;
    USE SIGNAL ;
    PORT
      LAYER Metal2 ;
        RECT  645.4 0 645.8 0.4 ;
    END
  END issue_o.operand[181]
  PIN issue_o.operand[182]
    DIRECTION OUTPUT ;
    USE SIGNAL ;
    PORT
      LAYER Metal2 ;
        RECT  646.36 0 646.76 0.4 ;
    END
  END issue_o.operand[182]
  PIN issue_o.operand[183]
    DIRECTION OUTPUT ;
    USE SIGNAL ;
    PORT
      LAYER Metal2 ;
        RECT  647.32 0 647.72 0.4 ;
    END
  END issue_o.operand[183]
  PIN issue_o.operand[184]
    DIRECTION OUTPUT ;
    USE SIGNAL ;
    PORT
      LAYER Metal2 ;
        RECT  648.28 0 648.68 0.4 ;
    END
  END issue_o.operand[184]
  PIN issue_o.operand[185]
    DIRECTION OUTPUT ;
    USE SIGNAL ;
    PORT
      LAYER Metal2 ;
        RECT  649.24 0 649.64 0.4 ;
    END
  END issue_o.operand[185]
  PIN issue_o.operand[186]
    DIRECTION OUTPUT ;
    USE SIGNAL ;
    PORT
      LAYER Metal2 ;
        RECT  650.2 0 650.6 0.4 ;
    END
  END issue_o.operand[186]
  PIN issue_o.operand[187]
    DIRECTION OUTPUT ;
    USE SIGNAL ;
    PORT
      LAYER Metal2 ;
        RECT  651.16 0 651.56 0.4 ;
    END
  END issue_o.operand[187]
  PIN issue_o.operand[188]
    DIRECTION OUTPUT ;
    USE SIGNAL ;
    PORT
      LAYER Metal2 ;
        RECT  652.12 0 652.52 0.4 ;
    END
  END issue_o.operand[188]
  PIN issue_o.operand[189]
    DIRECTION OUTPUT ;
    USE SIGNAL ;
    PORT
      LAYER Metal2 ;
        RECT  653.08 0 653.48 0.4 ;
    END
  END issue_o.operand[189]
  PIN issue_o.operand[18]
    DIRECTION OUTPUT ;
    USE SIGNAL ;
    PORT
      LAYER Metal2 ;
        RECT  356.44 0 356.84 0.4 ;
    END
  END issue_o.operand[18]
  PIN issue_o.operand[190]
    DIRECTION OUTPUT ;
    USE SIGNAL ;
    PORT
      LAYER Metal2 ;
        RECT  654.04 0 654.44 0.4 ;
    END
  END issue_o.operand[190]
  PIN issue_o.operand[191]
    DIRECTION OUTPUT ;
    USE SIGNAL ;
    PORT
      LAYER Metal2 ;
        RECT  655 0 655.4 0.4 ;
    END
  END issue_o.operand[191]
  PIN issue_o.operand[192]
    DIRECTION OUTPUT ;
    USE SIGNAL ;
    PORT
      LAYER Metal2 ;
        RECT  655.96 0 656.36 0.4 ;
    END
  END issue_o.operand[192]
  PIN issue_o.operand[193]
    DIRECTION OUTPUT ;
    USE SIGNAL ;
    PORT
      LAYER Metal2 ;
        RECT  656.92 0 657.32 0.4 ;
    END
  END issue_o.operand[193]
  PIN issue_o.operand[194]
    DIRECTION OUTPUT ;
    USE SIGNAL ;
    PORT
      LAYER Metal2 ;
        RECT  657.88 0 658.28 0.4 ;
    END
  END issue_o.operand[194]
  PIN issue_o.operand[195]
    DIRECTION OUTPUT ;
    USE SIGNAL ;
    PORT
      LAYER Metal2 ;
        RECT  658.84 0 659.24 0.4 ;
    END
  END issue_o.operand[195]
  PIN issue_o.operand[196]
    DIRECTION OUTPUT ;
    USE SIGNAL ;
    PORT
      LAYER Metal2 ;
        RECT  659.8 0 660.2 0.4 ;
    END
  END issue_o.operand[196]
  PIN issue_o.operand[197]
    DIRECTION OUTPUT ;
    USE SIGNAL ;
    PORT
      LAYER Metal2 ;
        RECT  660.76 0 661.16 0.4 ;
    END
  END issue_o.operand[197]
  PIN issue_o.operand[198]
    DIRECTION OUTPUT ;
    USE SIGNAL ;
    PORT
      LAYER Metal2 ;
        RECT  661.72 0 662.12 0.4 ;
    END
  END issue_o.operand[198]
  PIN issue_o.operand[199]
    DIRECTION OUTPUT ;
    USE SIGNAL ;
    PORT
      LAYER Metal2 ;
        RECT  662.68 0 663.08 0.4 ;
    END
  END issue_o.operand[199]
  PIN issue_o.operand[19]
    DIRECTION OUTPUT ;
    USE SIGNAL ;
    PORT
      LAYER Metal2 ;
        RECT  359.32 0 359.72 0.4 ;
    END
  END issue_o.operand[19]
  PIN issue_o.operand[1]
    DIRECTION OUTPUT ;
    USE SIGNAL ;
    PORT
      LAYER Metal2 ;
        RECT  304.6 0 305 0.4 ;
    END
  END issue_o.operand[1]
  PIN issue_o.operand[200]
    DIRECTION OUTPUT ;
    USE SIGNAL ;
    PORT
      LAYER Metal2 ;
        RECT  663.64 0 664.04 0.4 ;
    END
  END issue_o.operand[200]
  PIN issue_o.operand[201]
    DIRECTION OUTPUT ;
    USE SIGNAL ;
    PORT
      LAYER Metal2 ;
        RECT  664.6 0 665 0.4 ;
    END
  END issue_o.operand[201]
  PIN issue_o.operand[202]
    DIRECTION OUTPUT ;
    USE SIGNAL ;
    PORT
      LAYER Metal2 ;
        RECT  665.56 0 665.96 0.4 ;
    END
  END issue_o.operand[202]
  PIN issue_o.operand[203]
    DIRECTION OUTPUT ;
    USE SIGNAL ;
    PORT
      LAYER Metal2 ;
        RECT  666.52 0 666.92 0.4 ;
    END
  END issue_o.operand[203]
  PIN issue_o.operand[204]
    DIRECTION OUTPUT ;
    USE SIGNAL ;
    PORT
      LAYER Metal2 ;
        RECT  667.48 0 667.88 0.4 ;
    END
  END issue_o.operand[204]
  PIN issue_o.operand[205]
    DIRECTION OUTPUT ;
    USE SIGNAL ;
    PORT
      LAYER Metal2 ;
        RECT  668.44 0 668.84 0.4 ;
    END
  END issue_o.operand[205]
  PIN issue_o.operand[206]
    DIRECTION OUTPUT ;
    USE SIGNAL ;
    PORT
      LAYER Metal2 ;
        RECT  669.4 0 669.8 0.4 ;
    END
  END issue_o.operand[206]
  PIN issue_o.operand[207]
    DIRECTION OUTPUT ;
    USE SIGNAL ;
    PORT
      LAYER Metal2 ;
        RECT  670.36 0 670.76 0.4 ;
    END
  END issue_o.operand[207]
  PIN issue_o.operand[208]
    DIRECTION OUTPUT ;
    USE SIGNAL ;
    PORT
      LAYER Metal2 ;
        RECT  671.32 0 671.72 0.4 ;
    END
  END issue_o.operand[208]
  PIN issue_o.operand[209]
    DIRECTION OUTPUT ;
    USE SIGNAL ;
    PORT
      LAYER Metal2 ;
        RECT  672.28 0 672.68 0.4 ;
    END
  END issue_o.operand[209]
  PIN issue_o.operand[20]
    DIRECTION OUTPUT ;
    USE SIGNAL ;
    PORT
      LAYER Metal2 ;
        RECT  362.2 0 362.6 0.4 ;
    END
  END issue_o.operand[20]
  PIN issue_o.operand[210]
    DIRECTION OUTPUT ;
    USE SIGNAL ;
    PORT
      LAYER Metal2 ;
        RECT  673.24 0 673.64 0.4 ;
    END
  END issue_o.operand[210]
  PIN issue_o.operand[211]
    DIRECTION OUTPUT ;
    USE SIGNAL ;
    PORT
      LAYER Metal2 ;
        RECT  674.2 0 674.6 0.4 ;
    END
  END issue_o.operand[211]
  PIN issue_o.operand[212]
    DIRECTION OUTPUT ;
    USE SIGNAL ;
    PORT
      LAYER Metal2 ;
        RECT  675.16 0 675.56 0.4 ;
    END
  END issue_o.operand[212]
  PIN issue_o.operand[213]
    DIRECTION OUTPUT ;
    USE SIGNAL ;
    PORT
      LAYER Metal2 ;
        RECT  676.12 0 676.52 0.4 ;
    END
  END issue_o.operand[213]
  PIN issue_o.operand[214]
    DIRECTION OUTPUT ;
    USE SIGNAL ;
    PORT
      LAYER Metal2 ;
        RECT  677.08 0 677.48 0.4 ;
    END
  END issue_o.operand[214]
  PIN issue_o.operand[215]
    DIRECTION OUTPUT ;
    USE SIGNAL ;
    PORT
      LAYER Metal2 ;
        RECT  678.04 0 678.44 0.4 ;
    END
  END issue_o.operand[215]
  PIN issue_o.operand[216]
    DIRECTION OUTPUT ;
    USE SIGNAL ;
    PORT
      LAYER Metal2 ;
        RECT  679 0 679.4 0.4 ;
    END
  END issue_o.operand[216]
  PIN issue_o.operand[217]
    DIRECTION OUTPUT ;
    USE SIGNAL ;
    PORT
      LAYER Metal2 ;
        RECT  679.96 0 680.36 0.4 ;
    END
  END issue_o.operand[217]
  PIN issue_o.operand[218]
    DIRECTION OUTPUT ;
    USE SIGNAL ;
    PORT
      LAYER Metal2 ;
        RECT  680.92 0 681.32 0.4 ;
    END
  END issue_o.operand[218]
  PIN issue_o.operand[219]
    DIRECTION OUTPUT ;
    USE SIGNAL ;
    PORT
      LAYER Metal2 ;
        RECT  681.88 0 682.28 0.4 ;
    END
  END issue_o.operand[219]
  PIN issue_o.operand[21]
    DIRECTION OUTPUT ;
    USE SIGNAL ;
    PORT
      LAYER Metal2 ;
        RECT  365.08 0 365.48 0.4 ;
    END
  END issue_o.operand[21]
  PIN issue_o.operand[220]
    DIRECTION OUTPUT ;
    USE SIGNAL ;
    PORT
      LAYER Metal2 ;
        RECT  682.84 0 683.24 0.4 ;
    END
  END issue_o.operand[220]
  PIN issue_o.operand[221]
    DIRECTION OUTPUT ;
    USE SIGNAL ;
    PORT
      LAYER Metal2 ;
        RECT  683.8 0 684.2 0.4 ;
    END
  END issue_o.operand[221]
  PIN issue_o.operand[222]
    DIRECTION OUTPUT ;
    USE SIGNAL ;
    PORT
      LAYER Metal2 ;
        RECT  684.76 0 685.16 0.4 ;
    END
  END issue_o.operand[222]
  PIN issue_o.operand[223]
    DIRECTION OUTPUT ;
    USE SIGNAL ;
    PORT
      LAYER Metal2 ;
        RECT  685.72 0 686.12 0.4 ;
    END
  END issue_o.operand[223]
  PIN issue_o.operand[224]
    DIRECTION OUTPUT ;
    USE SIGNAL ;
    PORT
      LAYER Metal2 ;
        RECT  686.68 0 687.08 0.4 ;
    END
  END issue_o.operand[224]
  PIN issue_o.operand[225]
    DIRECTION OUTPUT ;
    USE SIGNAL ;
    PORT
      LAYER Metal2 ;
        RECT  687.64 0 688.04 0.4 ;
    END
  END issue_o.operand[225]
  PIN issue_o.operand[226]
    DIRECTION OUTPUT ;
    USE SIGNAL ;
    PORT
      LAYER Metal2 ;
        RECT  688.6 0 689 0.4 ;
    END
  END issue_o.operand[226]
  PIN issue_o.operand[227]
    DIRECTION OUTPUT ;
    USE SIGNAL ;
    PORT
      LAYER Metal2 ;
        RECT  689.56 0 689.96 0.4 ;
    END
  END issue_o.operand[227]
  PIN issue_o.operand[228]
    DIRECTION OUTPUT ;
    USE SIGNAL ;
    PORT
      LAYER Metal2 ;
        RECT  690.52 0 690.92 0.4 ;
    END
  END issue_o.operand[228]
  PIN issue_o.operand[229]
    DIRECTION OUTPUT ;
    USE SIGNAL ;
    PORT
      LAYER Metal2 ;
        RECT  691.48 0 691.88 0.4 ;
    END
  END issue_o.operand[229]
  PIN issue_o.operand[22]
    DIRECTION OUTPUT ;
    USE SIGNAL ;
    PORT
      LAYER Metal2 ;
        RECT  367.96 0 368.36 0.4 ;
    END
  END issue_o.operand[22]
  PIN issue_o.operand[230]
    DIRECTION OUTPUT ;
    USE SIGNAL ;
    PORT
      LAYER Metal2 ;
        RECT  692.44 0 692.84 0.4 ;
    END
  END issue_o.operand[230]
  PIN issue_o.operand[231]
    DIRECTION OUTPUT ;
    USE SIGNAL ;
    PORT
      LAYER Metal2 ;
        RECT  693.4 0 693.8 0.4 ;
    END
  END issue_o.operand[231]
  PIN issue_o.operand[232]
    DIRECTION OUTPUT ;
    USE SIGNAL ;
    PORT
      LAYER Metal2 ;
        RECT  694.36 0 694.76 0.4 ;
    END
  END issue_o.operand[232]
  PIN issue_o.operand[233]
    DIRECTION OUTPUT ;
    USE SIGNAL ;
    PORT
      LAYER Metal2 ;
        RECT  695.32 0 695.72 0.4 ;
    END
  END issue_o.operand[233]
  PIN issue_o.operand[234]
    DIRECTION OUTPUT ;
    USE SIGNAL ;
    PORT
      LAYER Metal2 ;
        RECT  696.28 0 696.68 0.4 ;
    END
  END issue_o.operand[234]
  PIN issue_o.operand[235]
    DIRECTION OUTPUT ;
    USE SIGNAL ;
    PORT
      LAYER Metal2 ;
        RECT  697.24 0 697.64 0.4 ;
    END
  END issue_o.operand[235]
  PIN issue_o.operand[236]
    DIRECTION OUTPUT ;
    USE SIGNAL ;
    PORT
      LAYER Metal2 ;
        RECT  698.2 0 698.6 0.4 ;
    END
  END issue_o.operand[236]
  PIN issue_o.operand[237]
    DIRECTION OUTPUT ;
    USE SIGNAL ;
    PORT
      LAYER Metal2 ;
        RECT  699.16 0 699.56 0.4 ;
    END
  END issue_o.operand[237]
  PIN issue_o.operand[238]
    DIRECTION OUTPUT ;
    USE SIGNAL ;
    PORT
      LAYER Metal2 ;
        RECT  700.12 0 700.52 0.4 ;
    END
  END issue_o.operand[238]
  PIN issue_o.operand[239]
    DIRECTION OUTPUT ;
    USE SIGNAL ;
    PORT
      LAYER Metal2 ;
        RECT  701.08 0 701.48 0.4 ;
    END
  END issue_o.operand[239]
  PIN issue_o.operand[23]
    DIRECTION OUTPUT ;
    USE SIGNAL ;
    PORT
      LAYER Metal2 ;
        RECT  370.84 0 371.24 0.4 ;
    END
  END issue_o.operand[23]
  PIN issue_o.operand[240]
    DIRECTION OUTPUT ;
    USE SIGNAL ;
    PORT
      LAYER Metal2 ;
        RECT  702.04 0 702.44 0.4 ;
    END
  END issue_o.operand[240]
  PIN issue_o.operand[241]
    DIRECTION OUTPUT ;
    USE SIGNAL ;
    PORT
      LAYER Metal2 ;
        RECT  703 0 703.4 0.4 ;
    END
  END issue_o.operand[241]
  PIN issue_o.operand[242]
    DIRECTION OUTPUT ;
    USE SIGNAL ;
    PORT
      LAYER Metal2 ;
        RECT  703.96 0 704.36 0.4 ;
    END
  END issue_o.operand[242]
  PIN issue_o.operand[243]
    DIRECTION OUTPUT ;
    USE SIGNAL ;
    PORT
      LAYER Metal2 ;
        RECT  704.92 0 705.32 0.4 ;
    END
  END issue_o.operand[243]
  PIN issue_o.operand[244]
    DIRECTION OUTPUT ;
    USE SIGNAL ;
    PORT
      LAYER Metal2 ;
        RECT  705.88 0 706.28 0.4 ;
    END
  END issue_o.operand[244]
  PIN issue_o.operand[245]
    DIRECTION OUTPUT ;
    USE SIGNAL ;
    PORT
      LAYER Metal2 ;
        RECT  706.84 0 707.24 0.4 ;
    END
  END issue_o.operand[245]
  PIN issue_o.operand[246]
    DIRECTION OUTPUT ;
    USE SIGNAL ;
    PORT
      LAYER Metal2 ;
        RECT  707.8 0 708.2 0.4 ;
    END
  END issue_o.operand[246]
  PIN issue_o.operand[247]
    DIRECTION OUTPUT ;
    USE SIGNAL ;
    PORT
      LAYER Metal2 ;
        RECT  708.76 0 709.16 0.4 ;
    END
  END issue_o.operand[247]
  PIN issue_o.operand[248]
    DIRECTION OUTPUT ;
    USE SIGNAL ;
    PORT
      LAYER Metal2 ;
        RECT  709.72 0 710.12 0.4 ;
    END
  END issue_o.operand[248]
  PIN issue_o.operand[249]
    DIRECTION OUTPUT ;
    USE SIGNAL ;
    PORT
      LAYER Metal2 ;
        RECT  710.68 0 711.08 0.4 ;
    END
  END issue_o.operand[249]
  PIN issue_o.operand[24]
    DIRECTION OUTPUT ;
    USE SIGNAL ;
    PORT
      LAYER Metal2 ;
        RECT  373.72 0 374.12 0.4 ;
    END
  END issue_o.operand[24]
  PIN issue_o.operand[250]
    DIRECTION OUTPUT ;
    USE SIGNAL ;
    PORT
      LAYER Metal2 ;
        RECT  711.64 0 712.04 0.4 ;
    END
  END issue_o.operand[250]
  PIN issue_o.operand[251]
    DIRECTION OUTPUT ;
    USE SIGNAL ;
    PORT
      LAYER Metal2 ;
        RECT  712.6 0 713 0.4 ;
    END
  END issue_o.operand[251]
  PIN issue_o.operand[252]
    DIRECTION OUTPUT ;
    USE SIGNAL ;
    PORT
      LAYER Metal2 ;
        RECT  713.56 0 713.96 0.4 ;
    END
  END issue_o.operand[252]
  PIN issue_o.operand[253]
    DIRECTION OUTPUT ;
    USE SIGNAL ;
    PORT
      LAYER Metal2 ;
        RECT  714.52 0 714.92 0.4 ;
    END
  END issue_o.operand[253]
  PIN issue_o.operand[254]
    DIRECTION OUTPUT ;
    USE SIGNAL ;
    PORT
      LAYER Metal2 ;
        RECT  715.48 0 715.88 0.4 ;
    END
  END issue_o.operand[254]
  PIN issue_o.operand[255]
    DIRECTION OUTPUT ;
    USE SIGNAL ;
    PORT
      LAYER Metal2 ;
        RECT  716.44 0 716.84 0.4 ;
    END
  END issue_o.operand[255]
  PIN issue_o.operand[25]
    DIRECTION OUTPUT ;
    USE SIGNAL ;
    PORT
      LAYER Metal2 ;
        RECT  376.6 0 377 0.4 ;
    END
  END issue_o.operand[25]
  PIN issue_o.operand[26]
    DIRECTION OUTPUT ;
    USE SIGNAL ;
    PORT
      LAYER Metal2 ;
        RECT  379.48 0 379.88 0.4 ;
    END
  END issue_o.operand[26]
  PIN issue_o.operand[27]
    DIRECTION OUTPUT ;
    USE SIGNAL ;
    PORT
      LAYER Metal2 ;
        RECT  382.36 0 382.76 0.4 ;
    END
  END issue_o.operand[27]
  PIN issue_o.operand[28]
    DIRECTION OUTPUT ;
    USE SIGNAL ;
    PORT
      LAYER Metal2 ;
        RECT  385.24 0 385.64 0.4 ;
    END
  END issue_o.operand[28]
  PIN issue_o.operand[29]
    DIRECTION OUTPUT ;
    USE SIGNAL ;
    PORT
      LAYER Metal2 ;
        RECT  388.12 0 388.52 0.4 ;
    END
  END issue_o.operand[29]
  PIN issue_o.operand[2]
    DIRECTION OUTPUT ;
    USE SIGNAL ;
    PORT
      LAYER Metal2 ;
        RECT  309.4 0 309.8 0.4 ;
    END
  END issue_o.operand[2]
  PIN issue_o.operand[30]
    DIRECTION OUTPUT ;
    USE SIGNAL ;
    PORT
      LAYER Metal2 ;
        RECT  391 0 391.4 0.4 ;
    END
  END issue_o.operand[30]
  PIN issue_o.operand[31]
    DIRECTION OUTPUT ;
    USE SIGNAL ;
    PORT
      LAYER Metal2 ;
        RECT  393.88 0 394.28 0.4 ;
    END
  END issue_o.operand[31]
  PIN issue_o.operand[32]
    DIRECTION OUTPUT ;
    USE SIGNAL ;
    PORT
      LAYER Metal2 ;
        RECT  395.8 0 396.2 0.4 ;
    END
  END issue_o.operand[32]
  PIN issue_o.operand[33]
    DIRECTION OUTPUT ;
    USE SIGNAL ;
    PORT
      LAYER Metal2 ;
        RECT  397.72 0 398.12 0.4 ;
    END
  END issue_o.operand[33]
  PIN issue_o.operand[34]
    DIRECTION OUTPUT ;
    USE SIGNAL ;
    PORT
      LAYER Metal2 ;
        RECT  399.64 0 400.04 0.4 ;
    END
  END issue_o.operand[34]
  PIN issue_o.operand[35]
    DIRECTION OUTPUT ;
    USE SIGNAL ;
    PORT
      LAYER Metal2 ;
        RECT  401.56 0 401.96 0.4 ;
    END
  END issue_o.operand[35]
  PIN issue_o.operand[36]
    DIRECTION OUTPUT ;
    USE SIGNAL ;
    PORT
      LAYER Metal2 ;
        RECT  403.48 0 403.88 0.4 ;
    END
  END issue_o.operand[36]
  PIN issue_o.operand[37]
    DIRECTION OUTPUT ;
    USE SIGNAL ;
    PORT
      LAYER Metal2 ;
        RECT  405.4 0 405.8 0.4 ;
    END
  END issue_o.operand[37]
  PIN issue_o.operand[38]
    DIRECTION OUTPUT ;
    USE SIGNAL ;
    PORT
      LAYER Metal2 ;
        RECT  407.32 0 407.72 0.4 ;
    END
  END issue_o.operand[38]
  PIN issue_o.operand[39]
    DIRECTION OUTPUT ;
    USE SIGNAL ;
    PORT
      LAYER Metal2 ;
        RECT  409.24 0 409.64 0.4 ;
    END
  END issue_o.operand[39]
  PIN issue_o.operand[3]
    DIRECTION OUTPUT ;
    USE SIGNAL ;
    PORT
      LAYER Metal2 ;
        RECT  313.24 0 313.64 0.4 ;
    END
  END issue_o.operand[3]
  PIN issue_o.operand[40]
    DIRECTION OUTPUT ;
    USE SIGNAL ;
    PORT
      LAYER Metal2 ;
        RECT  411.16 0 411.56 0.4 ;
    END
  END issue_o.operand[40]
  PIN issue_o.operand[41]
    DIRECTION OUTPUT ;
    USE SIGNAL ;
    PORT
      LAYER Metal2 ;
        RECT  413.08 0 413.48 0.4 ;
    END
  END issue_o.operand[41]
  PIN issue_o.operand[42]
    DIRECTION OUTPUT ;
    USE SIGNAL ;
    PORT
      LAYER Metal2 ;
        RECT  415 0 415.4 0.4 ;
    END
  END issue_o.operand[42]
  PIN issue_o.operand[43]
    DIRECTION OUTPUT ;
    USE SIGNAL ;
    PORT
      LAYER Metal2 ;
        RECT  416.92 0 417.32 0.4 ;
    END
  END issue_o.operand[43]
  PIN issue_o.operand[44]
    DIRECTION OUTPUT ;
    USE SIGNAL ;
    PORT
      LAYER Metal2 ;
        RECT  418.84 0 419.24 0.4 ;
    END
  END issue_o.operand[44]
  PIN issue_o.operand[45]
    DIRECTION OUTPUT ;
    USE SIGNAL ;
    PORT
      LAYER Metal2 ;
        RECT  420.76 0 421.16 0.4 ;
    END
  END issue_o.operand[45]
  PIN issue_o.operand[46]
    DIRECTION OUTPUT ;
    USE SIGNAL ;
    PORT
      LAYER Metal2 ;
        RECT  422.68 0 423.08 0.4 ;
    END
  END issue_o.operand[46]
  PIN issue_o.operand[47]
    DIRECTION OUTPUT ;
    USE SIGNAL ;
    PORT
      LAYER Metal2 ;
        RECT  424.6 0 425 0.4 ;
    END
  END issue_o.operand[47]
  PIN issue_o.operand[48]
    DIRECTION OUTPUT ;
    USE SIGNAL ;
    PORT
      LAYER Metal2 ;
        RECT  426.52 0 426.92 0.4 ;
    END
  END issue_o.operand[48]
  PIN issue_o.operand[49]
    DIRECTION OUTPUT ;
    USE SIGNAL ;
    PORT
      LAYER Metal2 ;
        RECT  428.44 0 428.84 0.4 ;
    END
  END issue_o.operand[49]
  PIN issue_o.operand[4]
    DIRECTION OUTPUT ;
    USE SIGNAL ;
    PORT
      LAYER Metal2 ;
        RECT  316.12 0 316.52 0.4 ;
    END
  END issue_o.operand[4]
  PIN issue_o.operand[50]
    DIRECTION OUTPUT ;
    USE SIGNAL ;
    PORT
      LAYER Metal2 ;
        RECT  430.36 0 430.76 0.4 ;
    END
  END issue_o.operand[50]
  PIN issue_o.operand[51]
    DIRECTION OUTPUT ;
    USE SIGNAL ;
    PORT
      LAYER Metal2 ;
        RECT  432.28 0 432.68 0.4 ;
    END
  END issue_o.operand[51]
  PIN issue_o.operand[52]
    DIRECTION OUTPUT ;
    USE SIGNAL ;
    PORT
      LAYER Metal2 ;
        RECT  434.2 0 434.6 0.4 ;
    END
  END issue_o.operand[52]
  PIN issue_o.operand[53]
    DIRECTION OUTPUT ;
    USE SIGNAL ;
    PORT
      LAYER Metal2 ;
        RECT  436.12 0 436.52 0.4 ;
    END
  END issue_o.operand[53]
  PIN issue_o.operand[54]
    DIRECTION OUTPUT ;
    USE SIGNAL ;
    PORT
      LAYER Metal2 ;
        RECT  438.04 0 438.44 0.4 ;
    END
  END issue_o.operand[54]
  PIN issue_o.operand[55]
    DIRECTION OUTPUT ;
    USE SIGNAL ;
    PORT
      LAYER Metal2 ;
        RECT  439.96 0 440.36 0.4 ;
    END
  END issue_o.operand[55]
  PIN issue_o.operand[56]
    DIRECTION OUTPUT ;
    USE SIGNAL ;
    PORT
      LAYER Metal2 ;
        RECT  441.88 0 442.28 0.4 ;
    END
  END issue_o.operand[56]
  PIN issue_o.operand[57]
    DIRECTION OUTPUT ;
    USE SIGNAL ;
    PORT
      LAYER Metal2 ;
        RECT  443.8 0 444.2 0.4 ;
    END
  END issue_o.operand[57]
  PIN issue_o.operand[58]
    DIRECTION OUTPUT ;
    USE SIGNAL ;
    PORT
      LAYER Metal2 ;
        RECT  445.72 0 446.12 0.4 ;
    END
  END issue_o.operand[58]
  PIN issue_o.operand[59]
    DIRECTION OUTPUT ;
    USE SIGNAL ;
    PORT
      LAYER Metal2 ;
        RECT  447.64 0 448.04 0.4 ;
    END
  END issue_o.operand[59]
  PIN issue_o.operand[5]
    DIRECTION OUTPUT ;
    USE SIGNAL ;
    PORT
      LAYER Metal2 ;
        RECT  319 0 319.4 0.4 ;
    END
  END issue_o.operand[5]
  PIN issue_o.operand[60]
    DIRECTION OUTPUT ;
    USE SIGNAL ;
    PORT
      LAYER Metal2 ;
        RECT  449.56 0 449.96 0.4 ;
    END
  END issue_o.operand[60]
  PIN issue_o.operand[61]
    DIRECTION OUTPUT ;
    USE SIGNAL ;
    PORT
      LAYER Metal2 ;
        RECT  451.48 0 451.88 0.4 ;
    END
  END issue_o.operand[61]
  PIN issue_o.operand[62]
    DIRECTION OUTPUT ;
    USE SIGNAL ;
    PORT
      LAYER Metal2 ;
        RECT  453.4 0 453.8 0.4 ;
    END
  END issue_o.operand[62]
  PIN issue_o.operand[63]
    DIRECTION OUTPUT ;
    USE SIGNAL ;
    PORT
      LAYER Metal2 ;
        RECT  455.32 0 455.72 0.4 ;
    END
  END issue_o.operand[63]
  PIN issue_o.operand[64]
    DIRECTION OUTPUT ;
    USE SIGNAL ;
    PORT
      LAYER Metal2 ;
        RECT  457.24 0 457.64 0.4 ;
    END
  END issue_o.operand[64]
  PIN issue_o.operand[65]
    DIRECTION OUTPUT ;
    USE SIGNAL ;
    PORT
      LAYER Metal2 ;
        RECT  459.16 0 459.56 0.4 ;
    END
  END issue_o.operand[65]
  PIN issue_o.operand[66]
    DIRECTION OUTPUT ;
    USE SIGNAL ;
    PORT
      LAYER Metal2 ;
        RECT  461.08 0 461.48 0.4 ;
    END
  END issue_o.operand[66]
  PIN issue_o.operand[67]
    DIRECTION OUTPUT ;
    USE SIGNAL ;
    PORT
      LAYER Metal2 ;
        RECT  463 0 463.4 0.4 ;
    END
  END issue_o.operand[67]
  PIN issue_o.operand[68]
    DIRECTION OUTPUT ;
    USE SIGNAL ;
    PORT
      LAYER Metal2 ;
        RECT  464.92 0 465.32 0.4 ;
    END
  END issue_o.operand[68]
  PIN issue_o.operand[69]
    DIRECTION OUTPUT ;
    USE SIGNAL ;
    PORT
      LAYER Metal2 ;
        RECT  466.84 0 467.24 0.4 ;
    END
  END issue_o.operand[69]
  PIN issue_o.operand[6]
    DIRECTION OUTPUT ;
    USE SIGNAL ;
    PORT
      LAYER Metal2 ;
        RECT  321.88 0 322.28 0.4 ;
    END
  END issue_o.operand[6]
  PIN issue_o.operand[70]
    DIRECTION OUTPUT ;
    USE SIGNAL ;
    PORT
      LAYER Metal2 ;
        RECT  468.76 0 469.16 0.4 ;
    END
  END issue_o.operand[70]
  PIN issue_o.operand[71]
    DIRECTION OUTPUT ;
    USE SIGNAL ;
    PORT
      LAYER Metal2 ;
        RECT  470.68 0 471.08 0.4 ;
    END
  END issue_o.operand[71]
  PIN issue_o.operand[72]
    DIRECTION OUTPUT ;
    USE SIGNAL ;
    PORT
      LAYER Metal2 ;
        RECT  472.6 0 473 0.4 ;
    END
  END issue_o.operand[72]
  PIN issue_o.operand[73]
    DIRECTION OUTPUT ;
    USE SIGNAL ;
    PORT
      LAYER Metal2 ;
        RECT  474.52 0 474.92 0.4 ;
    END
  END issue_o.operand[73]
  PIN issue_o.operand[74]
    DIRECTION OUTPUT ;
    USE SIGNAL ;
    PORT
      LAYER Metal2 ;
        RECT  476.44 0 476.84 0.4 ;
    END
  END issue_o.operand[74]
  PIN issue_o.operand[75]
    DIRECTION OUTPUT ;
    USE SIGNAL ;
    PORT
      LAYER Metal2 ;
        RECT  478.36 0 478.76 0.4 ;
    END
  END issue_o.operand[75]
  PIN issue_o.operand[76]
    DIRECTION OUTPUT ;
    USE SIGNAL ;
    PORT
      LAYER Metal2 ;
        RECT  480.28 0 480.68 0.4 ;
    END
  END issue_o.operand[76]
  PIN issue_o.operand[77]
    DIRECTION OUTPUT ;
    USE SIGNAL ;
    PORT
      LAYER Metal2 ;
        RECT  482.2 0 482.6 0.4 ;
    END
  END issue_o.operand[77]
  PIN issue_o.operand[78]
    DIRECTION OUTPUT ;
    USE SIGNAL ;
    PORT
      LAYER Metal2 ;
        RECT  484.12 0 484.52 0.4 ;
    END
  END issue_o.operand[78]
  PIN issue_o.operand[79]
    DIRECTION OUTPUT ;
    USE SIGNAL ;
    PORT
      LAYER Metal2 ;
        RECT  486.04 0 486.44 0.4 ;
    END
  END issue_o.operand[79]
  PIN issue_o.operand[7]
    DIRECTION OUTPUT ;
    USE SIGNAL ;
    PORT
      LAYER Metal2 ;
        RECT  324.76 0 325.16 0.4 ;
    END
  END issue_o.operand[7]
  PIN issue_o.operand[80]
    DIRECTION OUTPUT ;
    USE SIGNAL ;
    PORT
      LAYER Metal2 ;
        RECT  487.96 0 488.36 0.4 ;
    END
  END issue_o.operand[80]
  PIN issue_o.operand[81]
    DIRECTION OUTPUT ;
    USE SIGNAL ;
    PORT
      LAYER Metal2 ;
        RECT  489.88 0 490.28 0.4 ;
    END
  END issue_o.operand[81]
  PIN issue_o.operand[82]
    DIRECTION OUTPUT ;
    USE SIGNAL ;
    PORT
      LAYER Metal2 ;
        RECT  491.8 0 492.2 0.4 ;
    END
  END issue_o.operand[82]
  PIN issue_o.operand[83]
    DIRECTION OUTPUT ;
    USE SIGNAL ;
    PORT
      LAYER Metal2 ;
        RECT  493.72 0 494.12 0.4 ;
    END
  END issue_o.operand[83]
  PIN issue_o.operand[84]
    DIRECTION OUTPUT ;
    USE SIGNAL ;
    PORT
      LAYER Metal2 ;
        RECT  495.64 0 496.04 0.4 ;
    END
  END issue_o.operand[84]
  PIN issue_o.operand[85]
    DIRECTION OUTPUT ;
    USE SIGNAL ;
    PORT
      LAYER Metal2 ;
        RECT  497.56 0 497.96 0.4 ;
    END
  END issue_o.operand[85]
  PIN issue_o.operand[86]
    DIRECTION OUTPUT ;
    USE SIGNAL ;
    PORT
      LAYER Metal2 ;
        RECT  499.48 0 499.88 0.4 ;
    END
  END issue_o.operand[86]
  PIN issue_o.operand[87]
    DIRECTION OUTPUT ;
    USE SIGNAL ;
    PORT
      LAYER Metal2 ;
        RECT  501.4 0 501.8 0.4 ;
    END
  END issue_o.operand[87]
  PIN issue_o.operand[88]
    DIRECTION OUTPUT ;
    USE SIGNAL ;
    PORT
      LAYER Metal2 ;
        RECT  503.32 0 503.72 0.4 ;
    END
  END issue_o.operand[88]
  PIN issue_o.operand[89]
    DIRECTION OUTPUT ;
    USE SIGNAL ;
    PORT
      LAYER Metal2 ;
        RECT  505.24 0 505.64 0.4 ;
    END
  END issue_o.operand[89]
  PIN issue_o.operand[8]
    DIRECTION OUTPUT ;
    USE SIGNAL ;
    PORT
      LAYER Metal2 ;
        RECT  327.64 0 328.04 0.4 ;
    END
  END issue_o.operand[8]
  PIN issue_o.operand[90]
    DIRECTION OUTPUT ;
    USE SIGNAL ;
    PORT
      LAYER Metal2 ;
        RECT  507.16 0 507.56 0.4 ;
    END
  END issue_o.operand[90]
  PIN issue_o.operand[91]
    DIRECTION OUTPUT ;
    USE SIGNAL ;
    PORT
      LAYER Metal2 ;
        RECT  509.08 0 509.48 0.4 ;
    END
  END issue_o.operand[91]
  PIN issue_o.operand[92]
    DIRECTION OUTPUT ;
    USE SIGNAL ;
    PORT
      LAYER Metal2 ;
        RECT  511 0 511.4 0.4 ;
    END
  END issue_o.operand[92]
  PIN issue_o.operand[93]
    DIRECTION OUTPUT ;
    USE SIGNAL ;
    PORT
      LAYER Metal2 ;
        RECT  512.92 0 513.32 0.4 ;
    END
  END issue_o.operand[93]
  PIN issue_o.operand[94]
    DIRECTION OUTPUT ;
    USE SIGNAL ;
    PORT
      LAYER Metal2 ;
        RECT  514.84 0 515.24 0.4 ;
    END
  END issue_o.operand[94]
  PIN issue_o.operand[95]
    DIRECTION OUTPUT ;
    USE SIGNAL ;
    PORT
      LAYER Metal2 ;
        RECT  516.76 0 517.16 0.4 ;
    END
  END issue_o.operand[95]
  PIN issue_o.operand[96]
    DIRECTION OUTPUT ;
    USE SIGNAL ;
    PORT
      LAYER Metal2 ;
        RECT  518.68 0 519.08 0.4 ;
    END
  END issue_o.operand[96]
  PIN issue_o.operand[97]
    DIRECTION OUTPUT ;
    USE SIGNAL ;
    PORT
      LAYER Metal2 ;
        RECT  520.6 0 521 0.4 ;
    END
  END issue_o.operand[97]
  PIN issue_o.operand[98]
    DIRECTION OUTPUT ;
    USE SIGNAL ;
    PORT
      LAYER Metal2 ;
        RECT  522.52 0 522.92 0.4 ;
    END
  END issue_o.operand[98]
  PIN issue_o.operand[99]
    DIRECTION OUTPUT ;
    USE SIGNAL ;
    PORT
      LAYER Metal2 ;
        RECT  524.44 0 524.84 0.4 ;
    END
  END issue_o.operand[99]
  PIN issue_o.operand[9]
    DIRECTION OUTPUT ;
    USE SIGNAL ;
    PORT
      LAYER Metal2 ;
        RECT  330.52 0 330.92 0.4 ;
    END
  END issue_o.operand[9]
  PIN issue_o.operand_count[0]
    DIRECTION OUTPUT ;
    USE SIGNAL ;
    PORT
      LAYER Metal2 ;
        RECT  300.76 0 301.16 0.4 ;
    END
  END issue_o.operand_count[0]
  PIN issue_o.operand_count[1]
    DIRECTION OUTPUT ;
    USE SIGNAL ;
    PORT
      LAYER Metal2 ;
        RECT  305.56 0 305.96 0.4 ;
    END
  END issue_o.operand_count[1]
  PIN issue_o.operand_count[2]
    DIRECTION OUTPUT ;
    USE SIGNAL ;
    PORT
      LAYER Metal2 ;
        RECT  310.36 0 310.76 0.4 ;
    END
  END issue_o.operand_count[2]
  PIN issue_o.slot[0]
    DIRECTION OUTPUT ;
    USE SIGNAL ;
    PORT
      LAYER Metal2 ;
        RECT  301.72 0 302.12 0.4 ;
    END
  END issue_o.slot[0]
  PIN issue_o.slot[100]
    DIRECTION OUTPUT ;
    USE SIGNAL ;
    PORT
      LAYER Metal2 ;
        RECT  527.32 0 527.72 0.4 ;
    END
  END issue_o.slot[100]
  PIN issue_o.slot[101]
    DIRECTION OUTPUT ;
    USE SIGNAL ;
    PORT
      LAYER Metal2 ;
        RECT  529.24 0 529.64 0.4 ;
    END
  END issue_o.slot[101]
  PIN issue_o.slot[102]
    DIRECTION OUTPUT ;
    USE SIGNAL ;
    PORT
      LAYER Metal2 ;
        RECT  531.16 0 531.56 0.4 ;
    END
  END issue_o.slot[102]
  PIN issue_o.slot[103]
    DIRECTION OUTPUT ;
    USE SIGNAL ;
    PORT
      LAYER Metal2 ;
        RECT  533.08 0 533.48 0.4 ;
    END
  END issue_o.slot[103]
  PIN issue_o.slot[104]
    DIRECTION OUTPUT ;
    USE SIGNAL ;
    PORT
      LAYER Metal2 ;
        RECT  535 0 535.4 0.4 ;
    END
  END issue_o.slot[104]
  PIN issue_o.slot[105]
    DIRECTION OUTPUT ;
    USE SIGNAL ;
    PORT
      LAYER Metal2 ;
        RECT  536.92 0 537.32 0.4 ;
    END
  END issue_o.slot[105]
  PIN issue_o.slot[106]
    DIRECTION OUTPUT ;
    USE SIGNAL ;
    PORT
      LAYER Metal2 ;
        RECT  538.84 0 539.24 0.4 ;
    END
  END issue_o.slot[106]
  PIN issue_o.slot[107]
    DIRECTION OUTPUT ;
    USE SIGNAL ;
    PORT
      LAYER Metal2 ;
        RECT  540.76 0 541.16 0.4 ;
    END
  END issue_o.slot[107]
  PIN issue_o.slot[108]
    DIRECTION OUTPUT ;
    USE SIGNAL ;
    PORT
      LAYER Metal2 ;
        RECT  542.68 0 543.08 0.4 ;
    END
  END issue_o.slot[108]
  PIN issue_o.slot[109]
    DIRECTION OUTPUT ;
    USE SIGNAL ;
    PORT
      LAYER Metal2 ;
        RECT  544.6 0 545 0.4 ;
    END
  END issue_o.slot[109]
  PIN issue_o.slot[10]
    DIRECTION OUTPUT ;
    USE SIGNAL ;
    PORT
      LAYER Metal2 ;
        RECT  334.36 0 334.76 0.4 ;
    END
  END issue_o.slot[10]
  PIN issue_o.slot[110]
    DIRECTION OUTPUT ;
    USE SIGNAL ;
    PORT
      LAYER Metal2 ;
        RECT  546.52 0 546.92 0.4 ;
    END
  END issue_o.slot[110]
  PIN issue_o.slot[111]
    DIRECTION OUTPUT ;
    USE SIGNAL ;
    PORT
      LAYER Metal2 ;
        RECT  548.44 0 548.84 0.4 ;
    END
  END issue_o.slot[111]
  PIN issue_o.slot[112]
    DIRECTION OUTPUT ;
    USE SIGNAL ;
    PORT
      LAYER Metal2 ;
        RECT  550.36 0 550.76 0.4 ;
    END
  END issue_o.slot[112]
  PIN issue_o.slot[113]
    DIRECTION OUTPUT ;
    USE SIGNAL ;
    PORT
      LAYER Metal2 ;
        RECT  552.28 0 552.68 0.4 ;
    END
  END issue_o.slot[113]
  PIN issue_o.slot[114]
    DIRECTION OUTPUT ;
    USE SIGNAL ;
    PORT
      LAYER Metal2 ;
        RECT  554.2 0 554.6 0.4 ;
    END
  END issue_o.slot[114]
  PIN issue_o.slot[115]
    DIRECTION OUTPUT ;
    USE SIGNAL ;
    PORT
      LAYER Metal2 ;
        RECT  556.12 0 556.52 0.4 ;
    END
  END issue_o.slot[115]
  PIN issue_o.slot[116]
    DIRECTION OUTPUT ;
    USE SIGNAL ;
    PORT
      LAYER Metal2 ;
        RECT  558.04 0 558.44 0.4 ;
    END
  END issue_o.slot[116]
  PIN issue_o.slot[117]
    DIRECTION OUTPUT ;
    USE SIGNAL ;
    PORT
      LAYER Metal2 ;
        RECT  559.96 0 560.36 0.4 ;
    END
  END issue_o.slot[117]
  PIN issue_o.slot[118]
    DIRECTION OUTPUT ;
    USE SIGNAL ;
    PORT
      LAYER Metal2 ;
        RECT  561.88 0 562.28 0.4 ;
    END
  END issue_o.slot[118]
  PIN issue_o.slot[119]
    DIRECTION OUTPUT ;
    USE SIGNAL ;
    PORT
      LAYER Metal2 ;
        RECT  563.8 0 564.2 0.4 ;
    END
  END issue_o.slot[119]
  PIN issue_o.slot[11]
    DIRECTION OUTPUT ;
    USE SIGNAL ;
    PORT
      LAYER Metal2 ;
        RECT  337.24 0 337.64 0.4 ;
    END
  END issue_o.slot[11]
  PIN issue_o.slot[120]
    DIRECTION OUTPUT ;
    USE SIGNAL ;
    PORT
      LAYER Metal2 ;
        RECT  565.72 0 566.12 0.4 ;
    END
  END issue_o.slot[120]
  PIN issue_o.slot[121]
    DIRECTION OUTPUT ;
    USE SIGNAL ;
    PORT
      LAYER Metal2 ;
        RECT  567.64 0 568.04 0.4 ;
    END
  END issue_o.slot[121]
  PIN issue_o.slot[122]
    DIRECTION OUTPUT ;
    USE SIGNAL ;
    PORT
      LAYER Metal2 ;
        RECT  569.56 0 569.96 0.4 ;
    END
  END issue_o.slot[122]
  PIN issue_o.slot[123]
    DIRECTION OUTPUT ;
    USE SIGNAL ;
    PORT
      LAYER Metal2 ;
        RECT  571.48 0 571.88 0.4 ;
    END
  END issue_o.slot[123]
  PIN issue_o.slot[124]
    DIRECTION OUTPUT ;
    USE SIGNAL ;
    PORT
      LAYER Metal2 ;
        RECT  573.4 0 573.8 0.4 ;
    END
  END issue_o.slot[124]
  PIN issue_o.slot[125]
    DIRECTION OUTPUT ;
    USE SIGNAL ;
    PORT
      LAYER Metal2 ;
        RECT  575.32 0 575.72 0.4 ;
    END
  END issue_o.slot[125]
  PIN issue_o.slot[126]
    DIRECTION OUTPUT ;
    USE SIGNAL ;
    PORT
      LAYER Metal2 ;
        RECT  577.24 0 577.64 0.4 ;
    END
  END issue_o.slot[126]
  PIN issue_o.slot[127]
    DIRECTION OUTPUT ;
    USE SIGNAL ;
    PORT
      LAYER Metal2 ;
        RECT  579.16 0 579.56 0.4 ;
    END
  END issue_o.slot[127]
  PIN issue_o.slot[128]
    DIRECTION OUTPUT ;
    USE SIGNAL ;
    PORT
      LAYER Metal2 ;
        RECT  581.08 0 581.48 0.4 ;
    END
  END issue_o.slot[128]
  PIN issue_o.slot[129]
    DIRECTION OUTPUT ;
    USE SIGNAL ;
    PORT
      LAYER Metal2 ;
        RECT  583 0 583.4 0.4 ;
    END
  END issue_o.slot[129]
  PIN issue_o.slot[12]
    DIRECTION OUTPUT ;
    USE SIGNAL ;
    PORT
      LAYER Metal2 ;
        RECT  340.12 0 340.52 0.4 ;
    END
  END issue_o.slot[12]
  PIN issue_o.slot[130]
    DIRECTION OUTPUT ;
    USE SIGNAL ;
    PORT
      LAYER Metal2 ;
        RECT  584.92 0 585.32 0.4 ;
    END
  END issue_o.slot[130]
  PIN issue_o.slot[131]
    DIRECTION OUTPUT ;
    USE SIGNAL ;
    PORT
      LAYER Metal2 ;
        RECT  586.84 0 587.24 0.4 ;
    END
  END issue_o.slot[131]
  PIN issue_o.slot[132]
    DIRECTION OUTPUT ;
    USE SIGNAL ;
    PORT
      LAYER Metal2 ;
        RECT  588.76 0 589.16 0.4 ;
    END
  END issue_o.slot[132]
  PIN issue_o.slot[133]
    DIRECTION OUTPUT ;
    USE SIGNAL ;
    PORT
      LAYER Metal2 ;
        RECT  590.68 0 591.08 0.4 ;
    END
  END issue_o.slot[133]
  PIN issue_o.slot[134]
    DIRECTION OUTPUT ;
    USE SIGNAL ;
    PORT
      LAYER Metal2 ;
        RECT  592.6 0 593 0.4 ;
    END
  END issue_o.slot[134]
  PIN issue_o.slot[135]
    DIRECTION OUTPUT ;
    USE SIGNAL ;
    PORT
      LAYER Metal2 ;
        RECT  594.52 0 594.92 0.4 ;
    END
  END issue_o.slot[135]
  PIN issue_o.slot[136]
    DIRECTION OUTPUT ;
    USE SIGNAL ;
    PORT
      LAYER Metal2 ;
        RECT  596.44 0 596.84 0.4 ;
    END
  END issue_o.slot[136]
  PIN issue_o.slot[137]
    DIRECTION OUTPUT ;
    USE SIGNAL ;
    PORT
      LAYER Metal2 ;
        RECT  598.36 0 598.76 0.4 ;
    END
  END issue_o.slot[137]
  PIN issue_o.slot[138]
    DIRECTION OUTPUT ;
    USE SIGNAL ;
    PORT
      LAYER Metal2 ;
        RECT  600.28 0 600.68 0.4 ;
    END
  END issue_o.slot[138]
  PIN issue_o.slot[139]
    DIRECTION OUTPUT ;
    USE SIGNAL ;
    PORT
      LAYER Metal2 ;
        RECT  602.2 0 602.6 0.4 ;
    END
  END issue_o.slot[139]
  PIN issue_o.slot[13]
    DIRECTION OUTPUT ;
    USE SIGNAL ;
    PORT
      LAYER Metal2 ;
        RECT  343 0 343.4 0.4 ;
    END
  END issue_o.slot[13]
  PIN issue_o.slot[140]
    DIRECTION OUTPUT ;
    USE SIGNAL ;
    PORT
      LAYER Metal2 ;
        RECT  604.12 0 604.52 0.4 ;
    END
  END issue_o.slot[140]
  PIN issue_o.slot[141]
    DIRECTION OUTPUT ;
    USE SIGNAL ;
    PORT
      LAYER Metal2 ;
        RECT  606.04 0 606.44 0.4 ;
    END
  END issue_o.slot[141]
  PIN issue_o.slot[142]
    DIRECTION OUTPUT ;
    USE SIGNAL ;
    PORT
      LAYER Metal2 ;
        RECT  607.96 0 608.36 0.4 ;
    END
  END issue_o.slot[142]
  PIN issue_o.slot[14]
    DIRECTION OUTPUT ;
    USE SIGNAL ;
    PORT
      LAYER Metal2 ;
        RECT  345.88 0 346.28 0.4 ;
    END
  END issue_o.slot[14]
  PIN issue_o.slot[15]
    DIRECTION OUTPUT ;
    USE SIGNAL ;
    PORT
      LAYER Metal2 ;
        RECT  348.76 0 349.16 0.4 ;
    END
  END issue_o.slot[15]
  PIN issue_o.slot[16]
    DIRECTION OUTPUT ;
    USE SIGNAL ;
    PORT
      LAYER Metal2 ;
        RECT  351.64 0 352.04 0.4 ;
    END
  END issue_o.slot[16]
  PIN issue_o.slot[17]
    DIRECTION OUTPUT ;
    USE SIGNAL ;
    PORT
      LAYER Metal2 ;
        RECT  354.52 0 354.92 0.4 ;
    END
  END issue_o.slot[17]
  PIN issue_o.slot[18]
    DIRECTION OUTPUT ;
    USE SIGNAL ;
    PORT
      LAYER Metal2 ;
        RECT  357.4 0 357.8 0.4 ;
    END
  END issue_o.slot[18]
  PIN issue_o.slot[19]
    DIRECTION OUTPUT ;
    USE SIGNAL ;
    PORT
      LAYER Metal2 ;
        RECT  360.28 0 360.68 0.4 ;
    END
  END issue_o.slot[19]
  PIN issue_o.slot[1]
    DIRECTION OUTPUT ;
    USE SIGNAL ;
    PORT
      LAYER Metal2 ;
        RECT  306.52 0 306.92 0.4 ;
    END
  END issue_o.slot[1]
  PIN issue_o.slot[20]
    DIRECTION OUTPUT ;
    USE SIGNAL ;
    PORT
      LAYER Metal2 ;
        RECT  363.16 0 363.56 0.4 ;
    END
  END issue_o.slot[20]
  PIN issue_o.slot[21]
    DIRECTION OUTPUT ;
    USE SIGNAL ;
    PORT
      LAYER Metal2 ;
        RECT  366.04 0 366.44 0.4 ;
    END
  END issue_o.slot[21]
  PIN issue_o.slot[22]
    DIRECTION OUTPUT ;
    USE SIGNAL ;
    PORT
      LAYER Metal2 ;
        RECT  368.92 0 369.32 0.4 ;
    END
  END issue_o.slot[22]
  PIN issue_o.slot[23]
    DIRECTION OUTPUT ;
    USE SIGNAL ;
    PORT
      LAYER Metal2 ;
        RECT  371.8 0 372.2 0.4 ;
    END
  END issue_o.slot[23]
  PIN issue_o.slot[24]
    DIRECTION OUTPUT ;
    USE SIGNAL ;
    PORT
      LAYER Metal2 ;
        RECT  374.68 0 375.08 0.4 ;
    END
  END issue_o.slot[24]
  PIN issue_o.slot[25]
    DIRECTION OUTPUT ;
    USE SIGNAL ;
    PORT
      LAYER Metal2 ;
        RECT  377.56 0 377.96 0.4 ;
    END
  END issue_o.slot[25]
  PIN issue_o.slot[26]
    DIRECTION OUTPUT ;
    USE SIGNAL ;
    PORT
      LAYER Metal2 ;
        RECT  380.44 0 380.84 0.4 ;
    END
  END issue_o.slot[26]
  PIN issue_o.slot[27]
    DIRECTION OUTPUT ;
    USE SIGNAL ;
    PORT
      LAYER Metal2 ;
        RECT  383.32 0 383.72 0.4 ;
    END
  END issue_o.slot[27]
  PIN issue_o.slot[28]
    DIRECTION OUTPUT ;
    USE SIGNAL ;
    PORT
      LAYER Metal2 ;
        RECT  386.2 0 386.6 0.4 ;
    END
  END issue_o.slot[28]
  PIN issue_o.slot[29]
    DIRECTION OUTPUT ;
    USE SIGNAL ;
    PORT
      LAYER Metal2 ;
        RECT  389.08 0 389.48 0.4 ;
    END
  END issue_o.slot[29]
  PIN issue_o.slot[2]
    DIRECTION OUTPUT ;
    USE SIGNAL ;
    PORT
      LAYER Metal2 ;
        RECT  311.32 0 311.72 0.4 ;
    END
  END issue_o.slot[2]
  PIN issue_o.slot[30]
    DIRECTION OUTPUT ;
    USE SIGNAL ;
    PORT
      LAYER Metal2 ;
        RECT  391.96 0 392.36 0.4 ;
    END
  END issue_o.slot[30]
  PIN issue_o.slot[31]
    DIRECTION OUTPUT ;
    USE SIGNAL ;
    PORT
      LAYER Metal2 ;
        RECT  394.84 0 395.24 0.4 ;
    END
  END issue_o.slot[31]
  PIN issue_o.slot[32]
    DIRECTION OUTPUT ;
    USE SIGNAL ;
    PORT
      LAYER Metal2 ;
        RECT  396.76 0 397.16 0.4 ;
    END
  END issue_o.slot[32]
  PIN issue_o.slot[33]
    DIRECTION OUTPUT ;
    USE SIGNAL ;
    PORT
      LAYER Metal2 ;
        RECT  398.68 0 399.08 0.4 ;
    END
  END issue_o.slot[33]
  PIN issue_o.slot[34]
    DIRECTION OUTPUT ;
    USE SIGNAL ;
    PORT
      LAYER Metal2 ;
        RECT  400.6 0 401 0.4 ;
    END
  END issue_o.slot[34]
  PIN issue_o.slot[35]
    DIRECTION OUTPUT ;
    USE SIGNAL ;
    PORT
      LAYER Metal2 ;
        RECT  402.52 0 402.92 0.4 ;
    END
  END issue_o.slot[35]
  PIN issue_o.slot[36]
    DIRECTION OUTPUT ;
    USE SIGNAL ;
    PORT
      LAYER Metal2 ;
        RECT  404.44 0 404.84 0.4 ;
    END
  END issue_o.slot[36]
  PIN issue_o.slot[37]
    DIRECTION OUTPUT ;
    USE SIGNAL ;
    PORT
      LAYER Metal2 ;
        RECT  406.36 0 406.76 0.4 ;
    END
  END issue_o.slot[37]
  PIN issue_o.slot[38]
    DIRECTION OUTPUT ;
    USE SIGNAL ;
    PORT
      LAYER Metal2 ;
        RECT  408.28 0 408.68 0.4 ;
    END
  END issue_o.slot[38]
  PIN issue_o.slot[39]
    DIRECTION OUTPUT ;
    USE SIGNAL ;
    PORT
      LAYER Metal2 ;
        RECT  410.2 0 410.6 0.4 ;
    END
  END issue_o.slot[39]
  PIN issue_o.slot[3]
    DIRECTION OUTPUT ;
    USE SIGNAL ;
    PORT
      LAYER Metal2 ;
        RECT  314.2 0 314.6 0.4 ;
    END
  END issue_o.slot[3]
  PIN issue_o.slot[40]
    DIRECTION OUTPUT ;
    USE SIGNAL ;
    PORT
      LAYER Metal2 ;
        RECT  412.12 0 412.52 0.4 ;
    END
  END issue_o.slot[40]
  PIN issue_o.slot[41]
    DIRECTION OUTPUT ;
    USE SIGNAL ;
    PORT
      LAYER Metal2 ;
        RECT  414.04 0 414.44 0.4 ;
    END
  END issue_o.slot[41]
  PIN issue_o.slot[42]
    DIRECTION OUTPUT ;
    USE SIGNAL ;
    PORT
      LAYER Metal2 ;
        RECT  415.96 0 416.36 0.4 ;
    END
  END issue_o.slot[42]
  PIN issue_o.slot[43]
    DIRECTION OUTPUT ;
    USE SIGNAL ;
    PORT
      LAYER Metal2 ;
        RECT  417.88 0 418.28 0.4 ;
    END
  END issue_o.slot[43]
  PIN issue_o.slot[44]
    DIRECTION OUTPUT ;
    USE SIGNAL ;
    PORT
      LAYER Metal2 ;
        RECT  419.8 0 420.2 0.4 ;
    END
  END issue_o.slot[44]
  PIN issue_o.slot[45]
    DIRECTION OUTPUT ;
    USE SIGNAL ;
    PORT
      LAYER Metal2 ;
        RECT  421.72 0 422.12 0.4 ;
    END
  END issue_o.slot[45]
  PIN issue_o.slot[46]
    DIRECTION OUTPUT ;
    USE SIGNAL ;
    PORT
      LAYER Metal2 ;
        RECT  423.64 0 424.04 0.4 ;
    END
  END issue_o.slot[46]
  PIN issue_o.slot[47]
    DIRECTION OUTPUT ;
    USE SIGNAL ;
    PORT
      LAYER Metal2 ;
        RECT  425.56 0 425.96 0.4 ;
    END
  END issue_o.slot[47]
  PIN issue_o.slot[48]
    DIRECTION OUTPUT ;
    USE SIGNAL ;
    PORT
      LAYER Metal2 ;
        RECT  427.48 0 427.88 0.4 ;
    END
  END issue_o.slot[48]
  PIN issue_o.slot[49]
    DIRECTION OUTPUT ;
    USE SIGNAL ;
    PORT
      LAYER Metal2 ;
        RECT  429.4 0 429.8 0.4 ;
    END
  END issue_o.slot[49]
  PIN issue_o.slot[4]
    DIRECTION OUTPUT ;
    USE SIGNAL ;
    PORT
      LAYER Metal2 ;
        RECT  317.08 0 317.48 0.4 ;
    END
  END issue_o.slot[4]
  PIN issue_o.slot[50]
    DIRECTION OUTPUT ;
    USE SIGNAL ;
    PORT
      LAYER Metal2 ;
        RECT  431.32 0 431.72 0.4 ;
    END
  END issue_o.slot[50]
  PIN issue_o.slot[51]
    DIRECTION OUTPUT ;
    USE SIGNAL ;
    PORT
      LAYER Metal2 ;
        RECT  433.24 0 433.64 0.4 ;
    END
  END issue_o.slot[51]
  PIN issue_o.slot[52]
    DIRECTION OUTPUT ;
    USE SIGNAL ;
    PORT
      LAYER Metal2 ;
        RECT  435.16 0 435.56 0.4 ;
    END
  END issue_o.slot[52]
  PIN issue_o.slot[53]
    DIRECTION OUTPUT ;
    USE SIGNAL ;
    PORT
      LAYER Metal2 ;
        RECT  437.08 0 437.48 0.4 ;
    END
  END issue_o.slot[53]
  PIN issue_o.slot[54]
    DIRECTION OUTPUT ;
    USE SIGNAL ;
    PORT
      LAYER Metal2 ;
        RECT  439 0 439.4 0.4 ;
    END
  END issue_o.slot[54]
  PIN issue_o.slot[55]
    DIRECTION OUTPUT ;
    USE SIGNAL ;
    PORT
      LAYER Metal2 ;
        RECT  440.92 0 441.32 0.4 ;
    END
  END issue_o.slot[55]
  PIN issue_o.slot[56]
    DIRECTION OUTPUT ;
    USE SIGNAL ;
    PORT
      LAYER Metal2 ;
        RECT  442.84 0 443.24 0.4 ;
    END
  END issue_o.slot[56]
  PIN issue_o.slot[57]
    DIRECTION OUTPUT ;
    USE SIGNAL ;
    PORT
      LAYER Metal2 ;
        RECT  444.76 0 445.16 0.4 ;
    END
  END issue_o.slot[57]
  PIN issue_o.slot[58]
    DIRECTION OUTPUT ;
    USE SIGNAL ;
    PORT
      LAYER Metal2 ;
        RECT  446.68 0 447.08 0.4 ;
    END
  END issue_o.slot[58]
  PIN issue_o.slot[59]
    DIRECTION OUTPUT ;
    USE SIGNAL ;
    PORT
      LAYER Metal2 ;
        RECT  448.6 0 449 0.4 ;
    END
  END issue_o.slot[59]
  PIN issue_o.slot[5]
    DIRECTION OUTPUT ;
    USE SIGNAL ;
    PORT
      LAYER Metal2 ;
        RECT  319.96 0 320.36 0.4 ;
    END
  END issue_o.slot[5]
  PIN issue_o.slot[60]
    DIRECTION OUTPUT ;
    USE SIGNAL ;
    PORT
      LAYER Metal2 ;
        RECT  450.52 0 450.92 0.4 ;
    END
  END issue_o.slot[60]
  PIN issue_o.slot[61]
    DIRECTION OUTPUT ;
    USE SIGNAL ;
    PORT
      LAYER Metal2 ;
        RECT  452.44 0 452.84 0.4 ;
    END
  END issue_o.slot[61]
  PIN issue_o.slot[62]
    DIRECTION OUTPUT ;
    USE SIGNAL ;
    PORT
      LAYER Metal2 ;
        RECT  454.36 0 454.76 0.4 ;
    END
  END issue_o.slot[62]
  PIN issue_o.slot[63]
    DIRECTION OUTPUT ;
    USE SIGNAL ;
    PORT
      LAYER Metal2 ;
        RECT  456.28 0 456.68 0.4 ;
    END
  END issue_o.slot[63]
  PIN issue_o.slot[64]
    DIRECTION OUTPUT ;
    USE SIGNAL ;
    PORT
      LAYER Metal2 ;
        RECT  458.2 0 458.6 0.4 ;
    END
  END issue_o.slot[64]
  PIN issue_o.slot[65]
    DIRECTION OUTPUT ;
    USE SIGNAL ;
    PORT
      LAYER Metal2 ;
        RECT  460.12 0 460.52 0.4 ;
    END
  END issue_o.slot[65]
  PIN issue_o.slot[66]
    DIRECTION OUTPUT ;
    USE SIGNAL ;
    PORT
      LAYER Metal2 ;
        RECT  462.04 0 462.44 0.4 ;
    END
  END issue_o.slot[66]
  PIN issue_o.slot[67]
    DIRECTION OUTPUT ;
    USE SIGNAL ;
    PORT
      LAYER Metal2 ;
        RECT  463.96 0 464.36 0.4 ;
    END
  END issue_o.slot[67]
  PIN issue_o.slot[68]
    DIRECTION OUTPUT ;
    USE SIGNAL ;
    PORT
      LAYER Metal2 ;
        RECT  465.88 0 466.28 0.4 ;
    END
  END issue_o.slot[68]
  PIN issue_o.slot[69]
    DIRECTION OUTPUT ;
    USE SIGNAL ;
    PORT
      LAYER Metal2 ;
        RECT  467.8 0 468.2 0.4 ;
    END
  END issue_o.slot[69]
  PIN issue_o.slot[6]
    DIRECTION OUTPUT ;
    USE SIGNAL ;
    PORT
      LAYER Metal2 ;
        RECT  322.84 0 323.24 0.4 ;
    END
  END issue_o.slot[6]
  PIN issue_o.slot[70]
    DIRECTION OUTPUT ;
    USE SIGNAL ;
    PORT
      LAYER Metal2 ;
        RECT  469.72 0 470.12 0.4 ;
    END
  END issue_o.slot[70]
  PIN issue_o.slot[71]
    DIRECTION OUTPUT ;
    USE SIGNAL ;
    PORT
      LAYER Metal2 ;
        RECT  471.64 0 472.04 0.4 ;
    END
  END issue_o.slot[71]
  PIN issue_o.slot[72]
    DIRECTION OUTPUT ;
    USE SIGNAL ;
    PORT
      LAYER Metal2 ;
        RECT  473.56 0 473.96 0.4 ;
    END
  END issue_o.slot[72]
  PIN issue_o.slot[73]
    DIRECTION OUTPUT ;
    USE SIGNAL ;
    PORT
      LAYER Metal2 ;
        RECT  475.48 0 475.88 0.4 ;
    END
  END issue_o.slot[73]
  PIN issue_o.slot[74]
    DIRECTION OUTPUT ;
    USE SIGNAL ;
    PORT
      LAYER Metal2 ;
        RECT  477.4 0 477.8 0.4 ;
    END
  END issue_o.slot[74]
  PIN issue_o.slot[75]
    DIRECTION OUTPUT ;
    USE SIGNAL ;
    PORT
      LAYER Metal2 ;
        RECT  479.32 0 479.72 0.4 ;
    END
  END issue_o.slot[75]
  PIN issue_o.slot[76]
    DIRECTION OUTPUT ;
    USE SIGNAL ;
    PORT
      LAYER Metal2 ;
        RECT  481.24 0 481.64 0.4 ;
    END
  END issue_o.slot[76]
  PIN issue_o.slot[77]
    DIRECTION OUTPUT ;
    USE SIGNAL ;
    PORT
      LAYER Metal2 ;
        RECT  483.16 0 483.56 0.4 ;
    END
  END issue_o.slot[77]
  PIN issue_o.slot[78]
    DIRECTION OUTPUT ;
    USE SIGNAL ;
    PORT
      LAYER Metal2 ;
        RECT  485.08 0 485.48 0.4 ;
    END
  END issue_o.slot[78]
  PIN issue_o.slot[79]
    DIRECTION OUTPUT ;
    USE SIGNAL ;
    PORT
      LAYER Metal2 ;
        RECT  487 0 487.4 0.4 ;
    END
  END issue_o.slot[79]
  PIN issue_o.slot[7]
    DIRECTION OUTPUT ;
    USE SIGNAL ;
    PORT
      LAYER Metal2 ;
        RECT  325.72 0 326.12 0.4 ;
    END
  END issue_o.slot[7]
  PIN issue_o.slot[80]
    DIRECTION OUTPUT ;
    USE SIGNAL ;
    PORT
      LAYER Metal2 ;
        RECT  488.92 0 489.32 0.4 ;
    END
  END issue_o.slot[80]
  PIN issue_o.slot[81]
    DIRECTION OUTPUT ;
    USE SIGNAL ;
    PORT
      LAYER Metal2 ;
        RECT  490.84 0 491.24 0.4 ;
    END
  END issue_o.slot[81]
  PIN issue_o.slot[82]
    DIRECTION OUTPUT ;
    USE SIGNAL ;
    PORT
      LAYER Metal2 ;
        RECT  492.76 0 493.16 0.4 ;
    END
  END issue_o.slot[82]
  PIN issue_o.slot[83]
    DIRECTION OUTPUT ;
    USE SIGNAL ;
    PORT
      LAYER Metal2 ;
        RECT  494.68 0 495.08 0.4 ;
    END
  END issue_o.slot[83]
  PIN issue_o.slot[84]
    DIRECTION OUTPUT ;
    USE SIGNAL ;
    PORT
      LAYER Metal2 ;
        RECT  496.6 0 497 0.4 ;
    END
  END issue_o.slot[84]
  PIN issue_o.slot[85]
    DIRECTION OUTPUT ;
    USE SIGNAL ;
    PORT
      LAYER Metal2 ;
        RECT  498.52 0 498.92 0.4 ;
    END
  END issue_o.slot[85]
  PIN issue_o.slot[86]
    DIRECTION OUTPUT ;
    USE SIGNAL ;
    PORT
      LAYER Metal2 ;
        RECT  500.44 0 500.84 0.4 ;
    END
  END issue_o.slot[86]
  PIN issue_o.slot[87]
    DIRECTION OUTPUT ;
    USE SIGNAL ;
    PORT
      LAYER Metal2 ;
        RECT  502.36 0 502.76 0.4 ;
    END
  END issue_o.slot[87]
  PIN issue_o.slot[88]
    DIRECTION OUTPUT ;
    USE SIGNAL ;
    PORT
      LAYER Metal2 ;
        RECT  504.28 0 504.68 0.4 ;
    END
  END issue_o.slot[88]
  PIN issue_o.slot[89]
    DIRECTION OUTPUT ;
    USE SIGNAL ;
    PORT
      LAYER Metal2 ;
        RECT  506.2 0 506.6 0.4 ;
    END
  END issue_o.slot[89]
  PIN issue_o.slot[8]
    DIRECTION OUTPUT ;
    USE SIGNAL ;
    PORT
      LAYER Metal2 ;
        RECT  328.6 0 329 0.4 ;
    END
  END issue_o.slot[8]
  PIN issue_o.slot[90]
    DIRECTION OUTPUT ;
    USE SIGNAL ;
    PORT
      LAYER Metal2 ;
        RECT  508.12 0 508.52 0.4 ;
    END
  END issue_o.slot[90]
  PIN issue_o.slot[91]
    DIRECTION OUTPUT ;
    USE SIGNAL ;
    PORT
      LAYER Metal2 ;
        RECT  510.04 0 510.44 0.4 ;
    END
  END issue_o.slot[91]
  PIN issue_o.slot[92]
    DIRECTION OUTPUT ;
    USE SIGNAL ;
    PORT
      LAYER Metal2 ;
        RECT  511.96 0 512.36 0.4 ;
    END
  END issue_o.slot[92]
  PIN issue_o.slot[93]
    DIRECTION OUTPUT ;
    USE SIGNAL ;
    PORT
      LAYER Metal2 ;
        RECT  513.88 0 514.28 0.4 ;
    END
  END issue_o.slot[93]
  PIN issue_o.slot[94]
    DIRECTION OUTPUT ;
    USE SIGNAL ;
    PORT
      LAYER Metal2 ;
        RECT  515.8 0 516.2 0.4 ;
    END
  END issue_o.slot[94]
  PIN issue_o.slot[95]
    DIRECTION OUTPUT ;
    USE SIGNAL ;
    PORT
      LAYER Metal2 ;
        RECT  517.72 0 518.12 0.4 ;
    END
  END issue_o.slot[95]
  PIN issue_o.slot[96]
    DIRECTION OUTPUT ;
    USE SIGNAL ;
    PORT
      LAYER Metal2 ;
        RECT  519.64 0 520.04 0.4 ;
    END
  END issue_o.slot[96]
  PIN issue_o.slot[97]
    DIRECTION OUTPUT ;
    USE SIGNAL ;
    PORT
      LAYER Metal2 ;
        RECT  521.56 0 521.96 0.4 ;
    END
  END issue_o.slot[97]
  PIN issue_o.slot[98]
    DIRECTION OUTPUT ;
    USE SIGNAL ;
    PORT
      LAYER Metal2 ;
        RECT  523.48 0 523.88 0.4 ;
    END
  END issue_o.slot[98]
  PIN issue_o.slot[99]
    DIRECTION OUTPUT ;
    USE SIGNAL ;
    PORT
      LAYER Metal2 ;
        RECT  525.4 0 525.8 0.4 ;
    END
  END issue_o.slot[99]
  PIN issue_o.slot[9]
    DIRECTION OUTPUT ;
    USE SIGNAL ;
    PORT
      LAYER Metal2 ;
        RECT  331.48 0 331.88 0.4 ;
    END
  END issue_o.slot[9]
  PIN issue_ready_i
    DIRECTION INPUT ;
    USE SIGNAL ;
    PORT
      LAYER Metal2 ;
        RECT  295 0 295.4 0.4 ;
    END
  END issue_ready_i
  PIN issue_valid_o
    DIRECTION OUTPUT ;
    USE SIGNAL ;
    PORT
      LAYER Metal2 ;
        RECT  294.04 0 294.44 0.4 ;
    END
  END issue_valid_o
  PIN lim_dsp_i[0]
    DIRECTION INPUT ;
    USE SIGNAL ;
    PORT
      LAYER Metal3 ;
        RECT  1499.6 76.66 1500 77.06 ;
    END
  END lim_dsp_i[0]
  PIN lim_dsp_i[10]
    DIRECTION INPUT ;
    USE SIGNAL ;
    PORT
      LAYER Metal3 ;
        RECT  1499.6 135.46 1500 135.86 ;
    END
  END lim_dsp_i[10]
  PIN lim_dsp_i[11]
    DIRECTION INPUT ;
    USE SIGNAL ;
    PORT
      LAYER Metal3 ;
        RECT  1499.6 141.34 1500 141.74 ;
    END
  END lim_dsp_i[11]
  PIN lim_dsp_i[12]
    DIRECTION INPUT ;
    USE SIGNAL ;
    PORT
      LAYER Metal3 ;
        RECT  1499.6 147.22 1500 147.62 ;
    END
  END lim_dsp_i[12]
  PIN lim_dsp_i[13]
    DIRECTION INPUT ;
    USE SIGNAL ;
    PORT
      LAYER Metal3 ;
        RECT  1499.6 153.1 1500 153.5 ;
    END
  END lim_dsp_i[13]
  PIN lim_dsp_i[14]
    DIRECTION INPUT ;
    USE SIGNAL ;
    PORT
      LAYER Metal3 ;
        RECT  1499.6 158.98 1500 159.38 ;
    END
  END lim_dsp_i[14]
  PIN lim_dsp_i[15]
    DIRECTION INPUT ;
    USE SIGNAL ;
    PORT
      LAYER Metal3 ;
        RECT  1499.6 164.86 1500 165.26 ;
    END
  END lim_dsp_i[15]
  PIN lim_dsp_i[16]
    DIRECTION INPUT ;
    USE SIGNAL ;
    PORT
      LAYER Metal3 ;
        RECT  1499.6 170.74 1500 171.14 ;
    END
  END lim_dsp_i[16]
  PIN lim_dsp_i[17]
    DIRECTION INPUT ;
    USE SIGNAL ;
    PORT
      LAYER Metal3 ;
        RECT  1499.6 176.62 1500 177.02 ;
    END
  END lim_dsp_i[17]
  PIN lim_dsp_i[18]
    DIRECTION INPUT ;
    USE SIGNAL ;
    PORT
      LAYER Metal3 ;
        RECT  1499.6 182.5 1500 182.9 ;
    END
  END lim_dsp_i[18]
  PIN lim_dsp_i[19]
    DIRECTION INPUT ;
    USE SIGNAL ;
    PORT
      LAYER Metal3 ;
        RECT  1499.6 188.38 1500 188.78 ;
    END
  END lim_dsp_i[19]
  PIN lim_dsp_i[1]
    DIRECTION INPUT ;
    USE SIGNAL ;
    PORT
      LAYER Metal3 ;
        RECT  1499.6 82.54 1500 82.94 ;
    END
  END lim_dsp_i[1]
  PIN lim_dsp_i[20]
    DIRECTION INPUT ;
    USE SIGNAL ;
    PORT
      LAYER Metal3 ;
        RECT  1499.6 194.26 1500 194.66 ;
    END
  END lim_dsp_i[20]
  PIN lim_dsp_i[21]
    DIRECTION INPUT ;
    USE SIGNAL ;
    PORT
      LAYER Metal3 ;
        RECT  1499.6 200.14 1500 200.54 ;
    END
  END lim_dsp_i[21]
  PIN lim_dsp_i[22]
    DIRECTION INPUT ;
    USE SIGNAL ;
    PORT
      LAYER Metal3 ;
        RECT  1499.6 206.02 1500 206.42 ;
    END
  END lim_dsp_i[22]
  PIN lim_dsp_i[23]
    DIRECTION INPUT ;
    USE SIGNAL ;
    PORT
      LAYER Metal3 ;
        RECT  1499.6 211.9 1500 212.3 ;
    END
  END lim_dsp_i[23]
  PIN lim_dsp_i[24]
    DIRECTION INPUT ;
    USE SIGNAL ;
    PORT
      LAYER Metal3 ;
        RECT  1499.6 217.78 1500 218.18 ;
    END
  END lim_dsp_i[24]
  PIN lim_dsp_i[25]
    DIRECTION INPUT ;
    USE SIGNAL ;
    PORT
      LAYER Metal3 ;
        RECT  1499.6 223.66 1500 224.06 ;
    END
  END lim_dsp_i[25]
  PIN lim_dsp_i[26]
    DIRECTION INPUT ;
    USE SIGNAL ;
    PORT
      LAYER Metal3 ;
        RECT  1499.6 229.54 1500 229.94 ;
    END
  END lim_dsp_i[26]
  PIN lim_dsp_i[27]
    DIRECTION INPUT ;
    USE SIGNAL ;
    PORT
      LAYER Metal3 ;
        RECT  1499.6 235.42 1500 235.82 ;
    END
  END lim_dsp_i[27]
  PIN lim_dsp_i[28]
    DIRECTION INPUT ;
    USE SIGNAL ;
    PORT
      LAYER Metal3 ;
        RECT  1499.6 241.3 1500 241.7 ;
    END
  END lim_dsp_i[28]
  PIN lim_dsp_i[29]
    DIRECTION INPUT ;
    USE SIGNAL ;
    PORT
      LAYER Metal3 ;
        RECT  1499.6 247.18 1500 247.58 ;
    END
  END lim_dsp_i[29]
  PIN lim_dsp_i[2]
    DIRECTION INPUT ;
    USE SIGNAL ;
    PORT
      LAYER Metal3 ;
        RECT  1499.6 88.42 1500 88.82 ;
    END
  END lim_dsp_i[2]
  PIN lim_dsp_i[30]
    DIRECTION INPUT ;
    USE SIGNAL ;
    PORT
      LAYER Metal3 ;
        RECT  1499.6 253.06 1500 253.46 ;
    END
  END lim_dsp_i[30]
  PIN lim_dsp_i[31]
    DIRECTION INPUT ;
    USE SIGNAL ;
    PORT
      LAYER Metal3 ;
        RECT  1499.6 258.94 1500 259.34 ;
    END
  END lim_dsp_i[31]
  PIN lim_dsp_i[32]
    DIRECTION INPUT ;
    USE SIGNAL ;
    PORT
      LAYER Metal3 ;
        RECT  1499.6 264.82 1500 265.22 ;
    END
  END lim_dsp_i[32]
  PIN lim_dsp_i[33]
    DIRECTION INPUT ;
    USE SIGNAL ;
    PORT
      LAYER Metal3 ;
        RECT  1499.6 270.7 1500 271.1 ;
    END
  END lim_dsp_i[33]
  PIN lim_dsp_i[34]
    DIRECTION INPUT ;
    USE SIGNAL ;
    PORT
      LAYER Metal3 ;
        RECT  1499.6 276.58 1500 276.98 ;
    END
  END lim_dsp_i[34]
  PIN lim_dsp_i[35]
    DIRECTION INPUT ;
    USE SIGNAL ;
    PORT
      LAYER Metal3 ;
        RECT  1499.6 282.46 1500 282.86 ;
    END
  END lim_dsp_i[35]
  PIN lim_dsp_i[36]
    DIRECTION INPUT ;
    USE SIGNAL ;
    PORT
      LAYER Metal3 ;
        RECT  1499.6 288.34 1500 288.74 ;
    END
  END lim_dsp_i[36]
  PIN lim_dsp_i[37]
    DIRECTION INPUT ;
    USE SIGNAL ;
    PORT
      LAYER Metal3 ;
        RECT  1499.6 294.22 1500 294.62 ;
    END
  END lim_dsp_i[37]
  PIN lim_dsp_i[38]
    DIRECTION INPUT ;
    USE SIGNAL ;
    PORT
      LAYER Metal3 ;
        RECT  1499.6 300.1 1500 300.5 ;
    END
  END lim_dsp_i[38]
  PIN lim_dsp_i[39]
    DIRECTION INPUT ;
    USE SIGNAL ;
    PORT
      LAYER Metal3 ;
        RECT  1499.6 305.98 1500 306.38 ;
    END
  END lim_dsp_i[39]
  PIN lim_dsp_i[3]
    DIRECTION INPUT ;
    USE SIGNAL ;
    PORT
      LAYER Metal3 ;
        RECT  1499.6 94.3 1500 94.7 ;
    END
  END lim_dsp_i[3]
  PIN lim_dsp_i[40]
    DIRECTION INPUT ;
    USE SIGNAL ;
    PORT
      LAYER Metal3 ;
        RECT  1499.6 311.86 1500 312.26 ;
    END
  END lim_dsp_i[40]
  PIN lim_dsp_i[41]
    DIRECTION INPUT ;
    USE SIGNAL ;
    PORT
      LAYER Metal3 ;
        RECT  1499.6 317.74 1500 318.14 ;
    END
  END lim_dsp_i[41]
  PIN lim_dsp_i[42]
    DIRECTION INPUT ;
    USE SIGNAL ;
    PORT
      LAYER Metal3 ;
        RECT  1499.6 323.62 1500 324.02 ;
    END
  END lim_dsp_i[42]
  PIN lim_dsp_i[43]
    DIRECTION INPUT ;
    USE SIGNAL ;
    PORT
      LAYER Metal3 ;
        RECT  1499.6 329.5 1500 329.9 ;
    END
  END lim_dsp_i[43]
  PIN lim_dsp_i[44]
    DIRECTION INPUT ;
    USE SIGNAL ;
    PORT
      LAYER Metal3 ;
        RECT  1499.6 335.38 1500 335.78 ;
    END
  END lim_dsp_i[44]
  PIN lim_dsp_i[45]
    DIRECTION INPUT ;
    USE SIGNAL ;
    PORT
      LAYER Metal3 ;
        RECT  1499.6 341.26 1500 341.66 ;
    END
  END lim_dsp_i[45]
  PIN lim_dsp_i[46]
    DIRECTION INPUT ;
    USE SIGNAL ;
    PORT
      LAYER Metal3 ;
        RECT  1499.6 347.14 1500 347.54 ;
    END
  END lim_dsp_i[46]
  PIN lim_dsp_i[47]
    DIRECTION INPUT ;
    USE SIGNAL ;
    PORT
      LAYER Metal3 ;
        RECT  1499.6 353.02 1500 353.42 ;
    END
  END lim_dsp_i[47]
  PIN lim_dsp_i[48]
    DIRECTION INPUT ;
    USE SIGNAL ;
    PORT
      LAYER Metal3 ;
        RECT  1499.6 358.9 1500 359.3 ;
    END
  END lim_dsp_i[48]
  PIN lim_dsp_i[49]
    DIRECTION INPUT ;
    USE SIGNAL ;
    PORT
      LAYER Metal3 ;
        RECT  1499.6 364.78 1500 365.18 ;
    END
  END lim_dsp_i[49]
  PIN lim_dsp_i[4]
    DIRECTION INPUT ;
    USE SIGNAL ;
    PORT
      LAYER Metal3 ;
        RECT  1499.6 100.18 1500 100.58 ;
    END
  END lim_dsp_i[4]
  PIN lim_dsp_i[50]
    DIRECTION INPUT ;
    USE SIGNAL ;
    PORT
      LAYER Metal3 ;
        RECT  1499.6 370.66 1500 371.06 ;
    END
  END lim_dsp_i[50]
  PIN lim_dsp_i[51]
    DIRECTION INPUT ;
    USE SIGNAL ;
    PORT
      LAYER Metal3 ;
        RECT  1499.6 376.54 1500 376.94 ;
    END
  END lim_dsp_i[51]
  PIN lim_dsp_i[52]
    DIRECTION INPUT ;
    USE SIGNAL ;
    PORT
      LAYER Metal3 ;
        RECT  1499.6 382.42 1500 382.82 ;
    END
  END lim_dsp_i[52]
  PIN lim_dsp_i[53]
    DIRECTION INPUT ;
    USE SIGNAL ;
    PORT
      LAYER Metal3 ;
        RECT  1499.6 388.3 1500 388.7 ;
    END
  END lim_dsp_i[53]
  PIN lim_dsp_i[54]
    DIRECTION INPUT ;
    USE SIGNAL ;
    PORT
      LAYER Metal3 ;
        RECT  1499.6 394.18 1500 394.58 ;
    END
  END lim_dsp_i[54]
  PIN lim_dsp_i[55]
    DIRECTION INPUT ;
    USE SIGNAL ;
    PORT
      LAYER Metal3 ;
        RECT  1499.6 400.06 1500 400.46 ;
    END
  END lim_dsp_i[55]
  PIN lim_dsp_i[56]
    DIRECTION INPUT ;
    USE SIGNAL ;
    PORT
      LAYER Metal3 ;
        RECT  1499.6 405.94 1500 406.34 ;
    END
  END lim_dsp_i[56]
  PIN lim_dsp_i[57]
    DIRECTION INPUT ;
    USE SIGNAL ;
    PORT
      LAYER Metal3 ;
        RECT  1499.6 411.82 1500 412.22 ;
    END
  END lim_dsp_i[57]
  PIN lim_dsp_i[58]
    DIRECTION INPUT ;
    USE SIGNAL ;
    PORT
      LAYER Metal3 ;
        RECT  1499.6 417.7 1500 418.1 ;
    END
  END lim_dsp_i[58]
  PIN lim_dsp_i[59]
    DIRECTION INPUT ;
    USE SIGNAL ;
    PORT
      LAYER Metal3 ;
        RECT  1499.6 423.58 1500 423.98 ;
    END
  END lim_dsp_i[59]
  PIN lim_dsp_i[5]
    DIRECTION INPUT ;
    USE SIGNAL ;
    PORT
      LAYER Metal3 ;
        RECT  1499.6 106.06 1500 106.46 ;
    END
  END lim_dsp_i[5]
  PIN lim_dsp_i[60]
    DIRECTION INPUT ;
    USE SIGNAL ;
    PORT
      LAYER Metal3 ;
        RECT  1499.6 429.46 1500 429.86 ;
    END
  END lim_dsp_i[60]
  PIN lim_dsp_i[61]
    DIRECTION INPUT ;
    USE SIGNAL ;
    PORT
      LAYER Metal3 ;
        RECT  1499.6 435.34 1500 435.74 ;
    END
  END lim_dsp_i[61]
  PIN lim_dsp_i[62]
    DIRECTION INPUT ;
    USE SIGNAL ;
    PORT
      LAYER Metal3 ;
        RECT  1499.6 441.22 1500 441.62 ;
    END
  END lim_dsp_i[62]
  PIN lim_dsp_i[63]
    DIRECTION INPUT ;
    USE SIGNAL ;
    PORT
      LAYER Metal3 ;
        RECT  1499.6 447.1 1500 447.5 ;
    END
  END lim_dsp_i[63]
  PIN lim_dsp_i[6]
    DIRECTION INPUT ;
    USE SIGNAL ;
    PORT
      LAYER Metal3 ;
        RECT  1499.6 111.94 1500 112.34 ;
    END
  END lim_dsp_i[6]
  PIN lim_dsp_i[7]
    DIRECTION INPUT ;
    USE SIGNAL ;
    PORT
      LAYER Metal3 ;
        RECT  1499.6 117.82 1500 118.22 ;
    END
  END lim_dsp_i[7]
  PIN lim_dsp_i[8]
    DIRECTION INPUT ;
    USE SIGNAL ;
    PORT
      LAYER Metal3 ;
        RECT  1499.6 123.7 1500 124.1 ;
    END
  END lim_dsp_i[8]
  PIN lim_dsp_i[9]
    DIRECTION INPUT ;
    USE SIGNAL ;
    PORT
      LAYER Metal3 ;
        RECT  1499.6 129.58 1500 129.98 ;
    END
  END lim_dsp_i[9]
  PIN lim_rsp_i[0]
    DIRECTION INPUT ;
    USE SIGNAL ;
    PORT
      LAYER Metal3 ;
        RECT  1499.6 452.98 1500 453.38 ;
    END
  END lim_rsp_i[0]
  PIN lim_rsp_i[10]
    DIRECTION INPUT ;
    USE SIGNAL ;
    PORT
      LAYER Metal3 ;
        RECT  1499.6 511.78 1500 512.18 ;
    END
  END lim_rsp_i[10]
  PIN lim_rsp_i[11]
    DIRECTION INPUT ;
    USE SIGNAL ;
    PORT
      LAYER Metal3 ;
        RECT  1499.6 517.66 1500 518.06 ;
    END
  END lim_rsp_i[11]
  PIN lim_rsp_i[12]
    DIRECTION INPUT ;
    USE SIGNAL ;
    PORT
      LAYER Metal3 ;
        RECT  1499.6 523.54 1500 523.94 ;
    END
  END lim_rsp_i[12]
  PIN lim_rsp_i[13]
    DIRECTION INPUT ;
    USE SIGNAL ;
    PORT
      LAYER Metal3 ;
        RECT  1499.6 529.42 1500 529.82 ;
    END
  END lim_rsp_i[13]
  PIN lim_rsp_i[14]
    DIRECTION INPUT ;
    USE SIGNAL ;
    PORT
      LAYER Metal3 ;
        RECT  1499.6 535.3 1500 535.7 ;
    END
  END lim_rsp_i[14]
  PIN lim_rsp_i[15]
    DIRECTION INPUT ;
    USE SIGNAL ;
    PORT
      LAYER Metal3 ;
        RECT  1499.6 541.18 1500 541.58 ;
    END
  END lim_rsp_i[15]
  PIN lim_rsp_i[16]
    DIRECTION INPUT ;
    USE SIGNAL ;
    PORT
      LAYER Metal3 ;
        RECT  1499.6 547.06 1500 547.46 ;
    END
  END lim_rsp_i[16]
  PIN lim_rsp_i[17]
    DIRECTION INPUT ;
    USE SIGNAL ;
    PORT
      LAYER Metal3 ;
        RECT  1499.6 552.94 1500 553.34 ;
    END
  END lim_rsp_i[17]
  PIN lim_rsp_i[18]
    DIRECTION INPUT ;
    USE SIGNAL ;
    PORT
      LAYER Metal3 ;
        RECT  1499.6 558.82 1500 559.22 ;
    END
  END lim_rsp_i[18]
  PIN lim_rsp_i[19]
    DIRECTION INPUT ;
    USE SIGNAL ;
    PORT
      LAYER Metal3 ;
        RECT  1499.6 564.7 1500 565.1 ;
    END
  END lim_rsp_i[19]
  PIN lim_rsp_i[1]
    DIRECTION INPUT ;
    USE SIGNAL ;
    PORT
      LAYER Metal3 ;
        RECT  1499.6 458.86 1500 459.26 ;
    END
  END lim_rsp_i[1]
  PIN lim_rsp_i[20]
    DIRECTION INPUT ;
    USE SIGNAL ;
    PORT
      LAYER Metal3 ;
        RECT  1499.6 570.58 1500 570.98 ;
    END
  END lim_rsp_i[20]
  PIN lim_rsp_i[21]
    DIRECTION INPUT ;
    USE SIGNAL ;
    PORT
      LAYER Metal3 ;
        RECT  1499.6 576.46 1500 576.86 ;
    END
  END lim_rsp_i[21]
  PIN lim_rsp_i[22]
    DIRECTION INPUT ;
    USE SIGNAL ;
    PORT
      LAYER Metal3 ;
        RECT  1499.6 582.34 1500 582.74 ;
    END
  END lim_rsp_i[22]
  PIN lim_rsp_i[23]
    DIRECTION INPUT ;
    USE SIGNAL ;
    PORT
      LAYER Metal3 ;
        RECT  1499.6 588.22 1500 588.62 ;
    END
  END lim_rsp_i[23]
  PIN lim_rsp_i[24]
    DIRECTION INPUT ;
    USE SIGNAL ;
    PORT
      LAYER Metal3 ;
        RECT  1499.6 594.1 1500 594.5 ;
    END
  END lim_rsp_i[24]
  PIN lim_rsp_i[25]
    DIRECTION INPUT ;
    USE SIGNAL ;
    PORT
      LAYER Metal3 ;
        RECT  1499.6 599.98 1500 600.38 ;
    END
  END lim_rsp_i[25]
  PIN lim_rsp_i[26]
    DIRECTION INPUT ;
    USE SIGNAL ;
    PORT
      LAYER Metal3 ;
        RECT  1499.6 605.86 1500 606.26 ;
    END
  END lim_rsp_i[26]
  PIN lim_rsp_i[27]
    DIRECTION INPUT ;
    USE SIGNAL ;
    PORT
      LAYER Metal3 ;
        RECT  1499.6 611.74 1500 612.14 ;
    END
  END lim_rsp_i[27]
  PIN lim_rsp_i[28]
    DIRECTION INPUT ;
    USE SIGNAL ;
    PORT
      LAYER Metal3 ;
        RECT  1499.6 617.62 1500 618.02 ;
    END
  END lim_rsp_i[28]
  PIN lim_rsp_i[29]
    DIRECTION INPUT ;
    USE SIGNAL ;
    PORT
      LAYER Metal3 ;
        RECT  1499.6 623.5 1500 623.9 ;
    END
  END lim_rsp_i[29]
  PIN lim_rsp_i[2]
    DIRECTION INPUT ;
    USE SIGNAL ;
    PORT
      LAYER Metal3 ;
        RECT  1499.6 464.74 1500 465.14 ;
    END
  END lim_rsp_i[2]
  PIN lim_rsp_i[30]
    DIRECTION INPUT ;
    USE SIGNAL ;
    PORT
      LAYER Metal3 ;
        RECT  1499.6 629.38 1500 629.78 ;
    END
  END lim_rsp_i[30]
  PIN lim_rsp_i[31]
    DIRECTION INPUT ;
    USE SIGNAL ;
    PORT
      LAYER Metal3 ;
        RECT  1499.6 635.26 1500 635.66 ;
    END
  END lim_rsp_i[31]
  PIN lim_rsp_i[32]
    DIRECTION INPUT ;
    USE SIGNAL ;
    PORT
      LAYER Metal3 ;
        RECT  1499.6 641.14 1500 641.54 ;
    END
  END lim_rsp_i[32]
  PIN lim_rsp_i[33]
    DIRECTION INPUT ;
    USE SIGNAL ;
    PORT
      LAYER Metal3 ;
        RECT  1499.6 647.02 1500 647.42 ;
    END
  END lim_rsp_i[33]
  PIN lim_rsp_i[34]
    DIRECTION INPUT ;
    USE SIGNAL ;
    PORT
      LAYER Metal3 ;
        RECT  1499.6 652.9 1500 653.3 ;
    END
  END lim_rsp_i[34]
  PIN lim_rsp_i[35]
    DIRECTION INPUT ;
    USE SIGNAL ;
    PORT
      LAYER Metal3 ;
        RECT  1499.6 658.78 1500 659.18 ;
    END
  END lim_rsp_i[35]
  PIN lim_rsp_i[36]
    DIRECTION INPUT ;
    USE SIGNAL ;
    PORT
      LAYER Metal3 ;
        RECT  1499.6 664.66 1500 665.06 ;
    END
  END lim_rsp_i[36]
  PIN lim_rsp_i[37]
    DIRECTION INPUT ;
    USE SIGNAL ;
    PORT
      LAYER Metal3 ;
        RECT  1499.6 670.54 1500 670.94 ;
    END
  END lim_rsp_i[37]
  PIN lim_rsp_i[38]
    DIRECTION INPUT ;
    USE SIGNAL ;
    PORT
      LAYER Metal3 ;
        RECT  1499.6 676.42 1500 676.82 ;
    END
  END lim_rsp_i[38]
  PIN lim_rsp_i[39]
    DIRECTION INPUT ;
    USE SIGNAL ;
    PORT
      LAYER Metal3 ;
        RECT  1499.6 682.3 1500 682.7 ;
    END
  END lim_rsp_i[39]
  PIN lim_rsp_i[3]
    DIRECTION INPUT ;
    USE SIGNAL ;
    PORT
      LAYER Metal3 ;
        RECT  1499.6 470.62 1500 471.02 ;
    END
  END lim_rsp_i[3]
  PIN lim_rsp_i[40]
    DIRECTION INPUT ;
    USE SIGNAL ;
    PORT
      LAYER Metal3 ;
        RECT  1499.6 688.18 1500 688.58 ;
    END
  END lim_rsp_i[40]
  PIN lim_rsp_i[41]
    DIRECTION INPUT ;
    USE SIGNAL ;
    PORT
      LAYER Metal3 ;
        RECT  1499.6 694.06 1500 694.46 ;
    END
  END lim_rsp_i[41]
  PIN lim_rsp_i[42]
    DIRECTION INPUT ;
    USE SIGNAL ;
    PORT
      LAYER Metal3 ;
        RECT  1499.6 699.94 1500 700.34 ;
    END
  END lim_rsp_i[42]
  PIN lim_rsp_i[43]
    DIRECTION INPUT ;
    USE SIGNAL ;
    PORT
      LAYER Metal3 ;
        RECT  1499.6 705.82 1500 706.22 ;
    END
  END lim_rsp_i[43]
  PIN lim_rsp_i[44]
    DIRECTION INPUT ;
    USE SIGNAL ;
    PORT
      LAYER Metal3 ;
        RECT  1499.6 711.7 1500 712.1 ;
    END
  END lim_rsp_i[44]
  PIN lim_rsp_i[45]
    DIRECTION INPUT ;
    USE SIGNAL ;
    PORT
      LAYER Metal3 ;
        RECT  1499.6 717.58 1500 717.98 ;
    END
  END lim_rsp_i[45]
  PIN lim_rsp_i[46]
    DIRECTION INPUT ;
    USE SIGNAL ;
    PORT
      LAYER Metal3 ;
        RECT  1499.6 723.46 1500 723.86 ;
    END
  END lim_rsp_i[46]
  PIN lim_rsp_i[47]
    DIRECTION INPUT ;
    USE SIGNAL ;
    PORT
      LAYER Metal3 ;
        RECT  1499.6 729.34 1500 729.74 ;
    END
  END lim_rsp_i[47]
  PIN lim_rsp_i[48]
    DIRECTION INPUT ;
    USE SIGNAL ;
    PORT
      LAYER Metal3 ;
        RECT  1499.6 735.22 1500 735.62 ;
    END
  END lim_rsp_i[48]
  PIN lim_rsp_i[49]
    DIRECTION INPUT ;
    USE SIGNAL ;
    PORT
      LAYER Metal3 ;
        RECT  1499.6 741.1 1500 741.5 ;
    END
  END lim_rsp_i[49]
  PIN lim_rsp_i[4]
    DIRECTION INPUT ;
    USE SIGNAL ;
    PORT
      LAYER Metal3 ;
        RECT  1499.6 476.5 1500 476.9 ;
    END
  END lim_rsp_i[4]
  PIN lim_rsp_i[50]
    DIRECTION INPUT ;
    USE SIGNAL ;
    PORT
      LAYER Metal3 ;
        RECT  1499.6 746.98 1500 747.38 ;
    END
  END lim_rsp_i[50]
  PIN lim_rsp_i[51]
    DIRECTION INPUT ;
    USE SIGNAL ;
    PORT
      LAYER Metal3 ;
        RECT  1499.6 752.86 1500 753.26 ;
    END
  END lim_rsp_i[51]
  PIN lim_rsp_i[52]
    DIRECTION INPUT ;
    USE SIGNAL ;
    PORT
      LAYER Metal3 ;
        RECT  1499.6 758.74 1500 759.14 ;
    END
  END lim_rsp_i[52]
  PIN lim_rsp_i[53]
    DIRECTION INPUT ;
    USE SIGNAL ;
    PORT
      LAYER Metal3 ;
        RECT  1499.6 764.62 1500 765.02 ;
    END
  END lim_rsp_i[53]
  PIN lim_rsp_i[54]
    DIRECTION INPUT ;
    USE SIGNAL ;
    PORT
      LAYER Metal3 ;
        RECT  1499.6 770.5 1500 770.9 ;
    END
  END lim_rsp_i[54]
  PIN lim_rsp_i[55]
    DIRECTION INPUT ;
    USE SIGNAL ;
    PORT
      LAYER Metal3 ;
        RECT  1499.6 776.38 1500 776.78 ;
    END
  END lim_rsp_i[55]
  PIN lim_rsp_i[56]
    DIRECTION INPUT ;
    USE SIGNAL ;
    PORT
      LAYER Metal3 ;
        RECT  1499.6 782.26 1500 782.66 ;
    END
  END lim_rsp_i[56]
  PIN lim_rsp_i[57]
    DIRECTION INPUT ;
    USE SIGNAL ;
    PORT
      LAYER Metal3 ;
        RECT  1499.6 788.14 1500 788.54 ;
    END
  END lim_rsp_i[57]
  PIN lim_rsp_i[58]
    DIRECTION INPUT ;
    USE SIGNAL ;
    PORT
      LAYER Metal3 ;
        RECT  1499.6 794.02 1500 794.42 ;
    END
  END lim_rsp_i[58]
  PIN lim_rsp_i[59]
    DIRECTION INPUT ;
    USE SIGNAL ;
    PORT
      LAYER Metal3 ;
        RECT  1499.6 799.9 1500 800.3 ;
    END
  END lim_rsp_i[59]
  PIN lim_rsp_i[5]
    DIRECTION INPUT ;
    USE SIGNAL ;
    PORT
      LAYER Metal3 ;
        RECT  1499.6 482.38 1500 482.78 ;
    END
  END lim_rsp_i[5]
  PIN lim_rsp_i[60]
    DIRECTION INPUT ;
    USE SIGNAL ;
    PORT
      LAYER Metal3 ;
        RECT  1499.6 805.78 1500 806.18 ;
    END
  END lim_rsp_i[60]
  PIN lim_rsp_i[61]
    DIRECTION INPUT ;
    USE SIGNAL ;
    PORT
      LAYER Metal3 ;
        RECT  1499.6 811.66 1500 812.06 ;
    END
  END lim_rsp_i[61]
  PIN lim_rsp_i[62]
    DIRECTION INPUT ;
    USE SIGNAL ;
    PORT
      LAYER Metal3 ;
        RECT  1499.6 817.54 1500 817.94 ;
    END
  END lim_rsp_i[62]
  PIN lim_rsp_i[63]
    DIRECTION INPUT ;
    USE SIGNAL ;
    PORT
      LAYER Metal3 ;
        RECT  1499.6 823.42 1500 823.82 ;
    END
  END lim_rsp_i[63]
  PIN lim_rsp_i[6]
    DIRECTION INPUT ;
    USE SIGNAL ;
    PORT
      LAYER Metal3 ;
        RECT  1499.6 488.26 1500 488.66 ;
    END
  END lim_rsp_i[6]
  PIN lim_rsp_i[7]
    DIRECTION INPUT ;
    USE SIGNAL ;
    PORT
      LAYER Metal3 ;
        RECT  1499.6 494.14 1500 494.54 ;
    END
  END lim_rsp_i[7]
  PIN lim_rsp_i[8]
    DIRECTION INPUT ;
    USE SIGNAL ;
    PORT
      LAYER Metal3 ;
        RECT  1499.6 500.02 1500 500.42 ;
    END
  END lim_rsp_i[8]
  PIN lim_rsp_i[9]
    DIRECTION INPUT ;
    USE SIGNAL ;
    PORT
      LAYER Metal3 ;
        RECT  1499.6 505.9 1500 506.3 ;
    END
  END lim_rsp_i[9]
  PIN maint_done_o
    DIRECTION OUTPUT ;
    USE SIGNAL ;
    PORT
      LAYER Metal2 ;
        RECT  1078.36 0 1078.76 0.4 ;
    END
  END maint_done_o
  PIN maint_i.base[0]
    DIRECTION INPUT ;
    USE SIGNAL ;
    PORT
      LAYER Metal2 ;
        RECT  1080.28 0 1080.68 0.4 ;
    END
  END maint_i.base[0]
  PIN maint_i.base[10]
    DIRECTION INPUT ;
    USE SIGNAL ;
    PORT
      LAYER Metal2 ;
        RECT  1101.4 0 1101.8 0.4 ;
    END
  END maint_i.base[10]
  PIN maint_i.base[11]
    DIRECTION INPUT ;
    USE SIGNAL ;
    PORT
      LAYER Metal2 ;
        RECT  1103.32 0 1103.72 0.4 ;
    END
  END maint_i.base[11]
  PIN maint_i.base[12]
    DIRECTION INPUT ;
    USE SIGNAL ;
    PORT
      LAYER Metal2 ;
        RECT  1105.24 0 1105.64 0.4 ;
    END
  END maint_i.base[12]
  PIN maint_i.base[13]
    DIRECTION INPUT ;
    USE SIGNAL ;
    PORT
      LAYER Metal2 ;
        RECT  1107.16 0 1107.56 0.4 ;
    END
  END maint_i.base[13]
  PIN maint_i.base[14]
    DIRECTION INPUT ;
    USE SIGNAL ;
    PORT
      LAYER Metal2 ;
        RECT  1109.08 0 1109.48 0.4 ;
    END
  END maint_i.base[14]
  PIN maint_i.base[15]
    DIRECTION INPUT ;
    USE SIGNAL ;
    PORT
      LAYER Metal2 ;
        RECT  1111 0 1111.4 0.4 ;
    END
  END maint_i.base[15]
  PIN maint_i.base[16]
    DIRECTION INPUT ;
    USE SIGNAL ;
    PORT
      LAYER Metal2 ;
        RECT  1112.92 0 1113.32 0.4 ;
    END
  END maint_i.base[16]
  PIN maint_i.base[17]
    DIRECTION INPUT ;
    USE SIGNAL ;
    PORT
      LAYER Metal2 ;
        RECT  1114.84 0 1115.24 0.4 ;
    END
  END maint_i.base[17]
  PIN maint_i.base[18]
    DIRECTION INPUT ;
    USE SIGNAL ;
    PORT
      LAYER Metal2 ;
        RECT  1116.76 0 1117.16 0.4 ;
    END
  END maint_i.base[18]
  PIN maint_i.base[19]
    DIRECTION INPUT ;
    USE SIGNAL ;
    PORT
      LAYER Metal2 ;
        RECT  1118.68 0 1119.08 0.4 ;
    END
  END maint_i.base[19]
  PIN maint_i.base[1]
    DIRECTION INPUT ;
    USE SIGNAL ;
    PORT
      LAYER Metal2 ;
        RECT  1083.16 0 1083.56 0.4 ;
    END
  END maint_i.base[1]
  PIN maint_i.base[20]
    DIRECTION INPUT ;
    USE SIGNAL ;
    PORT
      LAYER Metal2 ;
        RECT  1120.6 0 1121 0.4 ;
    END
  END maint_i.base[20]
  PIN maint_i.base[21]
    DIRECTION INPUT ;
    USE SIGNAL ;
    PORT
      LAYER Metal2 ;
        RECT  1122.52 0 1122.92 0.4 ;
    END
  END maint_i.base[21]
  PIN maint_i.base[22]
    DIRECTION INPUT ;
    USE SIGNAL ;
    PORT
      LAYER Metal2 ;
        RECT  1124.44 0 1124.84 0.4 ;
    END
  END maint_i.base[22]
  PIN maint_i.base[23]
    DIRECTION INPUT ;
    USE SIGNAL ;
    PORT
      LAYER Metal2 ;
        RECT  1126.36 0 1126.76 0.4 ;
    END
  END maint_i.base[23]
  PIN maint_i.base[24]
    DIRECTION INPUT ;
    USE SIGNAL ;
    PORT
      LAYER Metal2 ;
        RECT  1128.28 0 1128.68 0.4 ;
    END
  END maint_i.base[24]
  PIN maint_i.base[25]
    DIRECTION INPUT ;
    USE SIGNAL ;
    PORT
      LAYER Metal2 ;
        RECT  1130.2 0 1130.6 0.4 ;
    END
  END maint_i.base[25]
  PIN maint_i.base[26]
    DIRECTION INPUT ;
    USE SIGNAL ;
    PORT
      LAYER Metal2 ;
        RECT  1132.12 0 1132.52 0.4 ;
    END
  END maint_i.base[26]
  PIN maint_i.base[27]
    DIRECTION INPUT ;
    USE SIGNAL ;
    PORT
      LAYER Metal2 ;
        RECT  1134.04 0 1134.44 0.4 ;
    END
  END maint_i.base[27]
  PIN maint_i.base[28]
    DIRECTION INPUT ;
    USE SIGNAL ;
    PORT
      LAYER Metal2 ;
        RECT  1135.96 0 1136.36 0.4 ;
    END
  END maint_i.base[28]
  PIN maint_i.base[29]
    DIRECTION INPUT ;
    USE SIGNAL ;
    PORT
      LAYER Metal2 ;
        RECT  1137.88 0 1138.28 0.4 ;
    END
  END maint_i.base[29]
  PIN maint_i.base[2]
    DIRECTION INPUT ;
    USE SIGNAL ;
    PORT
      LAYER Metal2 ;
        RECT  1086.04 0 1086.44 0.4 ;
    END
  END maint_i.base[2]
  PIN maint_i.base[30]
    DIRECTION INPUT ;
    USE SIGNAL ;
    PORT
      LAYER Metal2 ;
        RECT  1139.8 0 1140.2 0.4 ;
    END
  END maint_i.base[30]
  PIN maint_i.base[31]
    DIRECTION INPUT ;
    USE SIGNAL ;
    PORT
      LAYER Metal2 ;
        RECT  1141.72 0 1142.12 0.4 ;
    END
  END maint_i.base[31]
  PIN maint_i.base[32]
    DIRECTION INPUT ;
    USE SIGNAL ;
    PORT
      LAYER Metal2 ;
        RECT  1143.64 0 1144.04 0.4 ;
    END
  END maint_i.base[32]
  PIN maint_i.base[33]
    DIRECTION INPUT ;
    USE SIGNAL ;
    PORT
      LAYER Metal2 ;
        RECT  1145.56 0 1145.96 0.4 ;
    END
  END maint_i.base[33]
  PIN maint_i.base[34]
    DIRECTION INPUT ;
    USE SIGNAL ;
    PORT
      LAYER Metal2 ;
        RECT  1147.48 0 1147.88 0.4 ;
    END
  END maint_i.base[34]
  PIN maint_i.base[35]
    DIRECTION INPUT ;
    USE SIGNAL ;
    PORT
      LAYER Metal2 ;
        RECT  1149.4 0 1149.8 0.4 ;
    END
  END maint_i.base[35]
  PIN maint_i.base[36]
    DIRECTION INPUT ;
    USE SIGNAL ;
    PORT
      LAYER Metal2 ;
        RECT  1151.32 0 1151.72 0.4 ;
    END
  END maint_i.base[36]
  PIN maint_i.base[37]
    DIRECTION INPUT ;
    USE SIGNAL ;
    PORT
      LAYER Metal2 ;
        RECT  1153.24 0 1153.64 0.4 ;
    END
  END maint_i.base[37]
  PIN maint_i.base[38]
    DIRECTION INPUT ;
    USE SIGNAL ;
    PORT
      LAYER Metal2 ;
        RECT  1155.16 0 1155.56 0.4 ;
    END
  END maint_i.base[38]
  PIN maint_i.base[39]
    DIRECTION INPUT ;
    USE SIGNAL ;
    PORT
      LAYER Metal2 ;
        RECT  1157.08 0 1157.48 0.4 ;
    END
  END maint_i.base[39]
  PIN maint_i.base[3]
    DIRECTION INPUT ;
    USE SIGNAL ;
    PORT
      LAYER Metal2 ;
        RECT  1087.96 0 1088.36 0.4 ;
    END
  END maint_i.base[3]
  PIN maint_i.base[40]
    DIRECTION INPUT ;
    USE SIGNAL ;
    PORT
      LAYER Metal2 ;
        RECT  1159 0 1159.4 0.4 ;
    END
  END maint_i.base[40]
  PIN maint_i.base[41]
    DIRECTION INPUT ;
    USE SIGNAL ;
    PORT
      LAYER Metal2 ;
        RECT  1160.92 0 1161.32 0.4 ;
    END
  END maint_i.base[41]
  PIN maint_i.base[42]
    DIRECTION INPUT ;
    USE SIGNAL ;
    PORT
      LAYER Metal2 ;
        RECT  1162.84 0 1163.24 0.4 ;
    END
  END maint_i.base[42]
  PIN maint_i.base[43]
    DIRECTION INPUT ;
    USE SIGNAL ;
    PORT
      LAYER Metal2 ;
        RECT  1164.76 0 1165.16 0.4 ;
    END
  END maint_i.base[43]
  PIN maint_i.base[44]
    DIRECTION INPUT ;
    USE SIGNAL ;
    PORT
      LAYER Metal2 ;
        RECT  1166.68 0 1167.08 0.4 ;
    END
  END maint_i.base[44]
  PIN maint_i.base[45]
    DIRECTION INPUT ;
    USE SIGNAL ;
    PORT
      LAYER Metal2 ;
        RECT  1168.6 0 1169 0.4 ;
    END
  END maint_i.base[45]
  PIN maint_i.base[46]
    DIRECTION INPUT ;
    USE SIGNAL ;
    PORT
      LAYER Metal2 ;
        RECT  1170.52 0 1170.92 0.4 ;
    END
  END maint_i.base[46]
  PIN maint_i.base[47]
    DIRECTION INPUT ;
    USE SIGNAL ;
    PORT
      LAYER Metal2 ;
        RECT  1172.44 0 1172.84 0.4 ;
    END
  END maint_i.base[47]
  PIN maint_i.base[48]
    DIRECTION INPUT ;
    USE SIGNAL ;
    PORT
      LAYER Metal2 ;
        RECT  1174.36 0 1174.76 0.4 ;
    END
  END maint_i.base[48]
  PIN maint_i.base[49]
    DIRECTION INPUT ;
    USE SIGNAL ;
    PORT
      LAYER Metal2 ;
        RECT  1176.28 0 1176.68 0.4 ;
    END
  END maint_i.base[49]
  PIN maint_i.base[4]
    DIRECTION INPUT ;
    USE SIGNAL ;
    PORT
      LAYER Metal2 ;
        RECT  1089.88 0 1090.28 0.4 ;
    END
  END maint_i.base[4]
  PIN maint_i.base[50]
    DIRECTION INPUT ;
    USE SIGNAL ;
    PORT
      LAYER Metal2 ;
        RECT  1178.2 0 1178.6 0.4 ;
    END
  END maint_i.base[50]
  PIN maint_i.base[51]
    DIRECTION INPUT ;
    USE SIGNAL ;
    PORT
      LAYER Metal2 ;
        RECT  1180.12 0 1180.52 0.4 ;
    END
  END maint_i.base[51]
  PIN maint_i.base[52]
    DIRECTION INPUT ;
    USE SIGNAL ;
    PORT
      LAYER Metal2 ;
        RECT  1182.04 0 1182.44 0.4 ;
    END
  END maint_i.base[52]
  PIN maint_i.base[53]
    DIRECTION INPUT ;
    USE SIGNAL ;
    PORT
      LAYER Metal2 ;
        RECT  1183.96 0 1184.36 0.4 ;
    END
  END maint_i.base[53]
  PIN maint_i.base[54]
    DIRECTION INPUT ;
    USE SIGNAL ;
    PORT
      LAYER Metal2 ;
        RECT  1185.88 0 1186.28 0.4 ;
    END
  END maint_i.base[54]
  PIN maint_i.base[55]
    DIRECTION INPUT ;
    USE SIGNAL ;
    PORT
      LAYER Metal2 ;
        RECT  1187.8 0 1188.2 0.4 ;
    END
  END maint_i.base[55]
  PIN maint_i.base[56]
    DIRECTION INPUT ;
    USE SIGNAL ;
    PORT
      LAYER Metal2 ;
        RECT  1189.72 0 1190.12 0.4 ;
    END
  END maint_i.base[56]
  PIN maint_i.base[57]
    DIRECTION INPUT ;
    USE SIGNAL ;
    PORT
      LAYER Metal2 ;
        RECT  1191.64 0 1192.04 0.4 ;
    END
  END maint_i.base[57]
  PIN maint_i.base[58]
    DIRECTION INPUT ;
    USE SIGNAL ;
    PORT
      LAYER Metal2 ;
        RECT  1193.56 0 1193.96 0.4 ;
    END
  END maint_i.base[58]
  PIN maint_i.base[59]
    DIRECTION INPUT ;
    USE SIGNAL ;
    PORT
      LAYER Metal2 ;
        RECT  1195.48 0 1195.88 0.4 ;
    END
  END maint_i.base[59]
  PIN maint_i.base[5]
    DIRECTION INPUT ;
    USE SIGNAL ;
    PORT
      LAYER Metal2 ;
        RECT  1091.8 0 1092.2 0.4 ;
    END
  END maint_i.base[5]
  PIN maint_i.base[60]
    DIRECTION INPUT ;
    USE SIGNAL ;
    PORT
      LAYER Metal2 ;
        RECT  1197.4 0 1197.8 0.4 ;
    END
  END maint_i.base[60]
  PIN maint_i.base[61]
    DIRECTION INPUT ;
    USE SIGNAL ;
    PORT
      LAYER Metal2 ;
        RECT  1199.32 0 1199.72 0.4 ;
    END
  END maint_i.base[61]
  PIN maint_i.base[62]
    DIRECTION INPUT ;
    USE SIGNAL ;
    PORT
      LAYER Metal2 ;
        RECT  1201.24 0 1201.64 0.4 ;
    END
  END maint_i.base[62]
  PIN maint_i.base[63]
    DIRECTION INPUT ;
    USE SIGNAL ;
    PORT
      LAYER Metal2 ;
        RECT  1203.16 0 1203.56 0.4 ;
    END
  END maint_i.base[63]
  PIN maint_i.base[6]
    DIRECTION INPUT ;
    USE SIGNAL ;
    PORT
      LAYER Metal2 ;
        RECT  1093.72 0 1094.12 0.4 ;
    END
  END maint_i.base[6]
  PIN maint_i.base[7]
    DIRECTION INPUT ;
    USE SIGNAL ;
    PORT
      LAYER Metal2 ;
        RECT  1095.64 0 1096.04 0.4 ;
    END
  END maint_i.base[7]
  PIN maint_i.base[8]
    DIRECTION INPUT ;
    USE SIGNAL ;
    PORT
      LAYER Metal2 ;
        RECT  1097.56 0 1097.96 0.4 ;
    END
  END maint_i.base[8]
  PIN maint_i.base[9]
    DIRECTION INPUT ;
    USE SIGNAL ;
    PORT
      LAYER Metal2 ;
        RECT  1099.48 0 1099.88 0.4 ;
    END
  END maint_i.base[9]
  PIN maint_i.kind[0]
    DIRECTION INPUT ;
    USE SIGNAL ;
    PORT
      LAYER Metal2 ;
        RECT  1081.24 0 1081.64 0.4 ;
    END
  END maint_i.kind[0]
  PIN maint_i.kind[1]
    DIRECTION INPUT ;
    USE SIGNAL ;
    PORT
      LAYER Metal2 ;
        RECT  1084.12 0 1084.52 0.4 ;
    END
  END maint_i.kind[1]
  PIN maint_i.length[0]
    DIRECTION INPUT ;
    USE SIGNAL ;
    PORT
      LAYER Metal2 ;
        RECT  1082.2 0 1082.6 0.4 ;
    END
  END maint_i.length[0]
  PIN maint_i.length[10]
    DIRECTION INPUT ;
    USE SIGNAL ;
    PORT
      LAYER Metal2 ;
        RECT  1102.36 0 1102.76 0.4 ;
    END
  END maint_i.length[10]
  PIN maint_i.length[11]
    DIRECTION INPUT ;
    USE SIGNAL ;
    PORT
      LAYER Metal2 ;
        RECT  1104.28 0 1104.68 0.4 ;
    END
  END maint_i.length[11]
  PIN maint_i.length[12]
    DIRECTION INPUT ;
    USE SIGNAL ;
    PORT
      LAYER Metal2 ;
        RECT  1106.2 0 1106.6 0.4 ;
    END
  END maint_i.length[12]
  PIN maint_i.length[13]
    DIRECTION INPUT ;
    USE SIGNAL ;
    PORT
      LAYER Metal2 ;
        RECT  1108.12 0 1108.52 0.4 ;
    END
  END maint_i.length[13]
  PIN maint_i.length[14]
    DIRECTION INPUT ;
    USE SIGNAL ;
    PORT
      LAYER Metal2 ;
        RECT  1110.04 0 1110.44 0.4 ;
    END
  END maint_i.length[14]
  PIN maint_i.length[15]
    DIRECTION INPUT ;
    USE SIGNAL ;
    PORT
      LAYER Metal2 ;
        RECT  1111.96 0 1112.36 0.4 ;
    END
  END maint_i.length[15]
  PIN maint_i.length[16]
    DIRECTION INPUT ;
    USE SIGNAL ;
    PORT
      LAYER Metal2 ;
        RECT  1113.88 0 1114.28 0.4 ;
    END
  END maint_i.length[16]
  PIN maint_i.length[17]
    DIRECTION INPUT ;
    USE SIGNAL ;
    PORT
      LAYER Metal2 ;
        RECT  1115.8 0 1116.2 0.4 ;
    END
  END maint_i.length[17]
  PIN maint_i.length[18]
    DIRECTION INPUT ;
    USE SIGNAL ;
    PORT
      LAYER Metal2 ;
        RECT  1117.72 0 1118.12 0.4 ;
    END
  END maint_i.length[18]
  PIN maint_i.length[19]
    DIRECTION INPUT ;
    USE SIGNAL ;
    PORT
      LAYER Metal2 ;
        RECT  1119.64 0 1120.04 0.4 ;
    END
  END maint_i.length[19]
  PIN maint_i.length[1]
    DIRECTION INPUT ;
    USE SIGNAL ;
    PORT
      LAYER Metal2 ;
        RECT  1085.08 0 1085.48 0.4 ;
    END
  END maint_i.length[1]
  PIN maint_i.length[20]
    DIRECTION INPUT ;
    USE SIGNAL ;
    PORT
      LAYER Metal2 ;
        RECT  1121.56 0 1121.96 0.4 ;
    END
  END maint_i.length[20]
  PIN maint_i.length[21]
    DIRECTION INPUT ;
    USE SIGNAL ;
    PORT
      LAYER Metal2 ;
        RECT  1123.48 0 1123.88 0.4 ;
    END
  END maint_i.length[21]
  PIN maint_i.length[22]
    DIRECTION INPUT ;
    USE SIGNAL ;
    PORT
      LAYER Metal2 ;
        RECT  1125.4 0 1125.8 0.4 ;
    END
  END maint_i.length[22]
  PIN maint_i.length[23]
    DIRECTION INPUT ;
    USE SIGNAL ;
    PORT
      LAYER Metal2 ;
        RECT  1127.32 0 1127.72 0.4 ;
    END
  END maint_i.length[23]
  PIN maint_i.length[24]
    DIRECTION INPUT ;
    USE SIGNAL ;
    PORT
      LAYER Metal2 ;
        RECT  1129.24 0 1129.64 0.4 ;
    END
  END maint_i.length[24]
  PIN maint_i.length[25]
    DIRECTION INPUT ;
    USE SIGNAL ;
    PORT
      LAYER Metal2 ;
        RECT  1131.16 0 1131.56 0.4 ;
    END
  END maint_i.length[25]
  PIN maint_i.length[26]
    DIRECTION INPUT ;
    USE SIGNAL ;
    PORT
      LAYER Metal2 ;
        RECT  1133.08 0 1133.48 0.4 ;
    END
  END maint_i.length[26]
  PIN maint_i.length[27]
    DIRECTION INPUT ;
    USE SIGNAL ;
    PORT
      LAYER Metal2 ;
        RECT  1135 0 1135.4 0.4 ;
    END
  END maint_i.length[27]
  PIN maint_i.length[28]
    DIRECTION INPUT ;
    USE SIGNAL ;
    PORT
      LAYER Metal2 ;
        RECT  1136.92 0 1137.32 0.4 ;
    END
  END maint_i.length[28]
  PIN maint_i.length[29]
    DIRECTION INPUT ;
    USE SIGNAL ;
    PORT
      LAYER Metal2 ;
        RECT  1138.84 0 1139.24 0.4 ;
    END
  END maint_i.length[29]
  PIN maint_i.length[2]
    DIRECTION INPUT ;
    USE SIGNAL ;
    PORT
      LAYER Metal2 ;
        RECT  1087 0 1087.4 0.4 ;
    END
  END maint_i.length[2]
  PIN maint_i.length[30]
    DIRECTION INPUT ;
    USE SIGNAL ;
    PORT
      LAYER Metal2 ;
        RECT  1140.76 0 1141.16 0.4 ;
    END
  END maint_i.length[30]
  PIN maint_i.length[31]
    DIRECTION INPUT ;
    USE SIGNAL ;
    PORT
      LAYER Metal2 ;
        RECT  1142.68 0 1143.08 0.4 ;
    END
  END maint_i.length[31]
  PIN maint_i.length[32]
    DIRECTION INPUT ;
    USE SIGNAL ;
    PORT
      LAYER Metal2 ;
        RECT  1144.6 0 1145 0.4 ;
    END
  END maint_i.length[32]
  PIN maint_i.length[33]
    DIRECTION INPUT ;
    USE SIGNAL ;
    PORT
      LAYER Metal2 ;
        RECT  1146.52 0 1146.92 0.4 ;
    END
  END maint_i.length[33]
  PIN maint_i.length[34]
    DIRECTION INPUT ;
    USE SIGNAL ;
    PORT
      LAYER Metal2 ;
        RECT  1148.44 0 1148.84 0.4 ;
    END
  END maint_i.length[34]
  PIN maint_i.length[35]
    DIRECTION INPUT ;
    USE SIGNAL ;
    PORT
      LAYER Metal2 ;
        RECT  1150.36 0 1150.76 0.4 ;
    END
  END maint_i.length[35]
  PIN maint_i.length[36]
    DIRECTION INPUT ;
    USE SIGNAL ;
    PORT
      LAYER Metal2 ;
        RECT  1152.28 0 1152.68 0.4 ;
    END
  END maint_i.length[36]
  PIN maint_i.length[37]
    DIRECTION INPUT ;
    USE SIGNAL ;
    PORT
      LAYER Metal2 ;
        RECT  1154.2 0 1154.6 0.4 ;
    END
  END maint_i.length[37]
  PIN maint_i.length[38]
    DIRECTION INPUT ;
    USE SIGNAL ;
    PORT
      LAYER Metal2 ;
        RECT  1156.12 0 1156.52 0.4 ;
    END
  END maint_i.length[38]
  PIN maint_i.length[39]
    DIRECTION INPUT ;
    USE SIGNAL ;
    PORT
      LAYER Metal2 ;
        RECT  1158.04 0 1158.44 0.4 ;
    END
  END maint_i.length[39]
  PIN maint_i.length[3]
    DIRECTION INPUT ;
    USE SIGNAL ;
    PORT
      LAYER Metal2 ;
        RECT  1088.92 0 1089.32 0.4 ;
    END
  END maint_i.length[3]
  PIN maint_i.length[40]
    DIRECTION INPUT ;
    USE SIGNAL ;
    PORT
      LAYER Metal2 ;
        RECT  1159.96 0 1160.36 0.4 ;
    END
  END maint_i.length[40]
  PIN maint_i.length[41]
    DIRECTION INPUT ;
    USE SIGNAL ;
    PORT
      LAYER Metal2 ;
        RECT  1161.88 0 1162.28 0.4 ;
    END
  END maint_i.length[41]
  PIN maint_i.length[42]
    DIRECTION INPUT ;
    USE SIGNAL ;
    PORT
      LAYER Metal2 ;
        RECT  1163.8 0 1164.2 0.4 ;
    END
  END maint_i.length[42]
  PIN maint_i.length[43]
    DIRECTION INPUT ;
    USE SIGNAL ;
    PORT
      LAYER Metal2 ;
        RECT  1165.72 0 1166.12 0.4 ;
    END
  END maint_i.length[43]
  PIN maint_i.length[44]
    DIRECTION INPUT ;
    USE SIGNAL ;
    PORT
      LAYER Metal2 ;
        RECT  1167.64 0 1168.04 0.4 ;
    END
  END maint_i.length[44]
  PIN maint_i.length[45]
    DIRECTION INPUT ;
    USE SIGNAL ;
    PORT
      LAYER Metal2 ;
        RECT  1169.56 0 1169.96 0.4 ;
    END
  END maint_i.length[45]
  PIN maint_i.length[46]
    DIRECTION INPUT ;
    USE SIGNAL ;
    PORT
      LAYER Metal2 ;
        RECT  1171.48 0 1171.88 0.4 ;
    END
  END maint_i.length[46]
  PIN maint_i.length[47]
    DIRECTION INPUT ;
    USE SIGNAL ;
    PORT
      LAYER Metal2 ;
        RECT  1173.4 0 1173.8 0.4 ;
    END
  END maint_i.length[47]
  PIN maint_i.length[48]
    DIRECTION INPUT ;
    USE SIGNAL ;
    PORT
      LAYER Metal2 ;
        RECT  1175.32 0 1175.72 0.4 ;
    END
  END maint_i.length[48]
  PIN maint_i.length[49]
    DIRECTION INPUT ;
    USE SIGNAL ;
    PORT
      LAYER Metal2 ;
        RECT  1177.24 0 1177.64 0.4 ;
    END
  END maint_i.length[49]
  PIN maint_i.length[4]
    DIRECTION INPUT ;
    USE SIGNAL ;
    PORT
      LAYER Metal2 ;
        RECT  1090.84 0 1091.24 0.4 ;
    END
  END maint_i.length[4]
  PIN maint_i.length[50]
    DIRECTION INPUT ;
    USE SIGNAL ;
    PORT
      LAYER Metal2 ;
        RECT  1179.16 0 1179.56 0.4 ;
    END
  END maint_i.length[50]
  PIN maint_i.length[51]
    DIRECTION INPUT ;
    USE SIGNAL ;
    PORT
      LAYER Metal2 ;
        RECT  1181.08 0 1181.48 0.4 ;
    END
  END maint_i.length[51]
  PIN maint_i.length[52]
    DIRECTION INPUT ;
    USE SIGNAL ;
    PORT
      LAYER Metal2 ;
        RECT  1183 0 1183.4 0.4 ;
    END
  END maint_i.length[52]
  PIN maint_i.length[53]
    DIRECTION INPUT ;
    USE SIGNAL ;
    PORT
      LAYER Metal2 ;
        RECT  1184.92 0 1185.32 0.4 ;
    END
  END maint_i.length[53]
  PIN maint_i.length[54]
    DIRECTION INPUT ;
    USE SIGNAL ;
    PORT
      LAYER Metal2 ;
        RECT  1186.84 0 1187.24 0.4 ;
    END
  END maint_i.length[54]
  PIN maint_i.length[55]
    DIRECTION INPUT ;
    USE SIGNAL ;
    PORT
      LAYER Metal2 ;
        RECT  1188.76 0 1189.16 0.4 ;
    END
  END maint_i.length[55]
  PIN maint_i.length[56]
    DIRECTION INPUT ;
    USE SIGNAL ;
    PORT
      LAYER Metal2 ;
        RECT  1190.68 0 1191.08 0.4 ;
    END
  END maint_i.length[56]
  PIN maint_i.length[57]
    DIRECTION INPUT ;
    USE SIGNAL ;
    PORT
      LAYER Metal2 ;
        RECT  1192.6 0 1193 0.4 ;
    END
  END maint_i.length[57]
  PIN maint_i.length[58]
    DIRECTION INPUT ;
    USE SIGNAL ;
    PORT
      LAYER Metal2 ;
        RECT  1194.52 0 1194.92 0.4 ;
    END
  END maint_i.length[58]
  PIN maint_i.length[59]
    DIRECTION INPUT ;
    USE SIGNAL ;
    PORT
      LAYER Metal2 ;
        RECT  1196.44 0 1196.84 0.4 ;
    END
  END maint_i.length[59]
  PIN maint_i.length[5]
    DIRECTION INPUT ;
    USE SIGNAL ;
    PORT
      LAYER Metal2 ;
        RECT  1092.76 0 1093.16 0.4 ;
    END
  END maint_i.length[5]
  PIN maint_i.length[60]
    DIRECTION INPUT ;
    USE SIGNAL ;
    PORT
      LAYER Metal2 ;
        RECT  1198.36 0 1198.76 0.4 ;
    END
  END maint_i.length[60]
  PIN maint_i.length[61]
    DIRECTION INPUT ;
    USE SIGNAL ;
    PORT
      LAYER Metal2 ;
        RECT  1200.28 0 1200.68 0.4 ;
    END
  END maint_i.length[61]
  PIN maint_i.length[62]
    DIRECTION INPUT ;
    USE SIGNAL ;
    PORT
      LAYER Metal2 ;
        RECT  1202.2 0 1202.6 0.4 ;
    END
  END maint_i.length[62]
  PIN maint_i.length[63]
    DIRECTION INPUT ;
    USE SIGNAL ;
    PORT
      LAYER Metal2 ;
        RECT  1204.12 0 1204.52 0.4 ;
    END
  END maint_i.length[63]
  PIN maint_i.length[6]
    DIRECTION INPUT ;
    USE SIGNAL ;
    PORT
      LAYER Metal2 ;
        RECT  1094.68 0 1095.08 0.4 ;
    END
  END maint_i.length[6]
  PIN maint_i.length[7]
    DIRECTION INPUT ;
    USE SIGNAL ;
    PORT
      LAYER Metal2 ;
        RECT  1096.6 0 1097 0.4 ;
    END
  END maint_i.length[7]
  PIN maint_i.length[8]
    DIRECTION INPUT ;
    USE SIGNAL ;
    PORT
      LAYER Metal2 ;
        RECT  1098.52 0 1098.92 0.4 ;
    END
  END maint_i.length[8]
  PIN maint_i.length[9]
    DIRECTION INPUT ;
    USE SIGNAL ;
    PORT
      LAYER Metal2 ;
        RECT  1100.44 0 1100.84 0.4 ;
    END
  END maint_i.length[9]
  PIN maint_i.valid
    DIRECTION INPUT ;
    USE SIGNAL ;
    PORT
      LAYER Metal2 ;
        RECT  1079.32 0 1079.72 0.4 ;
    END
  END maint_i.valid
  PIN mem_ready_i
    DIRECTION INPUT ;
    USE SIGNAL ;
    PORT
      LAYER Metal2 ;
        RECT  1014.04 0 1014.44 0.4 ;
    END
  END mem_ready_i
  PIN mem_req_o.address[0]
    DIRECTION OUTPUT ;
    USE SIGNAL ;
    PORT
      LAYER Metal2 ;
        RECT  919.96 0 920.36 0.4 ;
    END
  END mem_req_o.address[0]
  PIN mem_req_o.address[10]
    DIRECTION OUTPUT ;
    USE SIGNAL ;
    PORT
      LAYER Metal2 ;
        RECT  941.08 0 941.48 0.4 ;
    END
  END mem_req_o.address[10]
  PIN mem_req_o.address[11]
    DIRECTION OUTPUT ;
    USE SIGNAL ;
    PORT
      LAYER Metal2 ;
        RECT  943 0 943.4 0.4 ;
    END
  END mem_req_o.address[11]
  PIN mem_req_o.address[12]
    DIRECTION OUTPUT ;
    USE SIGNAL ;
    PORT
      LAYER Metal2 ;
        RECT  944.92 0 945.32 0.4 ;
    END
  END mem_req_o.address[12]
  PIN mem_req_o.address[13]
    DIRECTION OUTPUT ;
    USE SIGNAL ;
    PORT
      LAYER Metal2 ;
        RECT  946.84 0 947.24 0.4 ;
    END
  END mem_req_o.address[13]
  PIN mem_req_o.address[14]
    DIRECTION OUTPUT ;
    USE SIGNAL ;
    PORT
      LAYER Metal2 ;
        RECT  948.76 0 949.16 0.4 ;
    END
  END mem_req_o.address[14]
  PIN mem_req_o.address[15]
    DIRECTION OUTPUT ;
    USE SIGNAL ;
    PORT
      LAYER Metal2 ;
        RECT  950.68 0 951.08 0.4 ;
    END
  END mem_req_o.address[15]
  PIN mem_req_o.address[16]
    DIRECTION OUTPUT ;
    USE SIGNAL ;
    PORT
      LAYER Metal2 ;
        RECT  952.6 0 953 0.4 ;
    END
  END mem_req_o.address[16]
  PIN mem_req_o.address[17]
    DIRECTION OUTPUT ;
    USE SIGNAL ;
    PORT
      LAYER Metal2 ;
        RECT  954.52 0 954.92 0.4 ;
    END
  END mem_req_o.address[17]
  PIN mem_req_o.address[18]
    DIRECTION OUTPUT ;
    USE SIGNAL ;
    PORT
      LAYER Metal2 ;
        RECT  956.44 0 956.84 0.4 ;
    END
  END mem_req_o.address[18]
  PIN mem_req_o.address[19]
    DIRECTION OUTPUT ;
    USE SIGNAL ;
    PORT
      LAYER Metal2 ;
        RECT  958.36 0 958.76 0.4 ;
    END
  END mem_req_o.address[19]
  PIN mem_req_o.address[1]
    DIRECTION OUTPUT ;
    USE SIGNAL ;
    PORT
      LAYER Metal2 ;
        RECT  922.84 0 923.24 0.4 ;
    END
  END mem_req_o.address[1]
  PIN mem_req_o.address[20]
    DIRECTION OUTPUT ;
    USE SIGNAL ;
    PORT
      LAYER Metal2 ;
        RECT  960.28 0 960.68 0.4 ;
    END
  END mem_req_o.address[20]
  PIN mem_req_o.address[21]
    DIRECTION OUTPUT ;
    USE SIGNAL ;
    PORT
      LAYER Metal2 ;
        RECT  962.2 0 962.6 0.4 ;
    END
  END mem_req_o.address[21]
  PIN mem_req_o.address[22]
    DIRECTION OUTPUT ;
    USE SIGNAL ;
    PORT
      LAYER Metal2 ;
        RECT  964.12 0 964.52 0.4 ;
    END
  END mem_req_o.address[22]
  PIN mem_req_o.address[23]
    DIRECTION OUTPUT ;
    USE SIGNAL ;
    PORT
      LAYER Metal2 ;
        RECT  966.04 0 966.44 0.4 ;
    END
  END mem_req_o.address[23]
  PIN mem_req_o.address[24]
    DIRECTION OUTPUT ;
    USE SIGNAL ;
    PORT
      LAYER Metal2 ;
        RECT  967.96 0 968.36 0.4 ;
    END
  END mem_req_o.address[24]
  PIN mem_req_o.address[25]
    DIRECTION OUTPUT ;
    USE SIGNAL ;
    PORT
      LAYER Metal2 ;
        RECT  969.88 0 970.28 0.4 ;
    END
  END mem_req_o.address[25]
  PIN mem_req_o.address[26]
    DIRECTION OUTPUT ;
    USE SIGNAL ;
    PORT
      LAYER Metal2 ;
        RECT  971.8 0 972.2 0.4 ;
    END
  END mem_req_o.address[26]
  PIN mem_req_o.address[27]
    DIRECTION OUTPUT ;
    USE SIGNAL ;
    PORT
      LAYER Metal2 ;
        RECT  973.72 0 974.12 0.4 ;
    END
  END mem_req_o.address[27]
  PIN mem_req_o.address[28]
    DIRECTION OUTPUT ;
    USE SIGNAL ;
    PORT
      LAYER Metal2 ;
        RECT  975.64 0 976.04 0.4 ;
    END
  END mem_req_o.address[28]
  PIN mem_req_o.address[29]
    DIRECTION OUTPUT ;
    USE SIGNAL ;
    PORT
      LAYER Metal2 ;
        RECT  977.56 0 977.96 0.4 ;
    END
  END mem_req_o.address[29]
  PIN mem_req_o.address[2]
    DIRECTION OUTPUT ;
    USE SIGNAL ;
    PORT
      LAYER Metal2 ;
        RECT  925.72 0 926.12 0.4 ;
    END
  END mem_req_o.address[2]
  PIN mem_req_o.address[30]
    DIRECTION OUTPUT ;
    USE SIGNAL ;
    PORT
      LAYER Metal2 ;
        RECT  979.48 0 979.88 0.4 ;
    END
  END mem_req_o.address[30]
  PIN mem_req_o.address[31]
    DIRECTION OUTPUT ;
    USE SIGNAL ;
    PORT
      LAYER Metal2 ;
        RECT  981.4 0 981.8 0.4 ;
    END
  END mem_req_o.address[31]
  PIN mem_req_o.address[3]
    DIRECTION OUTPUT ;
    USE SIGNAL ;
    PORT
      LAYER Metal2 ;
        RECT  927.64 0 928.04 0.4 ;
    END
  END mem_req_o.address[3]
  PIN mem_req_o.address[4]
    DIRECTION OUTPUT ;
    USE SIGNAL ;
    PORT
      LAYER Metal2 ;
        RECT  929.56 0 929.96 0.4 ;
    END
  END mem_req_o.address[4]
  PIN mem_req_o.address[5]
    DIRECTION OUTPUT ;
    USE SIGNAL ;
    PORT
      LAYER Metal2 ;
        RECT  931.48 0 931.88 0.4 ;
    END
  END mem_req_o.address[5]
  PIN mem_req_o.address[6]
    DIRECTION OUTPUT ;
    USE SIGNAL ;
    PORT
      LAYER Metal2 ;
        RECT  933.4 0 933.8 0.4 ;
    END
  END mem_req_o.address[6]
  PIN mem_req_o.address[7]
    DIRECTION OUTPUT ;
    USE SIGNAL ;
    PORT
      LAYER Metal2 ;
        RECT  935.32 0 935.72 0.4 ;
    END
  END mem_req_o.address[7]
  PIN mem_req_o.address[8]
    DIRECTION OUTPUT ;
    USE SIGNAL ;
    PORT
      LAYER Metal2 ;
        RECT  937.24 0 937.64 0.4 ;
    END
  END mem_req_o.address[8]
  PIN mem_req_o.address[9]
    DIRECTION OUTPUT ;
    USE SIGNAL ;
    PORT
      LAYER Metal2 ;
        RECT  939.16 0 939.56 0.4 ;
    END
  END mem_req_o.address[9]
  PIN mem_req_o.probe
    DIRECTION OUTPUT ;
    USE SIGNAL ;
    PORT
      LAYER Metal2 ;
        RECT  917.08 0 917.48 0.4 ;
    END
  END mem_req_o.probe
  PIN mem_req_o.size[0]
    DIRECTION OUTPUT ;
    USE SIGNAL ;
    PORT
      LAYER Metal2 ;
        RECT  920.92 0 921.32 0.4 ;
    END
  END mem_req_o.size[0]
  PIN mem_req_o.size[1]
    DIRECTION OUTPUT ;
    USE SIGNAL ;
    PORT
      LAYER Metal2 ;
        RECT  923.8 0 924.2 0.4 ;
    END
  END mem_req_o.size[1]
  PIN mem_req_o.valid
    DIRECTION OUTPUT ;
    USE SIGNAL ;
    PORT
      LAYER Metal2 ;
        RECT  918.04 0 918.44 0.4 ;
    END
  END mem_req_o.valid
  PIN mem_req_o.wdata[0]
    DIRECTION OUTPUT ;
    USE SIGNAL ;
    PORT
      LAYER Metal2 ;
        RECT  921.88 0 922.28 0.4 ;
    END
  END mem_req_o.wdata[0]
  PIN mem_req_o.wdata[10]
    DIRECTION OUTPUT ;
    USE SIGNAL ;
    PORT
      LAYER Metal2 ;
        RECT  942.04 0 942.44 0.4 ;
    END
  END mem_req_o.wdata[10]
  PIN mem_req_o.wdata[11]
    DIRECTION OUTPUT ;
    USE SIGNAL ;
    PORT
      LAYER Metal2 ;
        RECT  943.96 0 944.36 0.4 ;
    END
  END mem_req_o.wdata[11]
  PIN mem_req_o.wdata[12]
    DIRECTION OUTPUT ;
    USE SIGNAL ;
    PORT
      LAYER Metal2 ;
        RECT  945.88 0 946.28 0.4 ;
    END
  END mem_req_o.wdata[12]
  PIN mem_req_o.wdata[13]
    DIRECTION OUTPUT ;
    USE SIGNAL ;
    PORT
      LAYER Metal2 ;
        RECT  947.8 0 948.2 0.4 ;
    END
  END mem_req_o.wdata[13]
  PIN mem_req_o.wdata[14]
    DIRECTION OUTPUT ;
    USE SIGNAL ;
    PORT
      LAYER Metal2 ;
        RECT  949.72 0 950.12 0.4 ;
    END
  END mem_req_o.wdata[14]
  PIN mem_req_o.wdata[15]
    DIRECTION OUTPUT ;
    USE SIGNAL ;
    PORT
      LAYER Metal2 ;
        RECT  951.64 0 952.04 0.4 ;
    END
  END mem_req_o.wdata[15]
  PIN mem_req_o.wdata[16]
    DIRECTION OUTPUT ;
    USE SIGNAL ;
    PORT
      LAYER Metal2 ;
        RECT  953.56 0 953.96 0.4 ;
    END
  END mem_req_o.wdata[16]
  PIN mem_req_o.wdata[17]
    DIRECTION OUTPUT ;
    USE SIGNAL ;
    PORT
      LAYER Metal2 ;
        RECT  955.48 0 955.88 0.4 ;
    END
  END mem_req_o.wdata[17]
  PIN mem_req_o.wdata[18]
    DIRECTION OUTPUT ;
    USE SIGNAL ;
    PORT
      LAYER Metal2 ;
        RECT  957.4 0 957.8 0.4 ;
    END
  END mem_req_o.wdata[18]
  PIN mem_req_o.wdata[19]
    DIRECTION OUTPUT ;
    USE SIGNAL ;
    PORT
      LAYER Metal2 ;
        RECT  959.32 0 959.72 0.4 ;
    END
  END mem_req_o.wdata[19]
  PIN mem_req_o.wdata[1]
    DIRECTION OUTPUT ;
    USE SIGNAL ;
    PORT
      LAYER Metal2 ;
        RECT  924.76 0 925.16 0.4 ;
    END
  END mem_req_o.wdata[1]
  PIN mem_req_o.wdata[20]
    DIRECTION OUTPUT ;
    USE SIGNAL ;
    PORT
      LAYER Metal2 ;
        RECT  961.24 0 961.64 0.4 ;
    END
  END mem_req_o.wdata[20]
  PIN mem_req_o.wdata[21]
    DIRECTION OUTPUT ;
    USE SIGNAL ;
    PORT
      LAYER Metal2 ;
        RECT  963.16 0 963.56 0.4 ;
    END
  END mem_req_o.wdata[21]
  PIN mem_req_o.wdata[22]
    DIRECTION OUTPUT ;
    USE SIGNAL ;
    PORT
      LAYER Metal2 ;
        RECT  965.08 0 965.48 0.4 ;
    END
  END mem_req_o.wdata[22]
  PIN mem_req_o.wdata[23]
    DIRECTION OUTPUT ;
    USE SIGNAL ;
    PORT
      LAYER Metal2 ;
        RECT  967 0 967.4 0.4 ;
    END
  END mem_req_o.wdata[23]
  PIN mem_req_o.wdata[24]
    DIRECTION OUTPUT ;
    USE SIGNAL ;
    PORT
      LAYER Metal2 ;
        RECT  968.92 0 969.32 0.4 ;
    END
  END mem_req_o.wdata[24]
  PIN mem_req_o.wdata[25]
    DIRECTION OUTPUT ;
    USE SIGNAL ;
    PORT
      LAYER Metal2 ;
        RECT  970.84 0 971.24 0.4 ;
    END
  END mem_req_o.wdata[25]
  PIN mem_req_o.wdata[26]
    DIRECTION OUTPUT ;
    USE SIGNAL ;
    PORT
      LAYER Metal2 ;
        RECT  972.76 0 973.16 0.4 ;
    END
  END mem_req_o.wdata[26]
  PIN mem_req_o.wdata[27]
    DIRECTION OUTPUT ;
    USE SIGNAL ;
    PORT
      LAYER Metal2 ;
        RECT  974.68 0 975.08 0.4 ;
    END
  END mem_req_o.wdata[27]
  PIN mem_req_o.wdata[28]
    DIRECTION OUTPUT ;
    USE SIGNAL ;
    PORT
      LAYER Metal2 ;
        RECT  976.6 0 977 0.4 ;
    END
  END mem_req_o.wdata[28]
  PIN mem_req_o.wdata[29]
    DIRECTION OUTPUT ;
    USE SIGNAL ;
    PORT
      LAYER Metal2 ;
        RECT  978.52 0 978.92 0.4 ;
    END
  END mem_req_o.wdata[29]
  PIN mem_req_o.wdata[2]
    DIRECTION OUTPUT ;
    USE SIGNAL ;
    PORT
      LAYER Metal2 ;
        RECT  926.68 0 927.08 0.4 ;
    END
  END mem_req_o.wdata[2]
  PIN mem_req_o.wdata[30]
    DIRECTION OUTPUT ;
    USE SIGNAL ;
    PORT
      LAYER Metal2 ;
        RECT  980.44 0 980.84 0.4 ;
    END
  END mem_req_o.wdata[30]
  PIN mem_req_o.wdata[31]
    DIRECTION OUTPUT ;
    USE SIGNAL ;
    PORT
      LAYER Metal2 ;
        RECT  982.36 0 982.76 0.4 ;
    END
  END mem_req_o.wdata[31]
  PIN mem_req_o.wdata[32]
    DIRECTION OUTPUT ;
    USE SIGNAL ;
    PORT
      LAYER Metal2 ;
        RECT  983.32 0 983.72 0.4 ;
    END
  END mem_req_o.wdata[32]
  PIN mem_req_o.wdata[33]
    DIRECTION OUTPUT ;
    USE SIGNAL ;
    PORT
      LAYER Metal2 ;
        RECT  984.28 0 984.68 0.4 ;
    END
  END mem_req_o.wdata[33]
  PIN mem_req_o.wdata[34]
    DIRECTION OUTPUT ;
    USE SIGNAL ;
    PORT
      LAYER Metal2 ;
        RECT  985.24 0 985.64 0.4 ;
    END
  END mem_req_o.wdata[34]
  PIN mem_req_o.wdata[35]
    DIRECTION OUTPUT ;
    USE SIGNAL ;
    PORT
      LAYER Metal2 ;
        RECT  986.2 0 986.6 0.4 ;
    END
  END mem_req_o.wdata[35]
  PIN mem_req_o.wdata[36]
    DIRECTION OUTPUT ;
    USE SIGNAL ;
    PORT
      LAYER Metal2 ;
        RECT  987.16 0 987.56 0.4 ;
    END
  END mem_req_o.wdata[36]
  PIN mem_req_o.wdata[37]
    DIRECTION OUTPUT ;
    USE SIGNAL ;
    PORT
      LAYER Metal2 ;
        RECT  988.12 0 988.52 0.4 ;
    END
  END mem_req_o.wdata[37]
  PIN mem_req_o.wdata[38]
    DIRECTION OUTPUT ;
    USE SIGNAL ;
    PORT
      LAYER Metal2 ;
        RECT  989.08 0 989.48 0.4 ;
    END
  END mem_req_o.wdata[38]
  PIN mem_req_o.wdata[39]
    DIRECTION OUTPUT ;
    USE SIGNAL ;
    PORT
      LAYER Metal2 ;
        RECT  990.04 0 990.44 0.4 ;
    END
  END mem_req_o.wdata[39]
  PIN mem_req_o.wdata[3]
    DIRECTION OUTPUT ;
    USE SIGNAL ;
    PORT
      LAYER Metal2 ;
        RECT  928.6 0 929 0.4 ;
    END
  END mem_req_o.wdata[3]
  PIN mem_req_o.wdata[40]
    DIRECTION OUTPUT ;
    USE SIGNAL ;
    PORT
      LAYER Metal2 ;
        RECT  991 0 991.4 0.4 ;
    END
  END mem_req_o.wdata[40]
  PIN mem_req_o.wdata[41]
    DIRECTION OUTPUT ;
    USE SIGNAL ;
    PORT
      LAYER Metal2 ;
        RECT  991.96 0 992.36 0.4 ;
    END
  END mem_req_o.wdata[41]
  PIN mem_req_o.wdata[42]
    DIRECTION OUTPUT ;
    USE SIGNAL ;
    PORT
      LAYER Metal2 ;
        RECT  992.92 0 993.32 0.4 ;
    END
  END mem_req_o.wdata[42]
  PIN mem_req_o.wdata[43]
    DIRECTION OUTPUT ;
    USE SIGNAL ;
    PORT
      LAYER Metal2 ;
        RECT  993.88 0 994.28 0.4 ;
    END
  END mem_req_o.wdata[43]
  PIN mem_req_o.wdata[44]
    DIRECTION OUTPUT ;
    USE SIGNAL ;
    PORT
      LAYER Metal2 ;
        RECT  994.84 0 995.24 0.4 ;
    END
  END mem_req_o.wdata[44]
  PIN mem_req_o.wdata[45]
    DIRECTION OUTPUT ;
    USE SIGNAL ;
    PORT
      LAYER Metal2 ;
        RECT  995.8 0 996.2 0.4 ;
    END
  END mem_req_o.wdata[45]
  PIN mem_req_o.wdata[46]
    DIRECTION OUTPUT ;
    USE SIGNAL ;
    PORT
      LAYER Metal2 ;
        RECT  996.76 0 997.16 0.4 ;
    END
  END mem_req_o.wdata[46]
  PIN mem_req_o.wdata[47]
    DIRECTION OUTPUT ;
    USE SIGNAL ;
    PORT
      LAYER Metal2 ;
        RECT  997.72 0 998.12 0.4 ;
    END
  END mem_req_o.wdata[47]
  PIN mem_req_o.wdata[48]
    DIRECTION OUTPUT ;
    USE SIGNAL ;
    PORT
      LAYER Metal2 ;
        RECT  998.68 0 999.08 0.4 ;
    END
  END mem_req_o.wdata[48]
  PIN mem_req_o.wdata[49]
    DIRECTION OUTPUT ;
    USE SIGNAL ;
    PORT
      LAYER Metal2 ;
        RECT  999.64 0 1000.04 0.4 ;
    END
  END mem_req_o.wdata[49]
  PIN mem_req_o.wdata[4]
    DIRECTION OUTPUT ;
    USE SIGNAL ;
    PORT
      LAYER Metal2 ;
        RECT  930.52 0 930.92 0.4 ;
    END
  END mem_req_o.wdata[4]
  PIN mem_req_o.wdata[50]
    DIRECTION OUTPUT ;
    USE SIGNAL ;
    PORT
      LAYER Metal2 ;
        RECT  1000.6 0 1001 0.4 ;
    END
  END mem_req_o.wdata[50]
  PIN mem_req_o.wdata[51]
    DIRECTION OUTPUT ;
    USE SIGNAL ;
    PORT
      LAYER Metal2 ;
        RECT  1001.56 0 1001.96 0.4 ;
    END
  END mem_req_o.wdata[51]
  PIN mem_req_o.wdata[52]
    DIRECTION OUTPUT ;
    USE SIGNAL ;
    PORT
      LAYER Metal2 ;
        RECT  1002.52 0 1002.92 0.4 ;
    END
  END mem_req_o.wdata[52]
  PIN mem_req_o.wdata[53]
    DIRECTION OUTPUT ;
    USE SIGNAL ;
    PORT
      LAYER Metal2 ;
        RECT  1003.48 0 1003.88 0.4 ;
    END
  END mem_req_o.wdata[53]
  PIN mem_req_o.wdata[54]
    DIRECTION OUTPUT ;
    USE SIGNAL ;
    PORT
      LAYER Metal2 ;
        RECT  1004.44 0 1004.84 0.4 ;
    END
  END mem_req_o.wdata[54]
  PIN mem_req_o.wdata[55]
    DIRECTION OUTPUT ;
    USE SIGNAL ;
    PORT
      LAYER Metal2 ;
        RECT  1005.4 0 1005.8 0.4 ;
    END
  END mem_req_o.wdata[55]
  PIN mem_req_o.wdata[56]
    DIRECTION OUTPUT ;
    USE SIGNAL ;
    PORT
      LAYER Metal2 ;
        RECT  1006.36 0 1006.76 0.4 ;
    END
  END mem_req_o.wdata[56]
  PIN mem_req_o.wdata[57]
    DIRECTION OUTPUT ;
    USE SIGNAL ;
    PORT
      LAYER Metal2 ;
        RECT  1007.32 0 1007.72 0.4 ;
    END
  END mem_req_o.wdata[57]
  PIN mem_req_o.wdata[58]
    DIRECTION OUTPUT ;
    USE SIGNAL ;
    PORT
      LAYER Metal2 ;
        RECT  1008.28 0 1008.68 0.4 ;
    END
  END mem_req_o.wdata[58]
  PIN mem_req_o.wdata[59]
    DIRECTION OUTPUT ;
    USE SIGNAL ;
    PORT
      LAYER Metal2 ;
        RECT  1009.24 0 1009.64 0.4 ;
    END
  END mem_req_o.wdata[59]
  PIN mem_req_o.wdata[5]
    DIRECTION OUTPUT ;
    USE SIGNAL ;
    PORT
      LAYER Metal2 ;
        RECT  932.44 0 932.84 0.4 ;
    END
  END mem_req_o.wdata[5]
  PIN mem_req_o.wdata[60]
    DIRECTION OUTPUT ;
    USE SIGNAL ;
    PORT
      LAYER Metal2 ;
        RECT  1010.2 0 1010.6 0.4 ;
    END
  END mem_req_o.wdata[60]
  PIN mem_req_o.wdata[61]
    DIRECTION OUTPUT ;
    USE SIGNAL ;
    PORT
      LAYER Metal2 ;
        RECT  1011.16 0 1011.56 0.4 ;
    END
  END mem_req_o.wdata[61]
  PIN mem_req_o.wdata[62]
    DIRECTION OUTPUT ;
    USE SIGNAL ;
    PORT
      LAYER Metal2 ;
        RECT  1012.12 0 1012.52 0.4 ;
    END
  END mem_req_o.wdata[62]
  PIN mem_req_o.wdata[63]
    DIRECTION OUTPUT ;
    USE SIGNAL ;
    PORT
      LAYER Metal2 ;
        RECT  1013.08 0 1013.48 0.4 ;
    END
  END mem_req_o.wdata[63]
  PIN mem_req_o.wdata[6]
    DIRECTION OUTPUT ;
    USE SIGNAL ;
    PORT
      LAYER Metal2 ;
        RECT  934.36 0 934.76 0.4 ;
    END
  END mem_req_o.wdata[6]
  PIN mem_req_o.wdata[7]
    DIRECTION OUTPUT ;
    USE SIGNAL ;
    PORT
      LAYER Metal2 ;
        RECT  936.28 0 936.68 0.4 ;
    END
  END mem_req_o.wdata[7]
  PIN mem_req_o.wdata[8]
    DIRECTION OUTPUT ;
    USE SIGNAL ;
    PORT
      LAYER Metal2 ;
        RECT  938.2 0 938.6 0.4 ;
    END
  END mem_req_o.wdata[8]
  PIN mem_req_o.wdata[9]
    DIRECTION OUTPUT ;
    USE SIGNAL ;
    PORT
      LAYER Metal2 ;
        RECT  940.12 0 940.52 0.4 ;
    END
  END mem_req_o.wdata[9]
  PIN mem_req_o.write
    DIRECTION OUTPUT ;
    USE SIGNAL ;
    PORT
      LAYER Metal2 ;
        RECT  919 0 919.4 0.4 ;
    END
  END mem_req_o.write
  PIN mem_rsp_i.fault
    DIRECTION INPUT ;
    USE SIGNAL ;
    PORT
      LAYER Metal2 ;
        RECT  1015 0 1015.4 0.4 ;
    END
  END mem_rsp_i.fault
  PIN mem_rsp_i.rdata[0]
    DIRECTION INPUT ;
    USE SIGNAL ;
    PORT
      LAYER Metal2 ;
        RECT  1016.92 0 1017.32 0.4 ;
    END
  END mem_rsp_i.rdata[0]
  PIN mem_rsp_i.rdata[10]
    DIRECTION INPUT ;
    USE SIGNAL ;
    PORT
      LAYER Metal2 ;
        RECT  1026.52 0 1026.92 0.4 ;
    END
  END mem_rsp_i.rdata[10]
  PIN mem_rsp_i.rdata[11]
    DIRECTION INPUT ;
    USE SIGNAL ;
    PORT
      LAYER Metal2 ;
        RECT  1027.48 0 1027.88 0.4 ;
    END
  END mem_rsp_i.rdata[11]
  PIN mem_rsp_i.rdata[12]
    DIRECTION INPUT ;
    USE SIGNAL ;
    PORT
      LAYER Metal2 ;
        RECT  1028.44 0 1028.84 0.4 ;
    END
  END mem_rsp_i.rdata[12]
  PIN mem_rsp_i.rdata[13]
    DIRECTION INPUT ;
    USE SIGNAL ;
    PORT
      LAYER Metal2 ;
        RECT  1029.4 0 1029.8 0.4 ;
    END
  END mem_rsp_i.rdata[13]
  PIN mem_rsp_i.rdata[14]
    DIRECTION INPUT ;
    USE SIGNAL ;
    PORT
      LAYER Metal2 ;
        RECT  1030.36 0 1030.76 0.4 ;
    END
  END mem_rsp_i.rdata[14]
  PIN mem_rsp_i.rdata[15]
    DIRECTION INPUT ;
    USE SIGNAL ;
    PORT
      LAYER Metal2 ;
        RECT  1031.32 0 1031.72 0.4 ;
    END
  END mem_rsp_i.rdata[15]
  PIN mem_rsp_i.rdata[16]
    DIRECTION INPUT ;
    USE SIGNAL ;
    PORT
      LAYER Metal2 ;
        RECT  1032.28 0 1032.68 0.4 ;
    END
  END mem_rsp_i.rdata[16]
  PIN mem_rsp_i.rdata[17]
    DIRECTION INPUT ;
    USE SIGNAL ;
    PORT
      LAYER Metal2 ;
        RECT  1033.24 0 1033.64 0.4 ;
    END
  END mem_rsp_i.rdata[17]
  PIN mem_rsp_i.rdata[18]
    DIRECTION INPUT ;
    USE SIGNAL ;
    PORT
      LAYER Metal2 ;
        RECT  1034.2 0 1034.6 0.4 ;
    END
  END mem_rsp_i.rdata[18]
  PIN mem_rsp_i.rdata[19]
    DIRECTION INPUT ;
    USE SIGNAL ;
    PORT
      LAYER Metal2 ;
        RECT  1035.16 0 1035.56 0.4 ;
    END
  END mem_rsp_i.rdata[19]
  PIN mem_rsp_i.rdata[1]
    DIRECTION INPUT ;
    USE SIGNAL ;
    PORT
      LAYER Metal2 ;
        RECT  1017.88 0 1018.28 0.4 ;
    END
  END mem_rsp_i.rdata[1]
  PIN mem_rsp_i.rdata[20]
    DIRECTION INPUT ;
    USE SIGNAL ;
    PORT
      LAYER Metal2 ;
        RECT  1036.12 0 1036.52 0.4 ;
    END
  END mem_rsp_i.rdata[20]
  PIN mem_rsp_i.rdata[21]
    DIRECTION INPUT ;
    USE SIGNAL ;
    PORT
      LAYER Metal2 ;
        RECT  1037.08 0 1037.48 0.4 ;
    END
  END mem_rsp_i.rdata[21]
  PIN mem_rsp_i.rdata[22]
    DIRECTION INPUT ;
    USE SIGNAL ;
    PORT
      LAYER Metal2 ;
        RECT  1038.04 0 1038.44 0.4 ;
    END
  END mem_rsp_i.rdata[22]
  PIN mem_rsp_i.rdata[23]
    DIRECTION INPUT ;
    USE SIGNAL ;
    PORT
      LAYER Metal2 ;
        RECT  1039 0 1039.4 0.4 ;
    END
  END mem_rsp_i.rdata[23]
  PIN mem_rsp_i.rdata[24]
    DIRECTION INPUT ;
    USE SIGNAL ;
    PORT
      LAYER Metal2 ;
        RECT  1039.96 0 1040.36 0.4 ;
    END
  END mem_rsp_i.rdata[24]
  PIN mem_rsp_i.rdata[25]
    DIRECTION INPUT ;
    USE SIGNAL ;
    PORT
      LAYER Metal2 ;
        RECT  1040.92 0 1041.32 0.4 ;
    END
  END mem_rsp_i.rdata[25]
  PIN mem_rsp_i.rdata[26]
    DIRECTION INPUT ;
    USE SIGNAL ;
    PORT
      LAYER Metal2 ;
        RECT  1041.88 0 1042.28 0.4 ;
    END
  END mem_rsp_i.rdata[26]
  PIN mem_rsp_i.rdata[27]
    DIRECTION INPUT ;
    USE SIGNAL ;
    PORT
      LAYER Metal2 ;
        RECT  1042.84 0 1043.24 0.4 ;
    END
  END mem_rsp_i.rdata[27]
  PIN mem_rsp_i.rdata[28]
    DIRECTION INPUT ;
    USE SIGNAL ;
    PORT
      LAYER Metal2 ;
        RECT  1043.8 0 1044.2 0.4 ;
    END
  END mem_rsp_i.rdata[28]
  PIN mem_rsp_i.rdata[29]
    DIRECTION INPUT ;
    USE SIGNAL ;
    PORT
      LAYER Metal2 ;
        RECT  1044.76 0 1045.16 0.4 ;
    END
  END mem_rsp_i.rdata[29]
  PIN mem_rsp_i.rdata[2]
    DIRECTION INPUT ;
    USE SIGNAL ;
    PORT
      LAYER Metal2 ;
        RECT  1018.84 0 1019.24 0.4 ;
    END
  END mem_rsp_i.rdata[2]
  PIN mem_rsp_i.rdata[30]
    DIRECTION INPUT ;
    USE SIGNAL ;
    PORT
      LAYER Metal2 ;
        RECT  1045.72 0 1046.12 0.4 ;
    END
  END mem_rsp_i.rdata[30]
  PIN mem_rsp_i.rdata[31]
    DIRECTION INPUT ;
    USE SIGNAL ;
    PORT
      LAYER Metal2 ;
        RECT  1046.68 0 1047.08 0.4 ;
    END
  END mem_rsp_i.rdata[31]
  PIN mem_rsp_i.rdata[32]
    DIRECTION INPUT ;
    USE SIGNAL ;
    PORT
      LAYER Metal2 ;
        RECT  1047.64 0 1048.04 0.4 ;
    END
  END mem_rsp_i.rdata[32]
  PIN mem_rsp_i.rdata[33]
    DIRECTION INPUT ;
    USE SIGNAL ;
    PORT
      LAYER Metal2 ;
        RECT  1048.6 0 1049 0.4 ;
    END
  END mem_rsp_i.rdata[33]
  PIN mem_rsp_i.rdata[34]
    DIRECTION INPUT ;
    USE SIGNAL ;
    PORT
      LAYER Metal2 ;
        RECT  1049.56 0 1049.96 0.4 ;
    END
  END mem_rsp_i.rdata[34]
  PIN mem_rsp_i.rdata[35]
    DIRECTION INPUT ;
    USE SIGNAL ;
    PORT
      LAYER Metal2 ;
        RECT  1050.52 0 1050.92 0.4 ;
    END
  END mem_rsp_i.rdata[35]
  PIN mem_rsp_i.rdata[36]
    DIRECTION INPUT ;
    USE SIGNAL ;
    PORT
      LAYER Metal2 ;
        RECT  1051.48 0 1051.88 0.4 ;
    END
  END mem_rsp_i.rdata[36]
  PIN mem_rsp_i.rdata[37]
    DIRECTION INPUT ;
    USE SIGNAL ;
    PORT
      LAYER Metal2 ;
        RECT  1052.44 0 1052.84 0.4 ;
    END
  END mem_rsp_i.rdata[37]
  PIN mem_rsp_i.rdata[38]
    DIRECTION INPUT ;
    USE SIGNAL ;
    PORT
      LAYER Metal2 ;
        RECT  1053.4 0 1053.8 0.4 ;
    END
  END mem_rsp_i.rdata[38]
  PIN mem_rsp_i.rdata[39]
    DIRECTION INPUT ;
    USE SIGNAL ;
    PORT
      LAYER Metal2 ;
        RECT  1054.36 0 1054.76 0.4 ;
    END
  END mem_rsp_i.rdata[39]
  PIN mem_rsp_i.rdata[3]
    DIRECTION INPUT ;
    USE SIGNAL ;
    PORT
      LAYER Metal2 ;
        RECT  1019.8 0 1020.2 0.4 ;
    END
  END mem_rsp_i.rdata[3]
  PIN mem_rsp_i.rdata[40]
    DIRECTION INPUT ;
    USE SIGNAL ;
    PORT
      LAYER Metal2 ;
        RECT  1055.32 0 1055.72 0.4 ;
    END
  END mem_rsp_i.rdata[40]
  PIN mem_rsp_i.rdata[41]
    DIRECTION INPUT ;
    USE SIGNAL ;
    PORT
      LAYER Metal2 ;
        RECT  1056.28 0 1056.68 0.4 ;
    END
  END mem_rsp_i.rdata[41]
  PIN mem_rsp_i.rdata[42]
    DIRECTION INPUT ;
    USE SIGNAL ;
    PORT
      LAYER Metal2 ;
        RECT  1057.24 0 1057.64 0.4 ;
    END
  END mem_rsp_i.rdata[42]
  PIN mem_rsp_i.rdata[43]
    DIRECTION INPUT ;
    USE SIGNAL ;
    PORT
      LAYER Metal2 ;
        RECT  1058.2 0 1058.6 0.4 ;
    END
  END mem_rsp_i.rdata[43]
  PIN mem_rsp_i.rdata[44]
    DIRECTION INPUT ;
    USE SIGNAL ;
    PORT
      LAYER Metal2 ;
        RECT  1059.16 0 1059.56 0.4 ;
    END
  END mem_rsp_i.rdata[44]
  PIN mem_rsp_i.rdata[45]
    DIRECTION INPUT ;
    USE SIGNAL ;
    PORT
      LAYER Metal2 ;
        RECT  1060.12 0 1060.52 0.4 ;
    END
  END mem_rsp_i.rdata[45]
  PIN mem_rsp_i.rdata[46]
    DIRECTION INPUT ;
    USE SIGNAL ;
    PORT
      LAYER Metal2 ;
        RECT  1061.08 0 1061.48 0.4 ;
    END
  END mem_rsp_i.rdata[46]
  PIN mem_rsp_i.rdata[47]
    DIRECTION INPUT ;
    USE SIGNAL ;
    PORT
      LAYER Metal2 ;
        RECT  1062.04 0 1062.44 0.4 ;
    END
  END mem_rsp_i.rdata[47]
  PIN mem_rsp_i.rdata[48]
    DIRECTION INPUT ;
    USE SIGNAL ;
    PORT
      LAYER Metal2 ;
        RECT  1063 0 1063.4 0.4 ;
    END
  END mem_rsp_i.rdata[48]
  PIN mem_rsp_i.rdata[49]
    DIRECTION INPUT ;
    USE SIGNAL ;
    PORT
      LAYER Metal2 ;
        RECT  1063.96 0 1064.36 0.4 ;
    END
  END mem_rsp_i.rdata[49]
  PIN mem_rsp_i.rdata[4]
    DIRECTION INPUT ;
    USE SIGNAL ;
    PORT
      LAYER Metal2 ;
        RECT  1020.76 0 1021.16 0.4 ;
    END
  END mem_rsp_i.rdata[4]
  PIN mem_rsp_i.rdata[50]
    DIRECTION INPUT ;
    USE SIGNAL ;
    PORT
      LAYER Metal2 ;
        RECT  1064.92 0 1065.32 0.4 ;
    END
  END mem_rsp_i.rdata[50]
  PIN mem_rsp_i.rdata[51]
    DIRECTION INPUT ;
    USE SIGNAL ;
    PORT
      LAYER Metal2 ;
        RECT  1065.88 0 1066.28 0.4 ;
    END
  END mem_rsp_i.rdata[51]
  PIN mem_rsp_i.rdata[52]
    DIRECTION INPUT ;
    USE SIGNAL ;
    PORT
      LAYER Metal2 ;
        RECT  1066.84 0 1067.24 0.4 ;
    END
  END mem_rsp_i.rdata[52]
  PIN mem_rsp_i.rdata[53]
    DIRECTION INPUT ;
    USE SIGNAL ;
    PORT
      LAYER Metal2 ;
        RECT  1067.8 0 1068.2 0.4 ;
    END
  END mem_rsp_i.rdata[53]
  PIN mem_rsp_i.rdata[54]
    DIRECTION INPUT ;
    USE SIGNAL ;
    PORT
      LAYER Metal2 ;
        RECT  1068.76 0 1069.16 0.4 ;
    END
  END mem_rsp_i.rdata[54]
  PIN mem_rsp_i.rdata[55]
    DIRECTION INPUT ;
    USE SIGNAL ;
    PORT
      LAYER Metal2 ;
        RECT  1069.72 0 1070.12 0.4 ;
    END
  END mem_rsp_i.rdata[55]
  PIN mem_rsp_i.rdata[56]
    DIRECTION INPUT ;
    USE SIGNAL ;
    PORT
      LAYER Metal2 ;
        RECT  1070.68 0 1071.08 0.4 ;
    END
  END mem_rsp_i.rdata[56]
  PIN mem_rsp_i.rdata[57]
    DIRECTION INPUT ;
    USE SIGNAL ;
    PORT
      LAYER Metal2 ;
        RECT  1071.64 0 1072.04 0.4 ;
    END
  END mem_rsp_i.rdata[57]
  PIN mem_rsp_i.rdata[58]
    DIRECTION INPUT ;
    USE SIGNAL ;
    PORT
      LAYER Metal2 ;
        RECT  1072.6 0 1073 0.4 ;
    END
  END mem_rsp_i.rdata[58]
  PIN mem_rsp_i.rdata[59]
    DIRECTION INPUT ;
    USE SIGNAL ;
    PORT
      LAYER Metal2 ;
        RECT  1073.56 0 1073.96 0.4 ;
    END
  END mem_rsp_i.rdata[59]
  PIN mem_rsp_i.rdata[5]
    DIRECTION INPUT ;
    USE SIGNAL ;
    PORT
      LAYER Metal2 ;
        RECT  1021.72 0 1022.12 0.4 ;
    END
  END mem_rsp_i.rdata[5]
  PIN mem_rsp_i.rdata[60]
    DIRECTION INPUT ;
    USE SIGNAL ;
    PORT
      LAYER Metal2 ;
        RECT  1074.52 0 1074.92 0.4 ;
    END
  END mem_rsp_i.rdata[60]
  PIN mem_rsp_i.rdata[61]
    DIRECTION INPUT ;
    USE SIGNAL ;
    PORT
      LAYER Metal2 ;
        RECT  1075.48 0 1075.88 0.4 ;
    END
  END mem_rsp_i.rdata[61]
  PIN mem_rsp_i.rdata[62]
    DIRECTION INPUT ;
    USE SIGNAL ;
    PORT
      LAYER Metal2 ;
        RECT  1076.44 0 1076.84 0.4 ;
    END
  END mem_rsp_i.rdata[62]
  PIN mem_rsp_i.rdata[63]
    DIRECTION INPUT ;
    USE SIGNAL ;
    PORT
      LAYER Metal2 ;
        RECT  1077.4 0 1077.8 0.4 ;
    END
  END mem_rsp_i.rdata[63]
  PIN mem_rsp_i.rdata[6]
    DIRECTION INPUT ;
    USE SIGNAL ;
    PORT
      LAYER Metal2 ;
        RECT  1022.68 0 1023.08 0.4 ;
    END
  END mem_rsp_i.rdata[6]
  PIN mem_rsp_i.rdata[7]
    DIRECTION INPUT ;
    USE SIGNAL ;
    PORT
      LAYER Metal2 ;
        RECT  1023.64 0 1024.04 0.4 ;
    END
  END mem_rsp_i.rdata[7]
  PIN mem_rsp_i.rdata[8]
    DIRECTION INPUT ;
    USE SIGNAL ;
    PORT
      LAYER Metal2 ;
        RECT  1024.6 0 1025 0.4 ;
    END
  END mem_rsp_i.rdata[8]
  PIN mem_rsp_i.rdata[9]
    DIRECTION INPUT ;
    USE SIGNAL ;
    PORT
      LAYER Metal2 ;
        RECT  1025.56 0 1025.96 0.4 ;
    END
  END mem_rsp_i.rdata[9]
  PIN mem_rsp_i.valid
    DIRECTION INPUT ;
    USE SIGNAL ;
    PORT
      LAYER Metal2 ;
        RECT  1015.96 0 1016.36 0.4 ;
    END
  END mem_rsp_i.valid
  PIN reset_i
    DIRECTION INPUT ;
    USE SIGNAL ;
    PORT
      LAYER Metal2 ;
        RECT  23.32 1499.6 23.72 1500 ;
    END
  END reset_i
  PIN sync_dsp_i[0]
    DIRECTION INPUT ;
    USE SIGNAL ;
    PORT
      LAYER Metal3 ;
        RECT  1499.6 835.18 1500 835.58 ;
    END
  END sync_dsp_i[0]
  PIN sync_dsp_i[10]
    DIRECTION INPUT ;
    USE SIGNAL ;
    PORT
      LAYER Metal3 ;
        RECT  1499.6 893.98 1500 894.38 ;
    END
  END sync_dsp_i[10]
  PIN sync_dsp_i[11]
    DIRECTION INPUT ;
    USE SIGNAL ;
    PORT
      LAYER Metal3 ;
        RECT  1499.6 899.86 1500 900.26 ;
    END
  END sync_dsp_i[11]
  PIN sync_dsp_i[12]
    DIRECTION INPUT ;
    USE SIGNAL ;
    PORT
      LAYER Metal3 ;
        RECT  1499.6 905.74 1500 906.14 ;
    END
  END sync_dsp_i[12]
  PIN sync_dsp_i[13]
    DIRECTION INPUT ;
    USE SIGNAL ;
    PORT
      LAYER Metal3 ;
        RECT  1499.6 911.62 1500 912.02 ;
    END
  END sync_dsp_i[13]
  PIN sync_dsp_i[14]
    DIRECTION INPUT ;
    USE SIGNAL ;
    PORT
      LAYER Metal3 ;
        RECT  1499.6 917.5 1500 917.9 ;
    END
  END sync_dsp_i[14]
  PIN sync_dsp_i[15]
    DIRECTION INPUT ;
    USE SIGNAL ;
    PORT
      LAYER Metal3 ;
        RECT  1499.6 923.38 1500 923.78 ;
    END
  END sync_dsp_i[15]
  PIN sync_dsp_i[16]
    DIRECTION INPUT ;
    USE SIGNAL ;
    PORT
      LAYER Metal3 ;
        RECT  1499.6 929.26 1500 929.66 ;
    END
  END sync_dsp_i[16]
  PIN sync_dsp_i[17]
    DIRECTION INPUT ;
    USE SIGNAL ;
    PORT
      LAYER Metal3 ;
        RECT  1499.6 935.14 1500 935.54 ;
    END
  END sync_dsp_i[17]
  PIN sync_dsp_i[18]
    DIRECTION INPUT ;
    USE SIGNAL ;
    PORT
      LAYER Metal3 ;
        RECT  1499.6 941.02 1500 941.42 ;
    END
  END sync_dsp_i[18]
  PIN sync_dsp_i[19]
    DIRECTION INPUT ;
    USE SIGNAL ;
    PORT
      LAYER Metal3 ;
        RECT  1499.6 946.9 1500 947.3 ;
    END
  END sync_dsp_i[19]
  PIN sync_dsp_i[1]
    DIRECTION INPUT ;
    USE SIGNAL ;
    PORT
      LAYER Metal3 ;
        RECT  1499.6 841.06 1500 841.46 ;
    END
  END sync_dsp_i[1]
  PIN sync_dsp_i[20]
    DIRECTION INPUT ;
    USE SIGNAL ;
    PORT
      LAYER Metal3 ;
        RECT  1499.6 952.78 1500 953.18 ;
    END
  END sync_dsp_i[20]
  PIN sync_dsp_i[21]
    DIRECTION INPUT ;
    USE SIGNAL ;
    PORT
      LAYER Metal3 ;
        RECT  1499.6 958.66 1500 959.06 ;
    END
  END sync_dsp_i[21]
  PIN sync_dsp_i[22]
    DIRECTION INPUT ;
    USE SIGNAL ;
    PORT
      LAYER Metal3 ;
        RECT  1499.6 964.54 1500 964.94 ;
    END
  END sync_dsp_i[22]
  PIN sync_dsp_i[23]
    DIRECTION INPUT ;
    USE SIGNAL ;
    PORT
      LAYER Metal3 ;
        RECT  1499.6 970.42 1500 970.82 ;
    END
  END sync_dsp_i[23]
  PIN sync_dsp_i[24]
    DIRECTION INPUT ;
    USE SIGNAL ;
    PORT
      LAYER Metal3 ;
        RECT  1499.6 976.3 1500 976.7 ;
    END
  END sync_dsp_i[24]
  PIN sync_dsp_i[25]
    DIRECTION INPUT ;
    USE SIGNAL ;
    PORT
      LAYER Metal3 ;
        RECT  1499.6 982.18 1500 982.58 ;
    END
  END sync_dsp_i[25]
  PIN sync_dsp_i[26]
    DIRECTION INPUT ;
    USE SIGNAL ;
    PORT
      LAYER Metal3 ;
        RECT  1499.6 988.06 1500 988.46 ;
    END
  END sync_dsp_i[26]
  PIN sync_dsp_i[27]
    DIRECTION INPUT ;
    USE SIGNAL ;
    PORT
      LAYER Metal3 ;
        RECT  1499.6 993.94 1500 994.34 ;
    END
  END sync_dsp_i[27]
  PIN sync_dsp_i[28]
    DIRECTION INPUT ;
    USE SIGNAL ;
    PORT
      LAYER Metal3 ;
        RECT  1499.6 999.82 1500 1000.22 ;
    END
  END sync_dsp_i[28]
  PIN sync_dsp_i[29]
    DIRECTION INPUT ;
    USE SIGNAL ;
    PORT
      LAYER Metal3 ;
        RECT  1499.6 1005.7 1500 1006.1 ;
    END
  END sync_dsp_i[29]
  PIN sync_dsp_i[2]
    DIRECTION INPUT ;
    USE SIGNAL ;
    PORT
      LAYER Metal3 ;
        RECT  1499.6 846.94 1500 847.34 ;
    END
  END sync_dsp_i[2]
  PIN sync_dsp_i[30]
    DIRECTION INPUT ;
    USE SIGNAL ;
    PORT
      LAYER Metal3 ;
        RECT  1499.6 1011.58 1500 1011.98 ;
    END
  END sync_dsp_i[30]
  PIN sync_dsp_i[31]
    DIRECTION INPUT ;
    USE SIGNAL ;
    PORT
      LAYER Metal3 ;
        RECT  1499.6 1017.46 1500 1017.86 ;
    END
  END sync_dsp_i[31]
  PIN sync_dsp_i[3]
    DIRECTION INPUT ;
    USE SIGNAL ;
    PORT
      LAYER Metal3 ;
        RECT  1499.6 852.82 1500 853.22 ;
    END
  END sync_dsp_i[3]
  PIN sync_dsp_i[4]
    DIRECTION INPUT ;
    USE SIGNAL ;
    PORT
      LAYER Metal3 ;
        RECT  1499.6 858.7 1500 859.1 ;
    END
  END sync_dsp_i[4]
  PIN sync_dsp_i[5]
    DIRECTION INPUT ;
    USE SIGNAL ;
    PORT
      LAYER Metal3 ;
        RECT  1499.6 864.58 1500 864.98 ;
    END
  END sync_dsp_i[5]
  PIN sync_dsp_i[6]
    DIRECTION INPUT ;
    USE SIGNAL ;
    PORT
      LAYER Metal3 ;
        RECT  1499.6 870.46 1500 870.86 ;
    END
  END sync_dsp_i[6]
  PIN sync_dsp_i[7]
    DIRECTION INPUT ;
    USE SIGNAL ;
    PORT
      LAYER Metal3 ;
        RECT  1499.6 876.34 1500 876.74 ;
    END
  END sync_dsp_i[7]
  PIN sync_dsp_i[8]
    DIRECTION INPUT ;
    USE SIGNAL ;
    PORT
      LAYER Metal3 ;
        RECT  1499.6 882.22 1500 882.62 ;
    END
  END sync_dsp_i[8]
  PIN sync_dsp_i[9]
    DIRECTION INPUT ;
    USE SIGNAL ;
    PORT
      LAYER Metal3 ;
        RECT  1499.6 888.1 1500 888.5 ;
    END
  END sync_dsp_i[9]
  PIN sync_rsp_i[0]
    DIRECTION INPUT ;
    USE SIGNAL ;
    PORT
      LAYER Metal3 ;
        RECT  1499.6 1023.34 1500 1023.74 ;
    END
  END sync_rsp_i[0]
  PIN sync_rsp_i[10]
    DIRECTION INPUT ;
    USE SIGNAL ;
    PORT
      LAYER Metal3 ;
        RECT  1499.6 1082.14 1500 1082.54 ;
    END
  END sync_rsp_i[10]
  PIN sync_rsp_i[11]
    DIRECTION INPUT ;
    USE SIGNAL ;
    PORT
      LAYER Metal3 ;
        RECT  1499.6 1088.02 1500 1088.42 ;
    END
  END sync_rsp_i[11]
  PIN sync_rsp_i[12]
    DIRECTION INPUT ;
    USE SIGNAL ;
    PORT
      LAYER Metal3 ;
        RECT  1499.6 1093.9 1500 1094.3 ;
    END
  END sync_rsp_i[12]
  PIN sync_rsp_i[13]
    DIRECTION INPUT ;
    USE SIGNAL ;
    PORT
      LAYER Metal3 ;
        RECT  1499.6 1099.78 1500 1100.18 ;
    END
  END sync_rsp_i[13]
  PIN sync_rsp_i[14]
    DIRECTION INPUT ;
    USE SIGNAL ;
    PORT
      LAYER Metal3 ;
        RECT  1499.6 1105.66 1500 1106.06 ;
    END
  END sync_rsp_i[14]
  PIN sync_rsp_i[15]
    DIRECTION INPUT ;
    USE SIGNAL ;
    PORT
      LAYER Metal3 ;
        RECT  1499.6 1111.54 1500 1111.94 ;
    END
  END sync_rsp_i[15]
  PIN sync_rsp_i[16]
    DIRECTION INPUT ;
    USE SIGNAL ;
    PORT
      LAYER Metal3 ;
        RECT  1499.6 1117.42 1500 1117.82 ;
    END
  END sync_rsp_i[16]
  PIN sync_rsp_i[17]
    DIRECTION INPUT ;
    USE SIGNAL ;
    PORT
      LAYER Metal3 ;
        RECT  1499.6 1123.3 1500 1123.7 ;
    END
  END sync_rsp_i[17]
  PIN sync_rsp_i[18]
    DIRECTION INPUT ;
    USE SIGNAL ;
    PORT
      LAYER Metal3 ;
        RECT  1499.6 1129.18 1500 1129.58 ;
    END
  END sync_rsp_i[18]
  PIN sync_rsp_i[19]
    DIRECTION INPUT ;
    USE SIGNAL ;
    PORT
      LAYER Metal3 ;
        RECT  1499.6 1135.06 1500 1135.46 ;
    END
  END sync_rsp_i[19]
  PIN sync_rsp_i[1]
    DIRECTION INPUT ;
    USE SIGNAL ;
    PORT
      LAYER Metal3 ;
        RECT  1499.6 1029.22 1500 1029.62 ;
    END
  END sync_rsp_i[1]
  PIN sync_rsp_i[20]
    DIRECTION INPUT ;
    USE SIGNAL ;
    PORT
      LAYER Metal3 ;
        RECT  1499.6 1140.94 1500 1141.34 ;
    END
  END sync_rsp_i[20]
  PIN sync_rsp_i[21]
    DIRECTION INPUT ;
    USE SIGNAL ;
    PORT
      LAYER Metal3 ;
        RECT  1499.6 1146.82 1500 1147.22 ;
    END
  END sync_rsp_i[21]
  PIN sync_rsp_i[22]
    DIRECTION INPUT ;
    USE SIGNAL ;
    PORT
      LAYER Metal3 ;
        RECT  1499.6 1152.7 1500 1153.1 ;
    END
  END sync_rsp_i[22]
  PIN sync_rsp_i[23]
    DIRECTION INPUT ;
    USE SIGNAL ;
    PORT
      LAYER Metal3 ;
        RECT  1499.6 1158.58 1500 1158.98 ;
    END
  END sync_rsp_i[23]
  PIN sync_rsp_i[24]
    DIRECTION INPUT ;
    USE SIGNAL ;
    PORT
      LAYER Metal3 ;
        RECT  1499.6 1164.46 1500 1164.86 ;
    END
  END sync_rsp_i[24]
  PIN sync_rsp_i[25]
    DIRECTION INPUT ;
    USE SIGNAL ;
    PORT
      LAYER Metal3 ;
        RECT  1499.6 1170.34 1500 1170.74 ;
    END
  END sync_rsp_i[25]
  PIN sync_rsp_i[26]
    DIRECTION INPUT ;
    USE SIGNAL ;
    PORT
      LAYER Metal3 ;
        RECT  1499.6 1176.22 1500 1176.62 ;
    END
  END sync_rsp_i[26]
  PIN sync_rsp_i[27]
    DIRECTION INPUT ;
    USE SIGNAL ;
    PORT
      LAYER Metal3 ;
        RECT  1499.6 1182.1 1500 1182.5 ;
    END
  END sync_rsp_i[27]
  PIN sync_rsp_i[28]
    DIRECTION INPUT ;
    USE SIGNAL ;
    PORT
      LAYER Metal3 ;
        RECT  1499.6 1187.98 1500 1188.38 ;
    END
  END sync_rsp_i[28]
  PIN sync_rsp_i[29]
    DIRECTION INPUT ;
    USE SIGNAL ;
    PORT
      LAYER Metal3 ;
        RECT  1499.6 1193.86 1500 1194.26 ;
    END
  END sync_rsp_i[29]
  PIN sync_rsp_i[2]
    DIRECTION INPUT ;
    USE SIGNAL ;
    PORT
      LAYER Metal3 ;
        RECT  1499.6 1035.1 1500 1035.5 ;
    END
  END sync_rsp_i[2]
  PIN sync_rsp_i[30]
    DIRECTION INPUT ;
    USE SIGNAL ;
    PORT
      LAYER Metal3 ;
        RECT  1499.6 1199.74 1500 1200.14 ;
    END
  END sync_rsp_i[30]
  PIN sync_rsp_i[31]
    DIRECTION INPUT ;
    USE SIGNAL ;
    PORT
      LAYER Metal3 ;
        RECT  1499.6 1205.62 1500 1206.02 ;
    END
  END sync_rsp_i[31]
  PIN sync_rsp_i[3]
    DIRECTION INPUT ;
    USE SIGNAL ;
    PORT
      LAYER Metal3 ;
        RECT  1499.6 1040.98 1500 1041.38 ;
    END
  END sync_rsp_i[3]
  PIN sync_rsp_i[4]
    DIRECTION INPUT ;
    USE SIGNAL ;
    PORT
      LAYER Metal3 ;
        RECT  1499.6 1046.86 1500 1047.26 ;
    END
  END sync_rsp_i[4]
  PIN sync_rsp_i[5]
    DIRECTION INPUT ;
    USE SIGNAL ;
    PORT
      LAYER Metal3 ;
        RECT  1499.6 1052.74 1500 1053.14 ;
    END
  END sync_rsp_i[5]
  PIN sync_rsp_i[6]
    DIRECTION INPUT ;
    USE SIGNAL ;
    PORT
      LAYER Metal3 ;
        RECT  1499.6 1058.62 1500 1059.02 ;
    END
  END sync_rsp_i[6]
  PIN sync_rsp_i[7]
    DIRECTION INPUT ;
    USE SIGNAL ;
    PORT
      LAYER Metal3 ;
        RECT  1499.6 1064.5 1500 1064.9 ;
    END
  END sync_rsp_i[7]
  PIN sync_rsp_i[8]
    DIRECTION INPUT ;
    USE SIGNAL ;
    PORT
      LAYER Metal3 ;
        RECT  1499.6 1070.38 1500 1070.78 ;
    END
  END sync_rsp_i[8]
  PIN sync_rsp_i[9]
    DIRECTION INPUT ;
    USE SIGNAL ;
    PORT
      LAYER Metal3 ;
        RECT  1499.6 1076.26 1500 1076.66 ;
    END
  END sync_rsp_i[9]
  PIN sync_valid_i
    DIRECTION INPUT ;
    USE SIGNAL ;
    PORT
      LAYER Metal3 ;
        RECT  1499.6 829.3 1500 829.7 ;
    END
  END sync_valid_i
  PIN VPWR
    DIRECTION INOUT ;
    USE POWER ;
    PORT
      LAYER TopMetal1 ;
        RECT  5.76 1474.12 1494.24 1476.12 ;
        RECT  5.76 1424.12 1494.24 1426.12 ;
        RECT  5.76 1374.12 1494.24 1376.12 ;
        RECT  5.76 1324.12 1494.24 1326.12 ;
        RECT  5.76 1274.12 1494.24 1276.12 ;
        RECT  5.76 1224.12 1494.24 1226.12 ;
        RECT  5.76 1174.12 1494.24 1176.12 ;
        RECT  5.76 1124.12 1494.24 1126.12 ;
        RECT  5.76 1074.12 1494.24 1076.12 ;
        RECT  5.76 1024.12 1494.24 1026.12 ;
        RECT  5.76 974.12 1494.24 976.12 ;
        RECT  5.76 924.12 1494.24 926.12 ;
        RECT  5.76 874.12 1494.24 876.12 ;
        RECT  5.76 824.12 1494.24 826.12 ;
        RECT  5.76 774.12 1494.24 776.12 ;
        RECT  5.76 724.12 1494.24 726.12 ;
        RECT  5.76 674.12 1494.24 676.12 ;
        RECT  5.76 624.12 1494.24 626.12 ;
        RECT  5.76 574.12 1494.24 576.12 ;
        RECT  5.76 524.12 1494.24 526.12 ;
        RECT  5.76 474.12 1494.24 476.12 ;
        RECT  5.76 424.12 1494.24 426.12 ;
        RECT  5.76 374.12 1494.24 376.12 ;
        RECT  5.76 324.12 1494.24 326.12 ;
        RECT  5.76 274.12 1494.24 276.12 ;
        RECT  5.76 224.12 1494.24 226.12 ;
        RECT  5.76 174.12 1494.24 176.12 ;
        RECT  5.76 124.12 1494.24 126.12 ;
        RECT  5.76 74.12 1494.24 76.12 ;
        RECT  5.76 24.12 1494.24 26.12 ;
      LAYER Metal4 ;
        RECT  1465.26 14.9 1466.26 1481.98 ;
        RECT  1415.26 14.9 1416.26 1481.98 ;
        RECT  1365.26 14.9 1366.26 1481.98 ;
        RECT  1315.26 14.9 1316.26 1481.98 ;
        RECT  1265.26 14.9 1266.26 1481.98 ;
        RECT  1215.26 14.9 1216.26 1481.98 ;
        RECT  1165.26 14.9 1166.26 1481.98 ;
        RECT  1115.26 14.9 1116.26 1481.98 ;
        RECT  1065.26 14.9 1066.26 1481.98 ;
        RECT  1015.26 14.9 1016.26 1481.98 ;
        RECT  965.26 14.9 966.26 1481.98 ;
        RECT  915.26 14.9 916.26 1481.98 ;
        RECT  865.26 14.9 866.26 1481.98 ;
        RECT  815.26 14.9 816.26 1481.98 ;
        RECT  765.26 14.9 766.26 1481.98 ;
        RECT  715.26 14.9 716.26 1481.98 ;
        RECT  665.26 14.9 666.26 1481.98 ;
        RECT  615.26 14.9 616.26 1481.98 ;
        RECT  565.26 14.9 566.26 1481.98 ;
        RECT  515.26 14.9 516.26 1481.98 ;
        RECT  465.26 14.9 466.26 1481.98 ;
        RECT  415.26 14.9 416.26 1481.98 ;
        RECT  365.26 14.9 366.26 1481.98 ;
        RECT  315.26 14.9 316.26 1481.98 ;
        RECT  265.26 14.9 266.26 1481.98 ;
        RECT  215.26 14.9 216.26 1481.98 ;
        RECT  165.26 14.9 166.26 1481.98 ;
        RECT  115.26 14.9 116.26 1481.98 ;
        RECT  65.26 14.9 66.26 1481.98 ;
        RECT  15.26 14.9 16.26 1481.98 ;
    END
  END VPWR
  PIN VGND
    DIRECTION INOUT ;
    USE GROUND ;
    PORT
      LAYER TopMetal1 ;
        RECT  5.76 1480.12 1494.24 1482.12 ;
        RECT  5.76 1430.12 1494.24 1432.12 ;
        RECT  5.76 1380.12 1494.24 1382.12 ;
        RECT  5.76 1330.12 1494.24 1332.12 ;
        RECT  5.76 1280.12 1494.24 1282.12 ;
        RECT  5.76 1230.12 1494.24 1232.12 ;
        RECT  5.76 1180.12 1494.24 1182.12 ;
        RECT  5.76 1130.12 1494.24 1132.12 ;
        RECT  5.76 1080.12 1494.24 1082.12 ;
        RECT  5.76 1030.12 1494.24 1032.12 ;
        RECT  5.76 980.12 1494.24 982.12 ;
        RECT  5.76 930.12 1494.24 932.12 ;
        RECT  5.76 880.12 1494.24 882.12 ;
        RECT  5.76 830.12 1494.24 832.12 ;
        RECT  5.76 780.12 1494.24 782.12 ;
        RECT  5.76 730.12 1494.24 732.12 ;
        RECT  5.76 680.12 1494.24 682.12 ;
        RECT  5.76 630.12 1494.24 632.12 ;
        RECT  5.76 580.12 1494.24 582.12 ;
        RECT  5.76 530.12 1494.24 532.12 ;
        RECT  5.76 480.12 1494.24 482.12 ;
        RECT  5.76 430.12 1494.24 432.12 ;
        RECT  5.76 380.12 1494.24 382.12 ;
        RECT  5.76 330.12 1494.24 332.12 ;
        RECT  5.76 280.12 1494.24 282.12 ;
        RECT  5.76 230.12 1494.24 232.12 ;
        RECT  5.76 180.12 1494.24 182.12 ;
        RECT  5.76 130.12 1494.24 132.12 ;
        RECT  5.76 80.12 1494.24 82.12 ;
        RECT  5.76 30.12 1494.24 32.12 ;
      LAYER Metal4 ;
        RECT  1468.26 14.9 1469.26 1482.12 ;
        RECT  1418.26 14.9 1419.26 1482.12 ;
        RECT  1368.26 14.9 1369.26 1482.12 ;
        RECT  1318.26 14.9 1319.26 1482.12 ;
        RECT  1268.26 14.9 1269.26 1482.12 ;
        RECT  1218.26 14.9 1219.26 1482.12 ;
        RECT  1168.26 14.9 1169.26 1482.12 ;
        RECT  1118.26 14.9 1119.26 1482.12 ;
        RECT  1068.26 14.9 1069.26 1482.12 ;
        RECT  1018.26 14.9 1019.26 1482.12 ;
        RECT  968.26 14.9 969.26 1482.12 ;
        RECT  918.26 14.9 919.26 1482.12 ;
        RECT  868.26 14.9 869.26 1482.12 ;
        RECT  818.26 14.9 819.26 1482.12 ;
        RECT  768.26 14.9 769.26 1482.12 ;
        RECT  718.26 14.9 719.26 1482.12 ;
        RECT  668.26 14.9 669.26 1482.12 ;
        RECT  618.26 14.9 619.26 1482.12 ;
        RECT  568.26 14.9 569.26 1482.12 ;
        RECT  518.26 14.9 519.26 1482.12 ;
        RECT  468.26 14.9 469.26 1482.12 ;
        RECT  418.26 14.9 419.26 1482.12 ;
        RECT  368.26 14.9 369.26 1482.12 ;
        RECT  318.26 14.9 319.26 1482.12 ;
        RECT  268.26 14.9 269.26 1482.12 ;
        RECT  218.26 14.9 219.26 1482.12 ;
        RECT  168.26 14.9 169.26 1482.12 ;
        RECT  118.26 14.9 119.26 1482.12 ;
        RECT  68.26 14.9 69.26 1482.12 ;
        RECT  18.26 14.9 19.26 1482.12 ;
    END
  END VGND
  OBS
    LAYER Metal1 ;
     RECT  0 0 1500 1500 ;
    LAYER Metal2 ;
     RECT  0 0 1500 1500 ;
    LAYER Metal3 ;
     RECT  0 0 1500 1500 ;
    LAYER Metal4 ;
     RECT  0 0 1500 1500 ;
    LAYER TopMetal1 ;
     RECT  0 0 1500 1500 ;
  END
END stack_unit_16_8
END LIBRARY
